VERSION 5.8 ;
BUSBITCHARS "[]" ;
DIVIDERCHAR "/" ;
UNITS
    DATABASE MICRONS 1000 ;
END UNITS

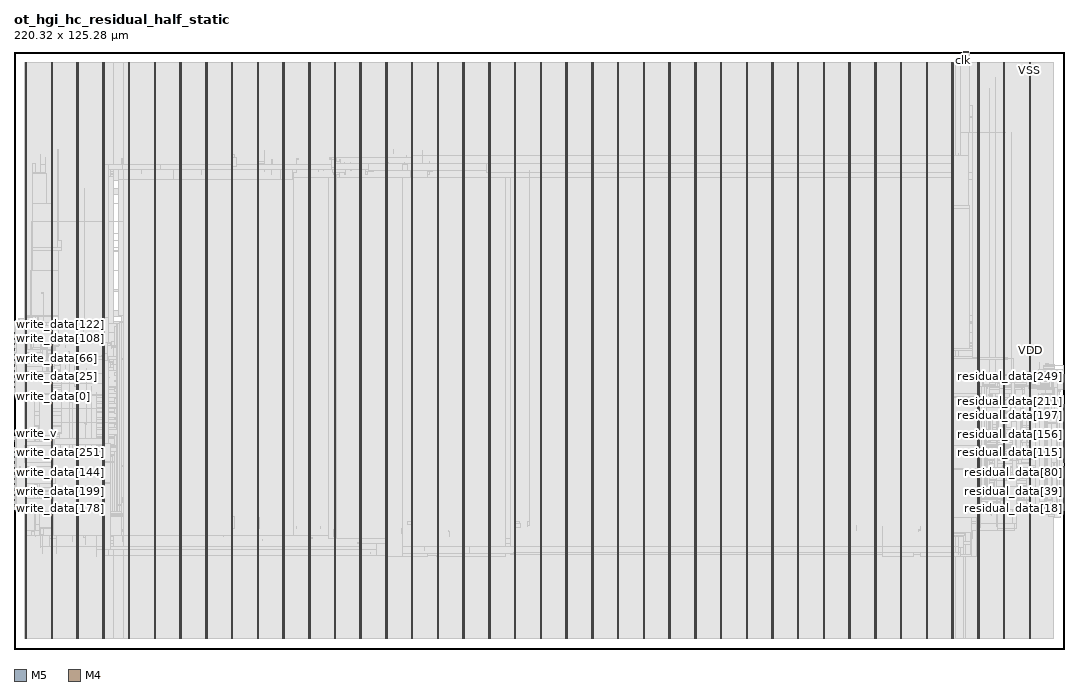
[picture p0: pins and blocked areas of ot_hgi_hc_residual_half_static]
MACRO ot_hgi_hc_residual_half_static
  FOREIGN ot_hgi_hc_residual_half_static 0 0 ;
  CLASS BLOCK ;
  SIZE 220.32 BY 125.28 ;
  PIN clk
    DIRECTION INPUT ;
    USE SIGNAL ;
    PORT
      LAYER M5 ;
        RECT  199.152 125.196 199.176 125.28 ;
    END
  END clk
  PIN fault
    DIRECTION OUTPUT ;
    USE SIGNAL ;
    PORT
      LAYER M4 ;
        RECT  220.236 29.136 220.32 29.16 ;
    END
  END fault
  PIN read_v
    DIRECTION INPUT ;
    USE SIGNAL ;
    PORT
      LAYER M5 ;
        RECT  199.248 125.196 199.272 125.28 ;
    END
  END read_v
  PIN read_valid
    DIRECTION OUTPUT ;
    USE SIGNAL ;
    PORT
      LAYER M4 ;
        RECT  220.236 29.232 220.32 29.256 ;
    END
  END read_valid
  PIN read_word[0]
    DIRECTION INPUT ;
    USE SIGNAL ;
    PORT
      LAYER M5 ;
        RECT  199.344 125.196 199.368 125.28 ;
    END
  END read_word[0]
  PIN read_word[1]
    DIRECTION INPUT ;
    USE SIGNAL ;
    PORT
      LAYER M5 ;
        RECT  199.44 125.196 199.464 125.28 ;
    END
  END read_word[1]
  PIN read_word[2]
    DIRECTION INPUT ;
    USE SIGNAL ;
    PORT
      LAYER M5 ;
        RECT  199.536 125.196 199.56 125.28 ;
    END
  END read_word[2]
  PIN read_word[3]
    DIRECTION INPUT ;
    USE SIGNAL ;
    PORT
      LAYER M5 ;
        RECT  199.632 125.196 199.656 125.28 ;
    END
  END read_word[3]
  PIN read_word[4]
    DIRECTION INPUT ;
    USE SIGNAL ;
    PORT
      LAYER M5 ;
        RECT  199.728 125.196 199.752 125.28 ;
    END
  END read_word[4]
  PIN read_word[5]
    DIRECTION INPUT ;
    USE SIGNAL ;
    PORT
      LAYER M5 ;
        RECT  199.824 125.196 199.848 125.28 ;
    END
  END read_word[5]
  PIN read_word[6]
    DIRECTION INPUT ;
    USE SIGNAL ;
    PORT
      LAYER M5 ;
        RECT  199.92 125.196 199.944 125.28 ;
    END
  END read_word[6]
  PIN read_word[7]
    DIRECTION INPUT ;
    USE SIGNAL ;
    PORT
      LAYER M5 ;
        RECT  200.016 125.196 200.04 125.28 ;
    END
  END read_word[7]
  PIN read_word[8]
    DIRECTION INPUT ;
    USE SIGNAL ;
    PORT
      LAYER M5 ;
        RECT  200.112 125.196 200.136 125.28 ;
    END
  END read_word[8]
  PIN read_word[9]
    DIRECTION INPUT ;
    USE SIGNAL ;
    PORT
      LAYER M5 ;
        RECT  200.208 125.196 200.232 125.28 ;
    END
  END read_word[9]
  PIN residual_data[0]
    DIRECTION OUTPUT ;
    USE SIGNAL ;
    PORT
      LAYER M4 ;
        RECT  220.236 29.328 220.32 29.352 ;
    END
  END residual_data[0]
  PIN residual_data[100]
    DIRECTION OUTPUT ;
    USE SIGNAL ;
    PORT
      LAYER M4 ;
        RECT  220.236 39.696 220.32 39.72 ;
    END
  END residual_data[100]
  PIN residual_data[101]
    DIRECTION OUTPUT ;
    USE SIGNAL ;
    PORT
      LAYER M4 ;
        RECT  220.236 39.792 220.32 39.816 ;
    END
  END residual_data[101]
  PIN residual_data[102]
    DIRECTION OUTPUT ;
    USE SIGNAL ;
    PORT
      LAYER M4 ;
        RECT  220.236 39.888 220.32 39.912 ;
    END
  END residual_data[102]
  PIN residual_data[103]
    DIRECTION OUTPUT ;
    USE SIGNAL ;
    PORT
      LAYER M4 ;
        RECT  220.236 39.984 220.32 40.008 ;
    END
  END residual_data[103]
  PIN residual_data[104]
    DIRECTION OUTPUT ;
    USE SIGNAL ;
    PORT
      LAYER M4 ;
        RECT  220.236 40.08 220.32 40.104 ;
    END
  END residual_data[104]
  PIN residual_data[105]
    DIRECTION OUTPUT ;
    USE SIGNAL ;
    PORT
      LAYER M4 ;
        RECT  220.236 40.176 220.32 40.2 ;
    END
  END residual_data[105]
  PIN residual_data[106]
    DIRECTION OUTPUT ;
    USE SIGNAL ;
    PORT
      LAYER M4 ;
        RECT  220.236 40.272 220.32 40.296 ;
    END
  END residual_data[106]
  PIN residual_data[107]
    DIRECTION OUTPUT ;
    USE SIGNAL ;
    PORT
      LAYER M4 ;
        RECT  220.236 40.368 220.32 40.392 ;
    END
  END residual_data[107]
  PIN residual_data[108]
    DIRECTION OUTPUT ;
    USE SIGNAL ;
    PORT
      LAYER M4 ;
        RECT  220.236 40.464 220.32 40.488 ;
    END
  END residual_data[108]
  PIN residual_data[109]
    DIRECTION OUTPUT ;
    USE SIGNAL ;
    PORT
      LAYER M4 ;
        RECT  220.236 40.56 220.32 40.584 ;
    END
  END residual_data[109]
  PIN residual_data[10]
    DIRECTION OUTPUT ;
    USE SIGNAL ;
    PORT
      LAYER M4 ;
        RECT  220.236 30.288 220.32 30.312 ;
    END
  END residual_data[10]
  PIN residual_data[110]
    DIRECTION OUTPUT ;
    USE SIGNAL ;
    PORT
      LAYER M4 ;
        RECT  220.236 40.656 220.32 40.68 ;
    END
  END residual_data[110]
  PIN residual_data[111]
    DIRECTION OUTPUT ;
    USE SIGNAL ;
    PORT
      LAYER M4 ;
        RECT  220.236 40.752 220.32 40.776 ;
    END
  END residual_data[111]
  PIN residual_data[112]
    DIRECTION OUTPUT ;
    USE SIGNAL ;
    PORT
      LAYER M4 ;
        RECT  220.236 40.848 220.32 40.872 ;
    END
  END residual_data[112]
  PIN residual_data[113]
    DIRECTION OUTPUT ;
    USE SIGNAL ;
    PORT
      LAYER M4 ;
        RECT  220.236 40.944 220.32 40.968 ;
    END
  END residual_data[113]
  PIN residual_data[114]
    DIRECTION OUTPUT ;
    USE SIGNAL ;
    PORT
      LAYER M4 ;
        RECT  220.236 41.04 220.32 41.064 ;
    END
  END residual_data[114]
  PIN residual_data[115]
    DIRECTION OUTPUT ;
    USE SIGNAL ;
    PORT
      LAYER M4 ;
        RECT  220.236 41.136 220.32 41.16 ;
    END
  END residual_data[115]
  PIN residual_data[116]
    DIRECTION OUTPUT ;
    USE SIGNAL ;
    PORT
      LAYER M4 ;
        RECT  220.236 41.232 220.32 41.256 ;
    END
  END residual_data[116]
  PIN residual_data[117]
    DIRECTION OUTPUT ;
    USE SIGNAL ;
    PORT
      LAYER M4 ;
        RECT  220.236 41.328 220.32 41.352 ;
    END
  END residual_data[117]
  PIN residual_data[118]
    DIRECTION OUTPUT ;
    USE SIGNAL ;
    PORT
      LAYER M4 ;
        RECT  220.236 41.424 220.32 41.448 ;
    END
  END residual_data[118]
  PIN residual_data[119]
    DIRECTION OUTPUT ;
    USE SIGNAL ;
    PORT
      LAYER M4 ;
        RECT  220.236 41.52 220.32 41.544 ;
    END
  END residual_data[119]
  PIN residual_data[11]
    DIRECTION OUTPUT ;
    USE SIGNAL ;
    PORT
      LAYER M4 ;
        RECT  220.236 30.384 220.32 30.408 ;
    END
  END residual_data[11]
  PIN residual_data[120]
    DIRECTION OUTPUT ;
    USE SIGNAL ;
    PORT
      LAYER M4 ;
        RECT  220.236 41.616 220.32 41.64 ;
    END
  END residual_data[120]
  PIN residual_data[121]
    DIRECTION OUTPUT ;
    USE SIGNAL ;
    PORT
      LAYER M4 ;
        RECT  220.236 41.712 220.32 41.736 ;
    END
  END residual_data[121]
  PIN residual_data[122]
    DIRECTION OUTPUT ;
    USE SIGNAL ;
    PORT
      LAYER M4 ;
        RECT  220.236 41.808 220.32 41.832 ;
    END
  END residual_data[122]
  PIN residual_data[123]
    DIRECTION OUTPUT ;
    USE SIGNAL ;
    PORT
      LAYER M4 ;
        RECT  220.236 41.904 220.32 41.928 ;
    END
  END residual_data[123]
  PIN residual_data[124]
    DIRECTION OUTPUT ;
    USE SIGNAL ;
    PORT
      LAYER M4 ;
        RECT  220.236 42 220.32 42.024 ;
    END
  END residual_data[124]
  PIN residual_data[125]
    DIRECTION OUTPUT ;
    USE SIGNAL ;
    PORT
      LAYER M4 ;
        RECT  220.236 42.096 220.32 42.12 ;
    END
  END residual_data[125]
  PIN residual_data[126]
    DIRECTION OUTPUT ;
    USE SIGNAL ;
    PORT
      LAYER M4 ;
        RECT  220.236 42.192 220.32 42.216 ;
    END
  END residual_data[126]
  PIN residual_data[127]
    DIRECTION OUTPUT ;
    USE SIGNAL ;
    PORT
      LAYER M4 ;
        RECT  220.236 42.288 220.32 42.312 ;
    END
  END residual_data[127]
  PIN residual_data[128]
    DIRECTION OUTPUT ;
    USE SIGNAL ;
    PORT
      LAYER M4 ;
        RECT  220.236 42.384 220.32 42.408 ;
    END
  END residual_data[128]
  PIN residual_data[129]
    DIRECTION OUTPUT ;
    USE SIGNAL ;
    PORT
      LAYER M4 ;
        RECT  220.236 42.48 220.32 42.504 ;
    END
  END residual_data[129]
  PIN residual_data[12]
    DIRECTION OUTPUT ;
    USE SIGNAL ;
    PORT
      LAYER M4 ;
        RECT  220.236 30.48 220.32 30.504 ;
    END
  END residual_data[12]
  PIN residual_data[130]
    DIRECTION OUTPUT ;
    USE SIGNAL ;
    PORT
      LAYER M4 ;
        RECT  220.236 42.576 220.32 42.6 ;
    END
  END residual_data[130]
  PIN residual_data[131]
    DIRECTION OUTPUT ;
    USE SIGNAL ;
    PORT
      LAYER M4 ;
        RECT  220.236 42.672 220.32 42.696 ;
    END
  END residual_data[131]
  PIN residual_data[132]
    DIRECTION OUTPUT ;
    USE SIGNAL ;
    PORT
      LAYER M4 ;
        RECT  220.236 42.768 220.32 42.792 ;
    END
  END residual_data[132]
  PIN residual_data[133]
    DIRECTION OUTPUT ;
    USE SIGNAL ;
    PORT
      LAYER M4 ;
        RECT  220.236 42.864 220.32 42.888 ;
    END
  END residual_data[133]
  PIN residual_data[134]
    DIRECTION OUTPUT ;
    USE SIGNAL ;
    PORT
      LAYER M4 ;
        RECT  220.236 42.96 220.32 42.984 ;
    END
  END residual_data[134]
  PIN residual_data[135]
    DIRECTION OUTPUT ;
    USE SIGNAL ;
    PORT
      LAYER M4 ;
        RECT  220.236 43.056 220.32 43.08 ;
    END
  END residual_data[135]
  PIN residual_data[136]
    DIRECTION OUTPUT ;
    USE SIGNAL ;
    PORT
      LAYER M4 ;
        RECT  220.236 43.152 220.32 43.176 ;
    END
  END residual_data[136]
  PIN residual_data[137]
    DIRECTION OUTPUT ;
    USE SIGNAL ;
    PORT
      LAYER M4 ;
        RECT  220.236 43.248 220.32 43.272 ;
    END
  END residual_data[137]
  PIN residual_data[138]
    DIRECTION OUTPUT ;
    USE SIGNAL ;
    PORT
      LAYER M4 ;
        RECT  220.236 43.344 220.32 43.368 ;
    END
  END residual_data[138]
  PIN residual_data[139]
    DIRECTION OUTPUT ;
    USE SIGNAL ;
    PORT
      LAYER M4 ;
        RECT  220.236 43.44 220.32 43.464 ;
    END
  END residual_data[139]
  PIN residual_data[13]
    DIRECTION OUTPUT ;
    USE SIGNAL ;
    PORT
      LAYER M4 ;
        RECT  220.236 30.576 220.32 30.6 ;
    END
  END residual_data[13]
  PIN residual_data[140]
    DIRECTION OUTPUT ;
    USE SIGNAL ;
    PORT
      LAYER M4 ;
        RECT  220.236 43.536 220.32 43.56 ;
    END
  END residual_data[140]
  PIN residual_data[141]
    DIRECTION OUTPUT ;
    USE SIGNAL ;
    PORT
      LAYER M4 ;
        RECT  220.236 43.632 220.32 43.656 ;
    END
  END residual_data[141]
  PIN residual_data[142]
    DIRECTION OUTPUT ;
    USE SIGNAL ;
    PORT
      LAYER M4 ;
        RECT  220.236 43.728 220.32 43.752 ;
    END
  END residual_data[142]
  PIN residual_data[143]
    DIRECTION OUTPUT ;
    USE SIGNAL ;
    PORT
      LAYER M4 ;
        RECT  220.236 43.824 220.32 43.848 ;
    END
  END residual_data[143]
  PIN residual_data[144]
    DIRECTION OUTPUT ;
    USE SIGNAL ;
    PORT
      LAYER M4 ;
        RECT  220.236 43.92 220.32 43.944 ;
    END
  END residual_data[144]
  PIN residual_data[145]
    DIRECTION OUTPUT ;
    USE SIGNAL ;
    PORT
      LAYER M4 ;
        RECT  220.236 44.016 220.32 44.04 ;
    END
  END residual_data[145]
  PIN residual_data[146]
    DIRECTION OUTPUT ;
    USE SIGNAL ;
    PORT
      LAYER M4 ;
        RECT  220.236 44.112 220.32 44.136 ;
    END
  END residual_data[146]
  PIN residual_data[147]
    DIRECTION OUTPUT ;
    USE SIGNAL ;
    PORT
      LAYER M4 ;
        RECT  220.236 44.208 220.32 44.232 ;
    END
  END residual_data[147]
  PIN residual_data[148]
    DIRECTION OUTPUT ;
    USE SIGNAL ;
    PORT
      LAYER M4 ;
        RECT  220.236 44.304 220.32 44.328 ;
    END
  END residual_data[148]
  PIN residual_data[149]
    DIRECTION OUTPUT ;
    USE SIGNAL ;
    PORT
      LAYER M4 ;
        RECT  220.236 44.4 220.32 44.424 ;
    END
  END residual_data[149]
  PIN residual_data[14]
    DIRECTION OUTPUT ;
    USE SIGNAL ;
    PORT
      LAYER M4 ;
        RECT  220.236 30.672 220.32 30.696 ;
    END
  END residual_data[14]
  PIN residual_data[150]
    DIRECTION OUTPUT ;
    USE SIGNAL ;
    PORT
      LAYER M4 ;
        RECT  220.236 44.496 220.32 44.52 ;
    END
  END residual_data[150]
  PIN residual_data[151]
    DIRECTION OUTPUT ;
    USE SIGNAL ;
    PORT
      LAYER M4 ;
        RECT  220.236 44.592 220.32 44.616 ;
    END
  END residual_data[151]
  PIN residual_data[152]
    DIRECTION OUTPUT ;
    USE SIGNAL ;
    PORT
      LAYER M4 ;
        RECT  220.236 44.688 220.32 44.712 ;
    END
  END residual_data[152]
  PIN residual_data[153]
    DIRECTION OUTPUT ;
    USE SIGNAL ;
    PORT
      LAYER M4 ;
        RECT  220.236 44.784 220.32 44.808 ;
    END
  END residual_data[153]
  PIN residual_data[154]
    DIRECTION OUTPUT ;
    USE SIGNAL ;
    PORT
      LAYER M4 ;
        RECT  220.236 44.88 220.32 44.904 ;
    END
  END residual_data[154]
  PIN residual_data[155]
    DIRECTION OUTPUT ;
    USE SIGNAL ;
    PORT
      LAYER M4 ;
        RECT  220.236 44.976 220.32 45 ;
    END
  END residual_data[155]
  PIN residual_data[156]
    DIRECTION OUTPUT ;
    USE SIGNAL ;
    PORT
      LAYER M4 ;
        RECT  220.236 45.072 220.32 45.096 ;
    END
  END residual_data[156]
  PIN residual_data[157]
    DIRECTION OUTPUT ;
    USE SIGNAL ;
    PORT
      LAYER M4 ;
        RECT  220.236 45.168 220.32 45.192 ;
    END
  END residual_data[157]
  PIN residual_data[158]
    DIRECTION OUTPUT ;
    USE SIGNAL ;
    PORT
      LAYER M4 ;
        RECT  220.236 45.264 220.32 45.288 ;
    END
  END residual_data[158]
  PIN residual_data[159]
    DIRECTION OUTPUT ;
    USE SIGNAL ;
    PORT
      LAYER M4 ;
        RECT  220.236 45.36 220.32 45.384 ;
    END
  END residual_data[159]
  PIN residual_data[15]
    DIRECTION OUTPUT ;
    USE SIGNAL ;
    PORT
      LAYER M4 ;
        RECT  220.236 30.768 220.32 30.792 ;
    END
  END residual_data[15]
  PIN residual_data[160]
    DIRECTION OUTPUT ;
    USE SIGNAL ;
    PORT
      LAYER M4 ;
        RECT  220.236 45.456 220.32 45.48 ;
    END
  END residual_data[160]
  PIN residual_data[161]
    DIRECTION OUTPUT ;
    USE SIGNAL ;
    PORT
      LAYER M4 ;
        RECT  220.236 45.552 220.32 45.576 ;
    END
  END residual_data[161]
  PIN residual_data[162]
    DIRECTION OUTPUT ;
    USE SIGNAL ;
    PORT
      LAYER M4 ;
        RECT  220.236 45.648 220.32 45.672 ;
    END
  END residual_data[162]
  PIN residual_data[163]
    DIRECTION OUTPUT ;
    USE SIGNAL ;
    PORT
      LAYER M4 ;
        RECT  220.236 45.744 220.32 45.768 ;
    END
  END residual_data[163]
  PIN residual_data[164]
    DIRECTION OUTPUT ;
    USE SIGNAL ;
    PORT
      LAYER M4 ;
        RECT  220.236 45.84 220.32 45.864 ;
    END
  END residual_data[164]
  PIN residual_data[165]
    DIRECTION OUTPUT ;
    USE SIGNAL ;
    PORT
      LAYER M4 ;
        RECT  220.236 45.936 220.32 45.96 ;
    END
  END residual_data[165]
  PIN residual_data[166]
    DIRECTION OUTPUT ;
    USE SIGNAL ;
    PORT
      LAYER M4 ;
        RECT  220.236 46.032 220.32 46.056 ;
    END
  END residual_data[166]
  PIN residual_data[167]
    DIRECTION OUTPUT ;
    USE SIGNAL ;
    PORT
      LAYER M4 ;
        RECT  220.236 46.128 220.32 46.152 ;
    END
  END residual_data[167]
  PIN residual_data[168]
    DIRECTION OUTPUT ;
    USE SIGNAL ;
    PORT
      LAYER M4 ;
        RECT  220.236 46.224 220.32 46.248 ;
    END
  END residual_data[168]
  PIN residual_data[169]
    DIRECTION OUTPUT ;
    USE SIGNAL ;
    PORT
      LAYER M4 ;
        RECT  220.236 46.32 220.32 46.344 ;
    END
  END residual_data[169]
  PIN residual_data[16]
    DIRECTION OUTPUT ;
    USE SIGNAL ;
    PORT
      LAYER M4 ;
        RECT  220.236 30.864 220.32 30.888 ;
    END
  END residual_data[16]
  PIN residual_data[170]
    DIRECTION OUTPUT ;
    USE SIGNAL ;
    PORT
      LAYER M4 ;
        RECT  220.236 46.416 220.32 46.44 ;
    END
  END residual_data[170]
  PIN residual_data[171]
    DIRECTION OUTPUT ;
    USE SIGNAL ;
    PORT
      LAYER M4 ;
        RECT  220.236 46.512 220.32 46.536 ;
    END
  END residual_data[171]
  PIN residual_data[172]
    DIRECTION OUTPUT ;
    USE SIGNAL ;
    PORT
      LAYER M4 ;
        RECT  220.236 46.608 220.32 46.632 ;
    END
  END residual_data[172]
  PIN residual_data[173]
    DIRECTION OUTPUT ;
    USE SIGNAL ;
    PORT
      LAYER M4 ;
        RECT  220.236 46.704 220.32 46.728 ;
    END
  END residual_data[173]
  PIN residual_data[174]
    DIRECTION OUTPUT ;
    USE SIGNAL ;
    PORT
      LAYER M4 ;
        RECT  220.236 46.8 220.32 46.824 ;
    END
  END residual_data[174]
  PIN residual_data[175]
    DIRECTION OUTPUT ;
    USE SIGNAL ;
    PORT
      LAYER M4 ;
        RECT  220.236 46.896 220.32 46.92 ;
    END
  END residual_data[175]
  PIN residual_data[176]
    DIRECTION OUTPUT ;
    USE SIGNAL ;
    PORT
      LAYER M4 ;
        RECT  220.236 46.992 220.32 47.016 ;
    END
  END residual_data[176]
  PIN residual_data[177]
    DIRECTION OUTPUT ;
    USE SIGNAL ;
    PORT
      LAYER M4 ;
        RECT  220.236 47.088 220.32 47.112 ;
    END
  END residual_data[177]
  PIN residual_data[178]
    DIRECTION OUTPUT ;
    USE SIGNAL ;
    PORT
      LAYER M4 ;
        RECT  220.236 47.184 220.32 47.208 ;
    END
  END residual_data[178]
  PIN residual_data[179]
    DIRECTION OUTPUT ;
    USE SIGNAL ;
    PORT
      LAYER M4 ;
        RECT  220.236 47.28 220.32 47.304 ;
    END
  END residual_data[179]
  PIN residual_data[17]
    DIRECTION OUTPUT ;
    USE SIGNAL ;
    PORT
      LAYER M4 ;
        RECT  220.236 30.96 220.32 30.984 ;
    END
  END residual_data[17]
  PIN residual_data[180]
    DIRECTION OUTPUT ;
    USE SIGNAL ;
    PORT
      LAYER M4 ;
        RECT  220.236 47.376 220.32 47.4 ;
    END
  END residual_data[180]
  PIN residual_data[181]
    DIRECTION OUTPUT ;
    USE SIGNAL ;
    PORT
      LAYER M4 ;
        RECT  220.236 47.472 220.32 47.496 ;
    END
  END residual_data[181]
  PIN residual_data[182]
    DIRECTION OUTPUT ;
    USE SIGNAL ;
    PORT
      LAYER M4 ;
        RECT  220.236 47.568 220.32 47.592 ;
    END
  END residual_data[182]
  PIN residual_data[183]
    DIRECTION OUTPUT ;
    USE SIGNAL ;
    PORT
      LAYER M4 ;
        RECT  220.236 47.664 220.32 47.688 ;
    END
  END residual_data[183]
  PIN residual_data[184]
    DIRECTION OUTPUT ;
    USE SIGNAL ;
    PORT
      LAYER M4 ;
        RECT  220.236 47.76 220.32 47.784 ;
    END
  END residual_data[184]
  PIN residual_data[185]
    DIRECTION OUTPUT ;
    USE SIGNAL ;
    PORT
      LAYER M4 ;
        RECT  220.236 47.856 220.32 47.88 ;
    END
  END residual_data[185]
  PIN residual_data[186]
    DIRECTION OUTPUT ;
    USE SIGNAL ;
    PORT
      LAYER M4 ;
        RECT  220.236 47.952 220.32 47.976 ;
    END
  END residual_data[186]
  PIN residual_data[187]
    DIRECTION OUTPUT ;
    USE SIGNAL ;
    PORT
      LAYER M4 ;
        RECT  220.236 48.048 220.32 48.072 ;
    END
  END residual_data[187]
  PIN residual_data[188]
    DIRECTION OUTPUT ;
    USE SIGNAL ;
    PORT
      LAYER M4 ;
        RECT  220.236 48.144 220.32 48.168 ;
    END
  END residual_data[188]
  PIN residual_data[189]
    DIRECTION OUTPUT ;
    USE SIGNAL ;
    PORT
      LAYER M4 ;
        RECT  220.236 48.24 220.32 48.264 ;
    END
  END residual_data[189]
  PIN residual_data[18]
    DIRECTION OUTPUT ;
    USE SIGNAL ;
    PORT
      LAYER M4 ;
        RECT  220.236 31.056 220.32 31.08 ;
    END
  END residual_data[18]
  PIN residual_data[190]
    DIRECTION OUTPUT ;
    USE SIGNAL ;
    PORT
      LAYER M4 ;
        RECT  220.236 48.336 220.32 48.36 ;
    END
  END residual_data[190]
  PIN residual_data[191]
    DIRECTION OUTPUT ;
    USE SIGNAL ;
    PORT
      LAYER M4 ;
        RECT  220.236 48.432 220.32 48.456 ;
    END
  END residual_data[191]
  PIN residual_data[192]
    DIRECTION OUTPUT ;
    USE SIGNAL ;
    PORT
      LAYER M4 ;
        RECT  220.236 48.528 220.32 48.552 ;
    END
  END residual_data[192]
  PIN residual_data[193]
    DIRECTION OUTPUT ;
    USE SIGNAL ;
    PORT
      LAYER M4 ;
        RECT  220.236 48.624 220.32 48.648 ;
    END
  END residual_data[193]
  PIN residual_data[194]
    DIRECTION OUTPUT ;
    USE SIGNAL ;
    PORT
      LAYER M4 ;
        RECT  220.236 48.72 220.32 48.744 ;
    END
  END residual_data[194]
  PIN residual_data[195]
    DIRECTION OUTPUT ;
    USE SIGNAL ;
    PORT
      LAYER M4 ;
        RECT  220.236 48.816 220.32 48.84 ;
    END
  END residual_data[195]
  PIN residual_data[196]
    DIRECTION OUTPUT ;
    USE SIGNAL ;
    PORT
      LAYER M4 ;
        RECT  220.236 48.912 220.32 48.936 ;
    END
  END residual_data[196]
  PIN residual_data[197]
    DIRECTION OUTPUT ;
    USE SIGNAL ;
    PORT
      LAYER M4 ;
        RECT  220.236 49.008 220.32 49.032 ;
    END
  END residual_data[197]
  PIN residual_data[198]
    DIRECTION OUTPUT ;
    USE SIGNAL ;
    PORT
      LAYER M4 ;
        RECT  220.236 49.104 220.32 49.128 ;
    END
  END residual_data[198]
  PIN residual_data[199]
    DIRECTION OUTPUT ;
    USE SIGNAL ;
    PORT
      LAYER M4 ;
        RECT  220.236 49.2 220.32 49.224 ;
    END
  END residual_data[199]
  PIN residual_data[19]
    DIRECTION OUTPUT ;
    USE SIGNAL ;
    PORT
      LAYER M4 ;
        RECT  220.236 31.152 220.32 31.176 ;
    END
  END residual_data[19]
  PIN residual_data[1]
    DIRECTION OUTPUT ;
    USE SIGNAL ;
    PORT
      LAYER M4 ;
        RECT  220.236 29.424 220.32 29.448 ;
    END
  END residual_data[1]
  PIN residual_data[200]
    DIRECTION OUTPUT ;
    USE SIGNAL ;
    PORT
      LAYER M4 ;
        RECT  220.236 49.296 220.32 49.32 ;
    END
  END residual_data[200]
  PIN residual_data[201]
    DIRECTION OUTPUT ;
    USE SIGNAL ;
    PORT
      LAYER M4 ;
        RECT  220.236 49.392 220.32 49.416 ;
    END
  END residual_data[201]
  PIN residual_data[202]
    DIRECTION OUTPUT ;
    USE SIGNAL ;
    PORT
      LAYER M4 ;
        RECT  220.236 49.488 220.32 49.512 ;
    END
  END residual_data[202]
  PIN residual_data[203]
    DIRECTION OUTPUT ;
    USE SIGNAL ;
    PORT
      LAYER M4 ;
        RECT  220.236 49.584 220.32 49.608 ;
    END
  END residual_data[203]
  PIN residual_data[204]
    DIRECTION OUTPUT ;
    USE SIGNAL ;
    PORT
      LAYER M4 ;
        RECT  220.236 49.68 220.32 49.704 ;
    END
  END residual_data[204]
  PIN residual_data[205]
    DIRECTION OUTPUT ;
    USE SIGNAL ;
    PORT
      LAYER M4 ;
        RECT  220.236 49.776 220.32 49.8 ;
    END
  END residual_data[205]
  PIN residual_data[206]
    DIRECTION OUTPUT ;
    USE SIGNAL ;
    PORT
      LAYER M4 ;
        RECT  220.236 49.872 220.32 49.896 ;
    END
  END residual_data[206]
  PIN residual_data[207]
    DIRECTION OUTPUT ;
    USE SIGNAL ;
    PORT
      LAYER M4 ;
        RECT  220.236 49.968 220.32 49.992 ;
    END
  END residual_data[207]
  PIN residual_data[208]
    DIRECTION OUTPUT ;
    USE SIGNAL ;
    PORT
      LAYER M4 ;
        RECT  220.236 50.064 220.32 50.088 ;
    END
  END residual_data[208]
  PIN residual_data[209]
    DIRECTION OUTPUT ;
    USE SIGNAL ;
    PORT
      LAYER M4 ;
        RECT  220.236 50.16 220.32 50.184 ;
    END
  END residual_data[209]
  PIN residual_data[20]
    DIRECTION OUTPUT ;
    USE SIGNAL ;
    PORT
      LAYER M4 ;
        RECT  220.236 31.248 220.32 31.272 ;
    END
  END residual_data[20]
  PIN residual_data[210]
    DIRECTION OUTPUT ;
    USE SIGNAL ;
    PORT
      LAYER M4 ;
        RECT  220.236 50.256 220.32 50.28 ;
    END
  END residual_data[210]
  PIN residual_data[211]
    DIRECTION OUTPUT ;
    USE SIGNAL ;
    PORT
      LAYER M4 ;
        RECT  220.236 50.352 220.32 50.376 ;
    END
  END residual_data[211]
  PIN residual_data[212]
    DIRECTION OUTPUT ;
    USE SIGNAL ;
    PORT
      LAYER M4 ;
        RECT  220.236 50.448 220.32 50.472 ;
    END
  END residual_data[212]
  PIN residual_data[213]
    DIRECTION OUTPUT ;
    USE SIGNAL ;
    PORT
      LAYER M4 ;
        RECT  220.236 50.544 220.32 50.568 ;
    END
  END residual_data[213]
  PIN residual_data[214]
    DIRECTION OUTPUT ;
    USE SIGNAL ;
    PORT
      LAYER M4 ;
        RECT  220.236 50.64 220.32 50.664 ;
    END
  END residual_data[214]
  PIN residual_data[215]
    DIRECTION OUTPUT ;
    USE SIGNAL ;
    PORT
      LAYER M4 ;
        RECT  220.236 50.736 220.32 50.76 ;
    END
  END residual_data[215]
  PIN residual_data[216]
    DIRECTION OUTPUT ;
    USE SIGNAL ;
    PORT
      LAYER M4 ;
        RECT  220.236 50.832 220.32 50.856 ;
    END
  END residual_data[216]
  PIN residual_data[217]
    DIRECTION OUTPUT ;
    USE SIGNAL ;
    PORT
      LAYER M4 ;
        RECT  220.236 50.928 220.32 50.952 ;
    END
  END residual_data[217]
  PIN residual_data[218]
    DIRECTION OUTPUT ;
    USE SIGNAL ;
    PORT
      LAYER M4 ;
        RECT  220.236 51.024 220.32 51.048 ;
    END
  END residual_data[218]
  PIN residual_data[219]
    DIRECTION OUTPUT ;
    USE SIGNAL ;
    PORT
      LAYER M4 ;
        RECT  220.236 51.12 220.32 51.144 ;
    END
  END residual_data[219]
  PIN residual_data[21]
    DIRECTION OUTPUT ;
    USE SIGNAL ;
    PORT
      LAYER M4 ;
        RECT  220.236 31.344 220.32 31.368 ;
    END
  END residual_data[21]
  PIN residual_data[220]
    DIRECTION OUTPUT ;
    USE SIGNAL ;
    PORT
      LAYER M4 ;
        RECT  220.236 51.216 220.32 51.24 ;
    END
  END residual_data[220]
  PIN residual_data[221]
    DIRECTION OUTPUT ;
    USE SIGNAL ;
    PORT
      LAYER M4 ;
        RECT  220.236 51.312 220.32 51.336 ;
    END
  END residual_data[221]
  PIN residual_data[222]
    DIRECTION OUTPUT ;
    USE SIGNAL ;
    PORT
      LAYER M4 ;
        RECT  220.236 54.48 220.32 54.504 ;
    END
  END residual_data[222]
  PIN residual_data[223]
    DIRECTION OUTPUT ;
    USE SIGNAL ;
    PORT
      LAYER M4 ;
        RECT  220.236 54.576 220.32 54.6 ;
    END
  END residual_data[223]
  PIN residual_data[224]
    DIRECTION OUTPUT ;
    USE SIGNAL ;
    PORT
      LAYER M4 ;
        RECT  220.236 54.672 220.32 54.696 ;
    END
  END residual_data[224]
  PIN residual_data[225]
    DIRECTION OUTPUT ;
    USE SIGNAL ;
    PORT
      LAYER M4 ;
        RECT  220.236 54.768 220.32 54.792 ;
    END
  END residual_data[225]
  PIN residual_data[226]
    DIRECTION OUTPUT ;
    USE SIGNAL ;
    PORT
      LAYER M4 ;
        RECT  220.236 54.864 220.32 54.888 ;
    END
  END residual_data[226]
  PIN residual_data[227]
    DIRECTION OUTPUT ;
    USE SIGNAL ;
    PORT
      LAYER M4 ;
        RECT  220.236 54.96 220.32 54.984 ;
    END
  END residual_data[227]
  PIN residual_data[228]
    DIRECTION OUTPUT ;
    USE SIGNAL ;
    PORT
      LAYER M4 ;
        RECT  220.236 55.056 220.32 55.08 ;
    END
  END residual_data[228]
  PIN residual_data[229]
    DIRECTION OUTPUT ;
    USE SIGNAL ;
    PORT
      LAYER M4 ;
        RECT  220.236 55.152 220.32 55.176 ;
    END
  END residual_data[229]
  PIN residual_data[22]
    DIRECTION OUTPUT ;
    USE SIGNAL ;
    PORT
      LAYER M4 ;
        RECT  220.236 31.44 220.32 31.464 ;
    END
  END residual_data[22]
  PIN residual_data[230]
    DIRECTION OUTPUT ;
    USE SIGNAL ;
    PORT
      LAYER M4 ;
        RECT  220.236 55.248 220.32 55.272 ;
    END
  END residual_data[230]
  PIN residual_data[231]
    DIRECTION OUTPUT ;
    USE SIGNAL ;
    PORT
      LAYER M4 ;
        RECT  220.236 55.344 220.32 55.368 ;
    END
  END residual_data[231]
  PIN residual_data[232]
    DIRECTION OUTPUT ;
    USE SIGNAL ;
    PORT
      LAYER M4 ;
        RECT  220.236 55.44 220.32 55.464 ;
    END
  END residual_data[232]
  PIN residual_data[233]
    DIRECTION OUTPUT ;
    USE SIGNAL ;
    PORT
      LAYER M4 ;
        RECT  220.236 55.536 220.32 55.56 ;
    END
  END residual_data[233]
  PIN residual_data[234]
    DIRECTION OUTPUT ;
    USE SIGNAL ;
    PORT
      LAYER M4 ;
        RECT  220.236 55.632 220.32 55.656 ;
    END
  END residual_data[234]
  PIN residual_data[235]
    DIRECTION OUTPUT ;
    USE SIGNAL ;
    PORT
      LAYER M4 ;
        RECT  220.236 55.728 220.32 55.752 ;
    END
  END residual_data[235]
  PIN residual_data[236]
    DIRECTION OUTPUT ;
    USE SIGNAL ;
    PORT
      LAYER M4 ;
        RECT  220.236 55.824 220.32 55.848 ;
    END
  END residual_data[236]
  PIN residual_data[237]
    DIRECTION OUTPUT ;
    USE SIGNAL ;
    PORT
      LAYER M4 ;
        RECT  220.236 55.92 220.32 55.944 ;
    END
  END residual_data[237]
  PIN residual_data[238]
    DIRECTION OUTPUT ;
    USE SIGNAL ;
    PORT
      LAYER M4 ;
        RECT  220.236 56.016 220.32 56.04 ;
    END
  END residual_data[238]
  PIN residual_data[239]
    DIRECTION OUTPUT ;
    USE SIGNAL ;
    PORT
      LAYER M4 ;
        RECT  220.236 56.112 220.32 56.136 ;
    END
  END residual_data[239]
  PIN residual_data[23]
    DIRECTION OUTPUT ;
    USE SIGNAL ;
    PORT
      LAYER M4 ;
        RECT  220.236 31.536 220.32 31.56 ;
    END
  END residual_data[23]
  PIN residual_data[240]
    DIRECTION OUTPUT ;
    USE SIGNAL ;
    PORT
      LAYER M4 ;
        RECT  220.236 56.208 220.32 56.232 ;
    END
  END residual_data[240]
  PIN residual_data[241]
    DIRECTION OUTPUT ;
    USE SIGNAL ;
    PORT
      LAYER M4 ;
        RECT  220.236 56.304 220.32 56.328 ;
    END
  END residual_data[241]
  PIN residual_data[242]
    DIRECTION OUTPUT ;
    USE SIGNAL ;
    PORT
      LAYER M4 ;
        RECT  220.236 56.4 220.32 56.424 ;
    END
  END residual_data[242]
  PIN residual_data[243]
    DIRECTION OUTPUT ;
    USE SIGNAL ;
    PORT
      LAYER M4 ;
        RECT  220.236 56.496 220.32 56.52 ;
    END
  END residual_data[243]
  PIN residual_data[244]
    DIRECTION OUTPUT ;
    USE SIGNAL ;
    PORT
      LAYER M4 ;
        RECT  220.236 56.592 220.32 56.616 ;
    END
  END residual_data[244]
  PIN residual_data[245]
    DIRECTION OUTPUT ;
    USE SIGNAL ;
    PORT
      LAYER M4 ;
        RECT  220.236 56.688 220.32 56.712 ;
    END
  END residual_data[245]
  PIN residual_data[246]
    DIRECTION OUTPUT ;
    USE SIGNAL ;
    PORT
      LAYER M4 ;
        RECT  220.236 56.784 220.32 56.808 ;
    END
  END residual_data[246]
  PIN residual_data[247]
    DIRECTION OUTPUT ;
    USE SIGNAL ;
    PORT
      LAYER M4 ;
        RECT  220.236 56.88 220.32 56.904 ;
    END
  END residual_data[247]
  PIN residual_data[248]
    DIRECTION OUTPUT ;
    USE SIGNAL ;
    PORT
      LAYER M4 ;
        RECT  220.236 56.976 220.32 57 ;
    END
  END residual_data[248]
  PIN residual_data[249]
    DIRECTION OUTPUT ;
    USE SIGNAL ;
    PORT
      LAYER M4 ;
        RECT  220.236 57.072 220.32 57.096 ;
    END
  END residual_data[249]
  PIN residual_data[24]
    DIRECTION OUTPUT ;
    USE SIGNAL ;
    PORT
      LAYER M4 ;
        RECT  220.236 31.632 220.32 31.656 ;
    END
  END residual_data[24]
  PIN residual_data[250]
    DIRECTION OUTPUT ;
    USE SIGNAL ;
    PORT
      LAYER M4 ;
        RECT  220.236 57.168 220.32 57.192 ;
    END
  END residual_data[250]
  PIN residual_data[251]
    DIRECTION OUTPUT ;
    USE SIGNAL ;
    PORT
      LAYER M4 ;
        RECT  220.236 57.264 220.32 57.288 ;
    END
  END residual_data[251]
  PIN residual_data[252]
    DIRECTION OUTPUT ;
    USE SIGNAL ;
    PORT
      LAYER M4 ;
        RECT  220.236 57.36 220.32 57.384 ;
    END
  END residual_data[252]
  PIN residual_data[253]
    DIRECTION OUTPUT ;
    USE SIGNAL ;
    PORT
      LAYER M4 ;
        RECT  220.236 57.456 220.32 57.48 ;
    END
  END residual_data[253]
  PIN residual_data[254]
    DIRECTION OUTPUT ;
    USE SIGNAL ;
    PORT
      LAYER M4 ;
        RECT  220.236 57.552 220.32 57.576 ;
    END
  END residual_data[254]
  PIN residual_data[255]
    DIRECTION OUTPUT ;
    USE SIGNAL ;
    PORT
      LAYER M4 ;
        RECT  220.236 57.648 220.32 57.672 ;
    END
  END residual_data[255]
  PIN residual_data[25]
    DIRECTION OUTPUT ;
    USE SIGNAL ;
    PORT
      LAYER M4 ;
        RECT  220.236 31.728 220.32 31.752 ;
    END
  END residual_data[25]
  PIN residual_data[26]
    DIRECTION OUTPUT ;
    USE SIGNAL ;
    PORT
      LAYER M4 ;
        RECT  220.236 31.824 220.32 31.848 ;
    END
  END residual_data[26]
  PIN residual_data[27]
    DIRECTION OUTPUT ;
    USE SIGNAL ;
    PORT
      LAYER M4 ;
        RECT  220.236 31.92 220.32 31.944 ;
    END
  END residual_data[27]
  PIN residual_data[28]
    DIRECTION OUTPUT ;
    USE SIGNAL ;
    PORT
      LAYER M4 ;
        RECT  220.236 32.016 220.32 32.04 ;
    END
  END residual_data[28]
  PIN residual_data[29]
    DIRECTION OUTPUT ;
    USE SIGNAL ;
    PORT
      LAYER M4 ;
        RECT  220.236 32.112 220.32 32.136 ;
    END
  END residual_data[29]
  PIN residual_data[2]
    DIRECTION OUTPUT ;
    USE SIGNAL ;
    PORT
      LAYER M4 ;
        RECT  220.236 29.52 220.32 29.544 ;
    END
  END residual_data[2]
  PIN residual_data[30]
    DIRECTION OUTPUT ;
    USE SIGNAL ;
    PORT
      LAYER M4 ;
        RECT  220.236 32.208 220.32 32.232 ;
    END
  END residual_data[30]
  PIN residual_data[31]
    DIRECTION OUTPUT ;
    USE SIGNAL ;
    PORT
      LAYER M4 ;
        RECT  220.236 32.304 220.32 32.328 ;
    END
  END residual_data[31]
  PIN residual_data[32]
    DIRECTION OUTPUT ;
    USE SIGNAL ;
    PORT
      LAYER M4 ;
        RECT  220.236 32.4 220.32 32.424 ;
    END
  END residual_data[32]
  PIN residual_data[33]
    DIRECTION OUTPUT ;
    USE SIGNAL ;
    PORT
      LAYER M4 ;
        RECT  220.236 32.496 220.32 32.52 ;
    END
  END residual_data[33]
  PIN residual_data[34]
    DIRECTION OUTPUT ;
    USE SIGNAL ;
    PORT
      LAYER M4 ;
        RECT  220.236 32.592 220.32 32.616 ;
    END
  END residual_data[34]
  PIN residual_data[35]
    DIRECTION OUTPUT ;
    USE SIGNAL ;
    PORT
      LAYER M4 ;
        RECT  220.236 32.688 220.32 32.712 ;
    END
  END residual_data[35]
  PIN residual_data[36]
    DIRECTION OUTPUT ;
    USE SIGNAL ;
    PORT
      LAYER M4 ;
        RECT  220.236 32.784 220.32 32.808 ;
    END
  END residual_data[36]
  PIN residual_data[37]
    DIRECTION OUTPUT ;
    USE SIGNAL ;
    PORT
      LAYER M4 ;
        RECT  220.236 32.88 220.32 32.904 ;
    END
  END residual_data[37]
  PIN residual_data[38]
    DIRECTION OUTPUT ;
    USE SIGNAL ;
    PORT
      LAYER M4 ;
        RECT  220.236 32.976 220.32 33 ;
    END
  END residual_data[38]
  PIN residual_data[39]
    DIRECTION OUTPUT ;
    USE SIGNAL ;
    PORT
      LAYER M4 ;
        RECT  220.236 33.072 220.32 33.096 ;
    END
  END residual_data[39]
  PIN residual_data[3]
    DIRECTION OUTPUT ;
    USE SIGNAL ;
    PORT
      LAYER M4 ;
        RECT  220.236 29.616 220.32 29.64 ;
    END
  END residual_data[3]
  PIN residual_data[40]
    DIRECTION OUTPUT ;
    USE SIGNAL ;
    PORT
      LAYER M4 ;
        RECT  220.236 33.168 220.32 33.192 ;
    END
  END residual_data[40]
  PIN residual_data[41]
    DIRECTION OUTPUT ;
    USE SIGNAL ;
    PORT
      LAYER M4 ;
        RECT  220.236 33.264 220.32 33.288 ;
    END
  END residual_data[41]
  PIN residual_data[42]
    DIRECTION OUTPUT ;
    USE SIGNAL ;
    PORT
      LAYER M4 ;
        RECT  220.236 33.36 220.32 33.384 ;
    END
  END residual_data[42]
  PIN residual_data[43]
    DIRECTION OUTPUT ;
    USE SIGNAL ;
    PORT
      LAYER M4 ;
        RECT  220.236 33.456 220.32 33.48 ;
    END
  END residual_data[43]
  PIN residual_data[44]
    DIRECTION OUTPUT ;
    USE SIGNAL ;
    PORT
      LAYER M4 ;
        RECT  220.236 33.552 220.32 33.576 ;
    END
  END residual_data[44]
  PIN residual_data[45]
    DIRECTION OUTPUT ;
    USE SIGNAL ;
    PORT
      LAYER M4 ;
        RECT  220.236 33.648 220.32 33.672 ;
    END
  END residual_data[45]
  PIN residual_data[46]
    DIRECTION OUTPUT ;
    USE SIGNAL ;
    PORT
      LAYER M4 ;
        RECT  220.236 33.744 220.32 33.768 ;
    END
  END residual_data[46]
  PIN residual_data[47]
    DIRECTION OUTPUT ;
    USE SIGNAL ;
    PORT
      LAYER M4 ;
        RECT  220.236 33.84 220.32 33.864 ;
    END
  END residual_data[47]
  PIN residual_data[48]
    DIRECTION OUTPUT ;
    USE SIGNAL ;
    PORT
      LAYER M4 ;
        RECT  220.236 33.936 220.32 33.96 ;
    END
  END residual_data[48]
  PIN residual_data[49]
    DIRECTION OUTPUT ;
    USE SIGNAL ;
    PORT
      LAYER M4 ;
        RECT  220.236 34.032 220.32 34.056 ;
    END
  END residual_data[49]
  PIN residual_data[4]
    DIRECTION OUTPUT ;
    USE SIGNAL ;
    PORT
      LAYER M4 ;
        RECT  220.236 29.712 220.32 29.736 ;
    END
  END residual_data[4]
  PIN residual_data[50]
    DIRECTION OUTPUT ;
    USE SIGNAL ;
    PORT
      LAYER M4 ;
        RECT  220.236 34.128 220.32 34.152 ;
    END
  END residual_data[50]
  PIN residual_data[51]
    DIRECTION OUTPUT ;
    USE SIGNAL ;
    PORT
      LAYER M4 ;
        RECT  220.236 34.224 220.32 34.248 ;
    END
  END residual_data[51]
  PIN residual_data[52]
    DIRECTION OUTPUT ;
    USE SIGNAL ;
    PORT
      LAYER M4 ;
        RECT  220.236 34.32 220.32 34.344 ;
    END
  END residual_data[52]
  PIN residual_data[53]
    DIRECTION OUTPUT ;
    USE SIGNAL ;
    PORT
      LAYER M4 ;
        RECT  220.236 34.416 220.32 34.44 ;
    END
  END residual_data[53]
  PIN residual_data[54]
    DIRECTION OUTPUT ;
    USE SIGNAL ;
    PORT
      LAYER M4 ;
        RECT  220.236 34.512 220.32 34.536 ;
    END
  END residual_data[54]
  PIN residual_data[55]
    DIRECTION OUTPUT ;
    USE SIGNAL ;
    PORT
      LAYER M4 ;
        RECT  220.236 34.608 220.32 34.632 ;
    END
  END residual_data[55]
  PIN residual_data[56]
    DIRECTION OUTPUT ;
    USE SIGNAL ;
    PORT
      LAYER M4 ;
        RECT  220.236 34.704 220.32 34.728 ;
    END
  END residual_data[56]
  PIN residual_data[57]
    DIRECTION OUTPUT ;
    USE SIGNAL ;
    PORT
      LAYER M4 ;
        RECT  220.236 34.8 220.32 34.824 ;
    END
  END residual_data[57]
  PIN residual_data[58]
    DIRECTION OUTPUT ;
    USE SIGNAL ;
    PORT
      LAYER M4 ;
        RECT  220.236 34.896 220.32 34.92 ;
    END
  END residual_data[58]
  PIN residual_data[59]
    DIRECTION OUTPUT ;
    USE SIGNAL ;
    PORT
      LAYER M4 ;
        RECT  220.236 34.992 220.32 35.016 ;
    END
  END residual_data[59]
  PIN residual_data[5]
    DIRECTION OUTPUT ;
    USE SIGNAL ;
    PORT
      LAYER M4 ;
        RECT  220.236 29.808 220.32 29.832 ;
    END
  END residual_data[5]
  PIN residual_data[60]
    DIRECTION OUTPUT ;
    USE SIGNAL ;
    PORT
      LAYER M4 ;
        RECT  220.236 35.088 220.32 35.112 ;
    END
  END residual_data[60]
  PIN residual_data[61]
    DIRECTION OUTPUT ;
    USE SIGNAL ;
    PORT
      LAYER M4 ;
        RECT  220.236 35.184 220.32 35.208 ;
    END
  END residual_data[61]
  PIN residual_data[62]
    DIRECTION OUTPUT ;
    USE SIGNAL ;
    PORT
      LAYER M4 ;
        RECT  220.236 35.28 220.32 35.304 ;
    END
  END residual_data[62]
  PIN residual_data[63]
    DIRECTION OUTPUT ;
    USE SIGNAL ;
    PORT
      LAYER M4 ;
        RECT  220.236 35.376 220.32 35.4 ;
    END
  END residual_data[63]
  PIN residual_data[64]
    DIRECTION OUTPUT ;
    USE SIGNAL ;
    PORT
      LAYER M4 ;
        RECT  220.236 35.472 220.32 35.496 ;
    END
  END residual_data[64]
  PIN residual_data[65]
    DIRECTION OUTPUT ;
    USE SIGNAL ;
    PORT
      LAYER M4 ;
        RECT  220.236 35.568 220.32 35.592 ;
    END
  END residual_data[65]
  PIN residual_data[66]
    DIRECTION OUTPUT ;
    USE SIGNAL ;
    PORT
      LAYER M4 ;
        RECT  220.236 35.664 220.32 35.688 ;
    END
  END residual_data[66]
  PIN residual_data[67]
    DIRECTION OUTPUT ;
    USE SIGNAL ;
    PORT
      LAYER M4 ;
        RECT  220.236 35.76 220.32 35.784 ;
    END
  END residual_data[67]
  PIN residual_data[68]
    DIRECTION OUTPUT ;
    USE SIGNAL ;
    PORT
      LAYER M4 ;
        RECT  220.236 35.856 220.32 35.88 ;
    END
  END residual_data[68]
  PIN residual_data[69]
    DIRECTION OUTPUT ;
    USE SIGNAL ;
    PORT
      LAYER M4 ;
        RECT  220.236 35.952 220.32 35.976 ;
    END
  END residual_data[69]
  PIN residual_data[6]
    DIRECTION OUTPUT ;
    USE SIGNAL ;
    PORT
      LAYER M4 ;
        RECT  220.236 29.904 220.32 29.928 ;
    END
  END residual_data[6]
  PIN residual_data[70]
    DIRECTION OUTPUT ;
    USE SIGNAL ;
    PORT
      LAYER M4 ;
        RECT  220.236 36.048 220.32 36.072 ;
    END
  END residual_data[70]
  PIN residual_data[71]
    DIRECTION OUTPUT ;
    USE SIGNAL ;
    PORT
      LAYER M4 ;
        RECT  220.236 36.144 220.32 36.168 ;
    END
  END residual_data[71]
  PIN residual_data[72]
    DIRECTION OUTPUT ;
    USE SIGNAL ;
    PORT
      LAYER M4 ;
        RECT  220.236 36.24 220.32 36.264 ;
    END
  END residual_data[72]
  PIN residual_data[73]
    DIRECTION OUTPUT ;
    USE SIGNAL ;
    PORT
      LAYER M4 ;
        RECT  220.236 36.336 220.32 36.36 ;
    END
  END residual_data[73]
  PIN residual_data[74]
    DIRECTION OUTPUT ;
    USE SIGNAL ;
    PORT
      LAYER M4 ;
        RECT  220.236 36.432 220.32 36.456 ;
    END
  END residual_data[74]
  PIN residual_data[75]
    DIRECTION OUTPUT ;
    USE SIGNAL ;
    PORT
      LAYER M4 ;
        RECT  220.236 36.528 220.32 36.552 ;
    END
  END residual_data[75]
  PIN residual_data[76]
    DIRECTION OUTPUT ;
    USE SIGNAL ;
    PORT
      LAYER M4 ;
        RECT  220.236 36.624 220.32 36.648 ;
    END
  END residual_data[76]
  PIN residual_data[77]
    DIRECTION OUTPUT ;
    USE SIGNAL ;
    PORT
      LAYER M4 ;
        RECT  220.236 36.72 220.32 36.744 ;
    END
  END residual_data[77]
  PIN residual_data[78]
    DIRECTION OUTPUT ;
    USE SIGNAL ;
    PORT
      LAYER M4 ;
        RECT  220.236 36.816 220.32 36.84 ;
    END
  END residual_data[78]
  PIN residual_data[79]
    DIRECTION OUTPUT ;
    USE SIGNAL ;
    PORT
      LAYER M4 ;
        RECT  220.236 36.912 220.32 36.936 ;
    END
  END residual_data[79]
  PIN residual_data[7]
    DIRECTION OUTPUT ;
    USE SIGNAL ;
    PORT
      LAYER M4 ;
        RECT  220.236 30 220.32 30.024 ;
    END
  END residual_data[7]
  PIN residual_data[80]
    DIRECTION OUTPUT ;
    USE SIGNAL ;
    PORT
      LAYER M4 ;
        RECT  220.236 37.008 220.32 37.032 ;
    END
  END residual_data[80]
  PIN residual_data[81]
    DIRECTION OUTPUT ;
    USE SIGNAL ;
    PORT
      LAYER M4 ;
        RECT  220.236 37.104 220.32 37.128 ;
    END
  END residual_data[81]
  PIN residual_data[82]
    DIRECTION OUTPUT ;
    USE SIGNAL ;
    PORT
      LAYER M4 ;
        RECT  220.236 37.2 220.32 37.224 ;
    END
  END residual_data[82]
  PIN residual_data[83]
    DIRECTION OUTPUT ;
    USE SIGNAL ;
    PORT
      LAYER M4 ;
        RECT  220.236 37.296 220.32 37.32 ;
    END
  END residual_data[83]
  PIN residual_data[84]
    DIRECTION OUTPUT ;
    USE SIGNAL ;
    PORT
      LAYER M4 ;
        RECT  220.236 37.392 220.32 37.416 ;
    END
  END residual_data[84]
  PIN residual_data[85]
    DIRECTION OUTPUT ;
    USE SIGNAL ;
    PORT
      LAYER M4 ;
        RECT  220.236 37.488 220.32 37.512 ;
    END
  END residual_data[85]
  PIN residual_data[86]
    DIRECTION OUTPUT ;
    USE SIGNAL ;
    PORT
      LAYER M4 ;
        RECT  220.236 37.584 220.32 37.608 ;
    END
  END residual_data[86]
  PIN residual_data[87]
    DIRECTION OUTPUT ;
    USE SIGNAL ;
    PORT
      LAYER M4 ;
        RECT  220.236 37.68 220.32 37.704 ;
    END
  END residual_data[87]
  PIN residual_data[88]
    DIRECTION OUTPUT ;
    USE SIGNAL ;
    PORT
      LAYER M4 ;
        RECT  220.236 37.776 220.32 37.8 ;
    END
  END residual_data[88]
  PIN residual_data[89]
    DIRECTION OUTPUT ;
    USE SIGNAL ;
    PORT
      LAYER M4 ;
        RECT  220.236 37.872 220.32 37.896 ;
    END
  END residual_data[89]
  PIN residual_data[8]
    DIRECTION OUTPUT ;
    USE SIGNAL ;
    PORT
      LAYER M4 ;
        RECT  220.236 30.096 220.32 30.12 ;
    END
  END residual_data[8]
  PIN residual_data[90]
    DIRECTION OUTPUT ;
    USE SIGNAL ;
    PORT
      LAYER M4 ;
        RECT  220.236 37.968 220.32 37.992 ;
    END
  END residual_data[90]
  PIN residual_data[91]
    DIRECTION OUTPUT ;
    USE SIGNAL ;
    PORT
      LAYER M4 ;
        RECT  220.236 38.064 220.32 38.088 ;
    END
  END residual_data[91]
  PIN residual_data[92]
    DIRECTION OUTPUT ;
    USE SIGNAL ;
    PORT
      LAYER M4 ;
        RECT  220.236 38.16 220.32 38.184 ;
    END
  END residual_data[92]
  PIN residual_data[93]
    DIRECTION OUTPUT ;
    USE SIGNAL ;
    PORT
      LAYER M4 ;
        RECT  220.236 38.256 220.32 38.28 ;
    END
  END residual_data[93]
  PIN residual_data[94]
    DIRECTION OUTPUT ;
    USE SIGNAL ;
    PORT
      LAYER M4 ;
        RECT  220.236 39.12 220.32 39.144 ;
    END
  END residual_data[94]
  PIN residual_data[95]
    DIRECTION OUTPUT ;
    USE SIGNAL ;
    PORT
      LAYER M4 ;
        RECT  220.236 39.216 220.32 39.24 ;
    END
  END residual_data[95]
  PIN residual_data[96]
    DIRECTION OUTPUT ;
    USE SIGNAL ;
    PORT
      LAYER M4 ;
        RECT  220.236 39.312 220.32 39.336 ;
    END
  END residual_data[96]
  PIN residual_data[97]
    DIRECTION OUTPUT ;
    USE SIGNAL ;
    PORT
      LAYER M4 ;
        RECT  220.236 39.408 220.32 39.432 ;
    END
  END residual_data[97]
  PIN residual_data[98]
    DIRECTION OUTPUT ;
    USE SIGNAL ;
    PORT
      LAYER M4 ;
        RECT  220.236 39.504 220.32 39.528 ;
    END
  END residual_data[98]
  PIN residual_data[99]
    DIRECTION OUTPUT ;
    USE SIGNAL ;
    PORT
      LAYER M4 ;
        RECT  220.236 39.6 220.32 39.624 ;
    END
  END residual_data[99]
  PIN residual_data[9]
    DIRECTION OUTPUT ;
    USE SIGNAL ;
    PORT
      LAYER M4 ;
        RECT  220.236 30.192 220.32 30.216 ;
    END
  END residual_data[9]
  PIN rst_n
    DIRECTION INPUT ;
    USE SIGNAL ;
    PORT
      LAYER M5 ;
        RECT  200.304 125.196 200.328 125.28 ;
    END
  END rst_n
  PIN write_data[0]
    DIRECTION INPUT ;
    USE SIGNAL ;
    PORT
      LAYER M4 ;
        RECT  0 54.672 0.084 54.696 ;
    END
  END write_data[0]
  PIN write_data[100]
    DIRECTION INPUT ;
    USE SIGNAL ;
    PORT
      LAYER M4 ;
        RECT  0 64.272 0.084 64.296 ;
    END
  END write_data[100]
  PIN write_data[101]
    DIRECTION INPUT ;
    USE SIGNAL ;
    PORT
      LAYER M4 ;
        RECT  0 64.368 0.084 64.392 ;
    END
  END write_data[101]
  PIN write_data[102]
    DIRECTION INPUT ;
    USE SIGNAL ;
    PORT
      LAYER M4 ;
        RECT  0 64.464 0.084 64.488 ;
    END
  END write_data[102]
  PIN write_data[103]
    DIRECTION INPUT ;
    USE SIGNAL ;
    PORT
      LAYER M4 ;
        RECT  0 64.56 0.084 64.584 ;
    END
  END write_data[103]
  PIN write_data[104]
    DIRECTION INPUT ;
    USE SIGNAL ;
    PORT
      LAYER M4 ;
        RECT  0 64.656 0.084 64.68 ;
    END
  END write_data[104]
  PIN write_data[105]
    DIRECTION INPUT ;
    USE SIGNAL ;
    PORT
      LAYER M4 ;
        RECT  0 64.752 0.084 64.776 ;
    END
  END write_data[105]
  PIN write_data[106]
    DIRECTION INPUT ;
    USE SIGNAL ;
    PORT
      LAYER M4 ;
        RECT  0 64.848 0.084 64.872 ;
    END
  END write_data[106]
  PIN write_data[107]
    DIRECTION INPUT ;
    USE SIGNAL ;
    PORT
      LAYER M4 ;
        RECT  0 64.944 0.084 64.968 ;
    END
  END write_data[107]
  PIN write_data[108]
    DIRECTION INPUT ;
    USE SIGNAL ;
    PORT
      LAYER M4 ;
        RECT  0 65.04 0.084 65.064 ;
    END
  END write_data[108]
  PIN write_data[109]
    DIRECTION INPUT ;
    USE SIGNAL ;
    PORT
      LAYER M4 ;
        RECT  0 65.136 0.084 65.16 ;
    END
  END write_data[109]
  PIN write_data[10]
    DIRECTION INPUT ;
    USE SIGNAL ;
    PORT
      LAYER M4 ;
        RECT  0 55.632 0.084 55.656 ;
    END
  END write_data[10]
  PIN write_data[110]
    DIRECTION INPUT ;
    USE SIGNAL ;
    PORT
      LAYER M4 ;
        RECT  0 65.232 0.084 65.256 ;
    END
  END write_data[110]
  PIN write_data[111]
    DIRECTION INPUT ;
    USE SIGNAL ;
    PORT
      LAYER M4 ;
        RECT  0 65.328 0.084 65.352 ;
    END
  END write_data[111]
  PIN write_data[112]
    DIRECTION INPUT ;
    USE SIGNAL ;
    PORT
      LAYER M4 ;
        RECT  0 65.424 0.084 65.448 ;
    END
  END write_data[112]
  PIN write_data[113]
    DIRECTION INPUT ;
    USE SIGNAL ;
    PORT
      LAYER M4 ;
        RECT  0 65.52 0.084 65.544 ;
    END
  END write_data[113]
  PIN write_data[114]
    DIRECTION INPUT ;
    USE SIGNAL ;
    PORT
      LAYER M4 ;
        RECT  0 65.616 0.084 65.64 ;
    END
  END write_data[114]
  PIN write_data[115]
    DIRECTION INPUT ;
    USE SIGNAL ;
    PORT
      LAYER M4 ;
        RECT  0 65.712 0.084 65.736 ;
    END
  END write_data[115]
  PIN write_data[116]
    DIRECTION INPUT ;
    USE SIGNAL ;
    PORT
      LAYER M4 ;
        RECT  0 65.808 0.084 65.832 ;
    END
  END write_data[116]
  PIN write_data[117]
    DIRECTION INPUT ;
    USE SIGNAL ;
    PORT
      LAYER M4 ;
        RECT  0 65.904 0.084 65.928 ;
    END
  END write_data[117]
  PIN write_data[118]
    DIRECTION INPUT ;
    USE SIGNAL ;
    PORT
      LAYER M4 ;
        RECT  0 66 0.084 66.024 ;
    END
  END write_data[118]
  PIN write_data[119]
    DIRECTION INPUT ;
    USE SIGNAL ;
    PORT
      LAYER M4 ;
        RECT  0 66.096 0.084 66.12 ;
    END
  END write_data[119]
  PIN write_data[11]
    DIRECTION INPUT ;
    USE SIGNAL ;
    PORT
      LAYER M4 ;
        RECT  0 55.728 0.084 55.752 ;
    END
  END write_data[11]
  PIN write_data[120]
    DIRECTION INPUT ;
    USE SIGNAL ;
    PORT
      LAYER M4 ;
        RECT  0 66.192 0.084 66.216 ;
    END
  END write_data[120]
  PIN write_data[121]
    DIRECTION INPUT ;
    USE SIGNAL ;
    PORT
      LAYER M4 ;
        RECT  0 66.288 0.084 66.312 ;
    END
  END write_data[121]
  PIN write_data[122]
    DIRECTION INPUT ;
    USE SIGNAL ;
    PORT
      LAYER M4 ;
        RECT  0 66.384 0.084 66.408 ;
    END
  END write_data[122]
  PIN write_data[123]
    DIRECTION INPUT ;
    USE SIGNAL ;
    PORT
      LAYER M4 ;
        RECT  0 66.48 0.084 66.504 ;
    END
  END write_data[123]
  PIN write_data[124]
    DIRECTION INPUT ;
    USE SIGNAL ;
    PORT
      LAYER M4 ;
        RECT  0 66.576 0.084 66.6 ;
    END
  END write_data[124]
  PIN write_data[125]
    DIRECTION INPUT ;
    USE SIGNAL ;
    PORT
      LAYER M4 ;
        RECT  0 66.672 0.084 66.696 ;
    END
  END write_data[125]
  PIN write_data[126]
    DIRECTION INPUT ;
    USE SIGNAL ;
    PORT
      LAYER M4 ;
        RECT  0 66.768 0.084 66.792 ;
    END
  END write_data[126]
  PIN write_data[127]
    DIRECTION INPUT ;
    USE SIGNAL ;
    PORT
      LAYER M4 ;
        RECT  0 66.864 0.084 66.888 ;
    END
  END write_data[127]
  PIN write_data[128]
    DIRECTION INPUT ;
    USE SIGNAL ;
    PORT
      LAYER M4 ;
        RECT  0 35.472 0.084 35.496 ;
    END
  END write_data[128]
  PIN write_data[129]
    DIRECTION INPUT ;
    USE SIGNAL ;
    PORT
      LAYER M4 ;
        RECT  0 35.568 0.084 35.592 ;
    END
  END write_data[129]
  PIN write_data[12]
    DIRECTION INPUT ;
    USE SIGNAL ;
    PORT
      LAYER M4 ;
        RECT  0 55.824 0.084 55.848 ;
    END
  END write_data[12]
  PIN write_data[130]
    DIRECTION INPUT ;
    USE SIGNAL ;
    PORT
      LAYER M4 ;
        RECT  0 35.664 0.084 35.688 ;
    END
  END write_data[130]
  PIN write_data[131]
    DIRECTION INPUT ;
    USE SIGNAL ;
    PORT
      LAYER M4 ;
        RECT  0 35.76 0.084 35.784 ;
    END
  END write_data[131]
  PIN write_data[132]
    DIRECTION INPUT ;
    USE SIGNAL ;
    PORT
      LAYER M4 ;
        RECT  0 35.856 0.084 35.88 ;
    END
  END write_data[132]
  PIN write_data[133]
    DIRECTION INPUT ;
    USE SIGNAL ;
    PORT
      LAYER M4 ;
        RECT  0 35.952 0.084 35.976 ;
    END
  END write_data[133]
  PIN write_data[134]
    DIRECTION INPUT ;
    USE SIGNAL ;
    PORT
      LAYER M4 ;
        RECT  0 36.048 0.084 36.072 ;
    END
  END write_data[134]
  PIN write_data[135]
    DIRECTION INPUT ;
    USE SIGNAL ;
    PORT
      LAYER M4 ;
        RECT  0 36.144 0.084 36.168 ;
    END
  END write_data[135]
  PIN write_data[136]
    DIRECTION INPUT ;
    USE SIGNAL ;
    PORT
      LAYER M4 ;
        RECT  0 36.24 0.084 36.264 ;
    END
  END write_data[136]
  PIN write_data[137]
    DIRECTION INPUT ;
    USE SIGNAL ;
    PORT
      LAYER M4 ;
        RECT  0 36.336 0.084 36.36 ;
    END
  END write_data[137]
  PIN write_data[138]
    DIRECTION INPUT ;
    USE SIGNAL ;
    PORT
      LAYER M4 ;
        RECT  0 36.432 0.084 36.456 ;
    END
  END write_data[138]
  PIN write_data[139]
    DIRECTION INPUT ;
    USE SIGNAL ;
    PORT
      LAYER M4 ;
        RECT  0 36.528 0.084 36.552 ;
    END
  END write_data[139]
  PIN write_data[13]
    DIRECTION INPUT ;
    USE SIGNAL ;
    PORT
      LAYER M4 ;
        RECT  0 55.92 0.084 55.944 ;
    END
  END write_data[13]
  PIN write_data[140]
    DIRECTION INPUT ;
    USE SIGNAL ;
    PORT
      LAYER M4 ;
        RECT  0 36.624 0.084 36.648 ;
    END
  END write_data[140]
  PIN write_data[141]
    DIRECTION INPUT ;
    USE SIGNAL ;
    PORT
      LAYER M4 ;
        RECT  0 36.72 0.084 36.744 ;
    END
  END write_data[141]
  PIN write_data[142]
    DIRECTION INPUT ;
    USE SIGNAL ;
    PORT
      LAYER M4 ;
        RECT  0 36.816 0.084 36.84 ;
    END
  END write_data[142]
  PIN write_data[143]
    DIRECTION INPUT ;
    USE SIGNAL ;
    PORT
      LAYER M4 ;
        RECT  0 36.912 0.084 36.936 ;
    END
  END write_data[143]
  PIN write_data[144]
    DIRECTION INPUT ;
    USE SIGNAL ;
    PORT
      LAYER M4 ;
        RECT  0 37.008 0.084 37.032 ;
    END
  END write_data[144]
  PIN write_data[145]
    DIRECTION INPUT ;
    USE SIGNAL ;
    PORT
      LAYER M4 ;
        RECT  0 37.104 0.084 37.128 ;
    END
  END write_data[145]
  PIN write_data[146]
    DIRECTION INPUT ;
    USE SIGNAL ;
    PORT
      LAYER M4 ;
        RECT  0 37.2 0.084 37.224 ;
    END
  END write_data[146]
  PIN write_data[147]
    DIRECTION INPUT ;
    USE SIGNAL ;
    PORT
      LAYER M4 ;
        RECT  0 37.296 0.084 37.32 ;
    END
  END write_data[147]
  PIN write_data[148]
    DIRECTION INPUT ;
    USE SIGNAL ;
    PORT
      LAYER M4 ;
        RECT  0 37.392 0.084 37.416 ;
    END
  END write_data[148]
  PIN write_data[149]
    DIRECTION INPUT ;
    USE SIGNAL ;
    PORT
      LAYER M4 ;
        RECT  0 37.488 0.084 37.512 ;
    END
  END write_data[149]
  PIN write_data[14]
    DIRECTION INPUT ;
    USE SIGNAL ;
    PORT
      LAYER M4 ;
        RECT  0 56.016 0.084 56.04 ;
    END
  END write_data[14]
  PIN write_data[150]
    DIRECTION INPUT ;
    USE SIGNAL ;
    PORT
      LAYER M4 ;
        RECT  0 37.584 0.084 37.608 ;
    END
  END write_data[150]
  PIN write_data[151]
    DIRECTION INPUT ;
    USE SIGNAL ;
    PORT
      LAYER M4 ;
        RECT  0 37.68 0.084 37.704 ;
    END
  END write_data[151]
  PIN write_data[152]
    DIRECTION INPUT ;
    USE SIGNAL ;
    PORT
      LAYER M4 ;
        RECT  0 37.776 0.084 37.8 ;
    END
  END write_data[152]
  PIN write_data[153]
    DIRECTION INPUT ;
    USE SIGNAL ;
    PORT
      LAYER M4 ;
        RECT  0 37.872 0.084 37.896 ;
    END
  END write_data[153]
  PIN write_data[154]
    DIRECTION INPUT ;
    USE SIGNAL ;
    PORT
      LAYER M4 ;
        RECT  0 37.968 0.084 37.992 ;
    END
  END write_data[154]
  PIN write_data[155]
    DIRECTION INPUT ;
    USE SIGNAL ;
    PORT
      LAYER M4 ;
        RECT  0 38.064 0.084 38.088 ;
    END
  END write_data[155]
  PIN write_data[156]
    DIRECTION INPUT ;
    USE SIGNAL ;
    PORT
      LAYER M4 ;
        RECT  0 38.16 0.084 38.184 ;
    END
  END write_data[156]
  PIN write_data[157]
    DIRECTION INPUT ;
    USE SIGNAL ;
    PORT
      LAYER M4 ;
        RECT  0 38.256 0.084 38.28 ;
    END
  END write_data[157]
  PIN write_data[158]
    DIRECTION INPUT ;
    USE SIGNAL ;
    PORT
      LAYER M4 ;
        RECT  0 38.352 0.084 38.376 ;
    END
  END write_data[158]
  PIN write_data[159]
    DIRECTION INPUT ;
    USE SIGNAL ;
    PORT
      LAYER M4 ;
        RECT  0 38.448 0.084 38.472 ;
    END
  END write_data[159]
  PIN write_data[15]
    DIRECTION INPUT ;
    USE SIGNAL ;
    PORT
      LAYER M4 ;
        RECT  0 56.112 0.084 56.136 ;
    END
  END write_data[15]
  PIN write_data[160]
    DIRECTION INPUT ;
    USE SIGNAL ;
    PORT
      LAYER M4 ;
        RECT  0 29.328 0.084 29.352 ;
    END
  END write_data[160]
  PIN write_data[161]
    DIRECTION INPUT ;
    USE SIGNAL ;
    PORT
      LAYER M4 ;
        RECT  0 29.424 0.084 29.448 ;
    END
  END write_data[161]
  PIN write_data[162]
    DIRECTION INPUT ;
    USE SIGNAL ;
    PORT
      LAYER M4 ;
        RECT  0 29.52 0.084 29.544 ;
    END
  END write_data[162]
  PIN write_data[163]
    DIRECTION INPUT ;
    USE SIGNAL ;
    PORT
      LAYER M4 ;
        RECT  0 29.616 0.084 29.64 ;
    END
  END write_data[163]
  PIN write_data[164]
    DIRECTION INPUT ;
    USE SIGNAL ;
    PORT
      LAYER M4 ;
        RECT  0 29.712 0.084 29.736 ;
    END
  END write_data[164]
  PIN write_data[165]
    DIRECTION INPUT ;
    USE SIGNAL ;
    PORT
      LAYER M4 ;
        RECT  0 29.808 0.084 29.832 ;
    END
  END write_data[165]
  PIN write_data[166]
    DIRECTION INPUT ;
    USE SIGNAL ;
    PORT
      LAYER M4 ;
        RECT  0 29.904 0.084 29.928 ;
    END
  END write_data[166]
  PIN write_data[167]
    DIRECTION INPUT ;
    USE SIGNAL ;
    PORT
      LAYER M4 ;
        RECT  0 30 0.084 30.024 ;
    END
  END write_data[167]
  PIN write_data[168]
    DIRECTION INPUT ;
    USE SIGNAL ;
    PORT
      LAYER M4 ;
        RECT  0 30.096 0.084 30.12 ;
    END
  END write_data[168]
  PIN write_data[169]
    DIRECTION INPUT ;
    USE SIGNAL ;
    PORT
      LAYER M4 ;
        RECT  0 30.192 0.084 30.216 ;
    END
  END write_data[169]
  PIN write_data[16]
    DIRECTION INPUT ;
    USE SIGNAL ;
    PORT
      LAYER M4 ;
        RECT  0 56.208 0.084 56.232 ;
    END
  END write_data[16]
  PIN write_data[170]
    DIRECTION INPUT ;
    USE SIGNAL ;
    PORT
      LAYER M4 ;
        RECT  0 30.288 0.084 30.312 ;
    END
  END write_data[170]
  PIN write_data[171]
    DIRECTION INPUT ;
    USE SIGNAL ;
    PORT
      LAYER M4 ;
        RECT  0 30.384 0.084 30.408 ;
    END
  END write_data[171]
  PIN write_data[172]
    DIRECTION INPUT ;
    USE SIGNAL ;
    PORT
      LAYER M4 ;
        RECT  0 30.48 0.084 30.504 ;
    END
  END write_data[172]
  PIN write_data[173]
    DIRECTION INPUT ;
    USE SIGNAL ;
    PORT
      LAYER M4 ;
        RECT  0 30.576 0.084 30.6 ;
    END
  END write_data[173]
  PIN write_data[174]
    DIRECTION INPUT ;
    USE SIGNAL ;
    PORT
      LAYER M4 ;
        RECT  0 30.672 0.084 30.696 ;
    END
  END write_data[174]
  PIN write_data[175]
    DIRECTION INPUT ;
    USE SIGNAL ;
    PORT
      LAYER M4 ;
        RECT  0 30.768 0.084 30.792 ;
    END
  END write_data[175]
  PIN write_data[176]
    DIRECTION INPUT ;
    USE SIGNAL ;
    PORT
      LAYER M4 ;
        RECT  0 30.864 0.084 30.888 ;
    END
  END write_data[176]
  PIN write_data[177]
    DIRECTION INPUT ;
    USE SIGNAL ;
    PORT
      LAYER M4 ;
        RECT  0 30.96 0.084 30.984 ;
    END
  END write_data[177]
  PIN write_data[178]
    DIRECTION INPUT ;
    USE SIGNAL ;
    PORT
      LAYER M4 ;
        RECT  0 31.056 0.084 31.08 ;
    END
  END write_data[178]
  PIN write_data[179]
    DIRECTION INPUT ;
    USE SIGNAL ;
    PORT
      LAYER M4 ;
        RECT  0 31.152 0.084 31.176 ;
    END
  END write_data[179]
  PIN write_data[17]
    DIRECTION INPUT ;
    USE SIGNAL ;
    PORT
      LAYER M4 ;
        RECT  0 56.304 0.084 56.328 ;
    END
  END write_data[17]
  PIN write_data[180]
    DIRECTION INPUT ;
    USE SIGNAL ;
    PORT
      LAYER M4 ;
        RECT  0 31.248 0.084 31.272 ;
    END
  END write_data[180]
  PIN write_data[181]
    DIRECTION INPUT ;
    USE SIGNAL ;
    PORT
      LAYER M4 ;
        RECT  0 31.344 0.084 31.368 ;
    END
  END write_data[181]
  PIN write_data[182]
    DIRECTION INPUT ;
    USE SIGNAL ;
    PORT
      LAYER M4 ;
        RECT  0 31.44 0.084 31.464 ;
    END
  END write_data[182]
  PIN write_data[183]
    DIRECTION INPUT ;
    USE SIGNAL ;
    PORT
      LAYER M4 ;
        RECT  0 31.536 0.084 31.56 ;
    END
  END write_data[183]
  PIN write_data[184]
    DIRECTION INPUT ;
    USE SIGNAL ;
    PORT
      LAYER M4 ;
        RECT  0 31.632 0.084 31.656 ;
    END
  END write_data[184]
  PIN write_data[185]
    DIRECTION INPUT ;
    USE SIGNAL ;
    PORT
      LAYER M4 ;
        RECT  0 31.728 0.084 31.752 ;
    END
  END write_data[185]
  PIN write_data[186]
    DIRECTION INPUT ;
    USE SIGNAL ;
    PORT
      LAYER M4 ;
        RECT  0 31.824 0.084 31.848 ;
    END
  END write_data[186]
  PIN write_data[187]
    DIRECTION INPUT ;
    USE SIGNAL ;
    PORT
      LAYER M4 ;
        RECT  0 31.92 0.084 31.944 ;
    END
  END write_data[187]
  PIN write_data[188]
    DIRECTION INPUT ;
    USE SIGNAL ;
    PORT
      LAYER M4 ;
        RECT  0 32.016 0.084 32.04 ;
    END
  END write_data[188]
  PIN write_data[189]
    DIRECTION INPUT ;
    USE SIGNAL ;
    PORT
      LAYER M4 ;
        RECT  0 32.112 0.084 32.136 ;
    END
  END write_data[189]
  PIN write_data[18]
    DIRECTION INPUT ;
    USE SIGNAL ;
    PORT
      LAYER M4 ;
        RECT  0 56.4 0.084 56.424 ;
    END
  END write_data[18]
  PIN write_data[190]
    DIRECTION INPUT ;
    USE SIGNAL ;
    PORT
      LAYER M4 ;
        RECT  0 32.208 0.084 32.232 ;
    END
  END write_data[190]
  PIN write_data[191]
    DIRECTION INPUT ;
    USE SIGNAL ;
    PORT
      LAYER M4 ;
        RECT  0 32.304 0.084 32.328 ;
    END
  END write_data[191]
  PIN write_data[192]
    DIRECTION INPUT ;
    USE SIGNAL ;
    PORT
      LAYER M4 ;
        RECT  0 32.4 0.084 32.424 ;
    END
  END write_data[192]
  PIN write_data[193]
    DIRECTION INPUT ;
    USE SIGNAL ;
    PORT
      LAYER M4 ;
        RECT  0 32.496 0.084 32.52 ;
    END
  END write_data[193]
  PIN write_data[194]
    DIRECTION INPUT ;
    USE SIGNAL ;
    PORT
      LAYER M4 ;
        RECT  0 32.592 0.084 32.616 ;
    END
  END write_data[194]
  PIN write_data[195]
    DIRECTION INPUT ;
    USE SIGNAL ;
    PORT
      LAYER M4 ;
        RECT  0 32.688 0.084 32.712 ;
    END
  END write_data[195]
  PIN write_data[196]
    DIRECTION INPUT ;
    USE SIGNAL ;
    PORT
      LAYER M4 ;
        RECT  0 32.784 0.084 32.808 ;
    END
  END write_data[196]
  PIN write_data[197]
    DIRECTION INPUT ;
    USE SIGNAL ;
    PORT
      LAYER M4 ;
        RECT  0 32.88 0.084 32.904 ;
    END
  END write_data[197]
  PIN write_data[198]
    DIRECTION INPUT ;
    USE SIGNAL ;
    PORT
      LAYER M4 ;
        RECT  0 32.976 0.084 33 ;
    END
  END write_data[198]
  PIN write_data[199]
    DIRECTION INPUT ;
    USE SIGNAL ;
    PORT
      LAYER M4 ;
        RECT  0 33.072 0.084 33.096 ;
    END
  END write_data[199]
  PIN write_data[19]
    DIRECTION INPUT ;
    USE SIGNAL ;
    PORT
      LAYER M4 ;
        RECT  0 56.496 0.084 56.52 ;
    END
  END write_data[19]
  PIN write_data[1]
    DIRECTION INPUT ;
    USE SIGNAL ;
    PORT
      LAYER M4 ;
        RECT  0 54.768 0.084 54.792 ;
    END
  END write_data[1]
  PIN write_data[200]
    DIRECTION INPUT ;
    USE SIGNAL ;
    PORT
      LAYER M4 ;
        RECT  0 33.168 0.084 33.192 ;
    END
  END write_data[200]
  PIN write_data[201]
    DIRECTION INPUT ;
    USE SIGNAL ;
    PORT
      LAYER M4 ;
        RECT  0 33.264 0.084 33.288 ;
    END
  END write_data[201]
  PIN write_data[202]
    DIRECTION INPUT ;
    USE SIGNAL ;
    PORT
      LAYER M4 ;
        RECT  0 33.36 0.084 33.384 ;
    END
  END write_data[202]
  PIN write_data[203]
    DIRECTION INPUT ;
    USE SIGNAL ;
    PORT
      LAYER M4 ;
        RECT  0 33.456 0.084 33.48 ;
    END
  END write_data[203]
  PIN write_data[204]
    DIRECTION INPUT ;
    USE SIGNAL ;
    PORT
      LAYER M4 ;
        RECT  0 33.552 0.084 33.576 ;
    END
  END write_data[204]
  PIN write_data[205]
    DIRECTION INPUT ;
    USE SIGNAL ;
    PORT
      LAYER M4 ;
        RECT  0 33.648 0.084 33.672 ;
    END
  END write_data[205]
  PIN write_data[206]
    DIRECTION INPUT ;
    USE SIGNAL ;
    PORT
      LAYER M4 ;
        RECT  0 33.744 0.084 33.768 ;
    END
  END write_data[206]
  PIN write_data[207]
    DIRECTION INPUT ;
    USE SIGNAL ;
    PORT
      LAYER M4 ;
        RECT  0 33.84 0.084 33.864 ;
    END
  END write_data[207]
  PIN write_data[208]
    DIRECTION INPUT ;
    USE SIGNAL ;
    PORT
      LAYER M4 ;
        RECT  0 33.936 0.084 33.96 ;
    END
  END write_data[208]
  PIN write_data[209]
    DIRECTION INPUT ;
    USE SIGNAL ;
    PORT
      LAYER M4 ;
        RECT  0 34.032 0.084 34.056 ;
    END
  END write_data[209]
  PIN write_data[20]
    DIRECTION INPUT ;
    USE SIGNAL ;
    PORT
      LAYER M4 ;
        RECT  0 56.592 0.084 56.616 ;
    END
  END write_data[20]
  PIN write_data[210]
    DIRECTION INPUT ;
    USE SIGNAL ;
    PORT
      LAYER M4 ;
        RECT  0 34.128 0.084 34.152 ;
    END
  END write_data[210]
  PIN write_data[211]
    DIRECTION INPUT ;
    USE SIGNAL ;
    PORT
      LAYER M4 ;
        RECT  0 34.224 0.084 34.248 ;
    END
  END write_data[211]
  PIN write_data[212]
    DIRECTION INPUT ;
    USE SIGNAL ;
    PORT
      LAYER M4 ;
        RECT  0 34.32 0.084 34.344 ;
    END
  END write_data[212]
  PIN write_data[213]
    DIRECTION INPUT ;
    USE SIGNAL ;
    PORT
      LAYER M4 ;
        RECT  0 34.416 0.084 34.44 ;
    END
  END write_data[213]
  PIN write_data[214]
    DIRECTION INPUT ;
    USE SIGNAL ;
    PORT
      LAYER M4 ;
        RECT  0 34.512 0.084 34.536 ;
    END
  END write_data[214]
  PIN write_data[215]
    DIRECTION INPUT ;
    USE SIGNAL ;
    PORT
      LAYER M4 ;
        RECT  0 34.608 0.084 34.632 ;
    END
  END write_data[215]
  PIN write_data[216]
    DIRECTION INPUT ;
    USE SIGNAL ;
    PORT
      LAYER M4 ;
        RECT  0 34.704 0.084 34.728 ;
    END
  END write_data[216]
  PIN write_data[217]
    DIRECTION INPUT ;
    USE SIGNAL ;
    PORT
      LAYER M4 ;
        RECT  0 34.8 0.084 34.824 ;
    END
  END write_data[217]
  PIN write_data[218]
    DIRECTION INPUT ;
    USE SIGNAL ;
    PORT
      LAYER M4 ;
        RECT  0 34.896 0.084 34.92 ;
    END
  END write_data[218]
  PIN write_data[219]
    DIRECTION INPUT ;
    USE SIGNAL ;
    PORT
      LAYER M4 ;
        RECT  0 34.992 0.084 35.016 ;
    END
  END write_data[219]
  PIN write_data[21]
    DIRECTION INPUT ;
    USE SIGNAL ;
    PORT
      LAYER M4 ;
        RECT  0 56.688 0.084 56.712 ;
    END
  END write_data[21]
  PIN write_data[220]
    DIRECTION INPUT ;
    USE SIGNAL ;
    PORT
      LAYER M4 ;
        RECT  0 35.088 0.084 35.112 ;
    END
  END write_data[220]
  PIN write_data[221]
    DIRECTION INPUT ;
    USE SIGNAL ;
    PORT
      LAYER M4 ;
        RECT  0 35.184 0.084 35.208 ;
    END
  END write_data[221]
  PIN write_data[222]
    DIRECTION INPUT ;
    USE SIGNAL ;
    PORT
      LAYER M4 ;
        RECT  0 35.28 0.084 35.304 ;
    END
  END write_data[222]
  PIN write_data[223]
    DIRECTION INPUT ;
    USE SIGNAL ;
    PORT
      LAYER M4 ;
        RECT  0 35.376 0.084 35.4 ;
    END
  END write_data[223]
  PIN write_data[224]
    DIRECTION INPUT ;
    USE SIGNAL ;
    PORT
      LAYER M4 ;
        RECT  0 38.544 0.084 38.568 ;
    END
  END write_data[224]
  PIN write_data[225]
    DIRECTION INPUT ;
    USE SIGNAL ;
    PORT
      LAYER M4 ;
        RECT  0 38.64 0.084 38.664 ;
    END
  END write_data[225]
  PIN write_data[226]
    DIRECTION INPUT ;
    USE SIGNAL ;
    PORT
      LAYER M4 ;
        RECT  0 38.736 0.084 38.76 ;
    END
  END write_data[226]
  PIN write_data[227]
    DIRECTION INPUT ;
    USE SIGNAL ;
    PORT
      LAYER M4 ;
        RECT  0 38.832 0.084 38.856 ;
    END
  END write_data[227]
  PIN write_data[228]
    DIRECTION INPUT ;
    USE SIGNAL ;
    PORT
      LAYER M4 ;
        RECT  0 38.928 0.084 38.952 ;
    END
  END write_data[228]
  PIN write_data[229]
    DIRECTION INPUT ;
    USE SIGNAL ;
    PORT
      LAYER M4 ;
        RECT  0 39.024 0.084 39.048 ;
    END
  END write_data[229]
  PIN write_data[22]
    DIRECTION INPUT ;
    USE SIGNAL ;
    PORT
      LAYER M4 ;
        RECT  0 56.784 0.084 56.808 ;
    END
  END write_data[22]
  PIN write_data[230]
    DIRECTION INPUT ;
    USE SIGNAL ;
    PORT
      LAYER M4 ;
        RECT  0 39.12 0.084 39.144 ;
    END
  END write_data[230]
  PIN write_data[231]
    DIRECTION INPUT ;
    USE SIGNAL ;
    PORT
      LAYER M4 ;
        RECT  0 39.216 0.084 39.24 ;
    END
  END write_data[231]
  PIN write_data[232]
    DIRECTION INPUT ;
    USE SIGNAL ;
    PORT
      LAYER M4 ;
        RECT  0 39.312 0.084 39.336 ;
    END
  END write_data[232]
  PIN write_data[233]
    DIRECTION INPUT ;
    USE SIGNAL ;
    PORT
      LAYER M4 ;
        RECT  0 39.408 0.084 39.432 ;
    END
  END write_data[233]
  PIN write_data[234]
    DIRECTION INPUT ;
    USE SIGNAL ;
    PORT
      LAYER M4 ;
        RECT  0 39.504 0.084 39.528 ;
    END
  END write_data[234]
  PIN write_data[235]
    DIRECTION INPUT ;
    USE SIGNAL ;
    PORT
      LAYER M4 ;
        RECT  0 39.6 0.084 39.624 ;
    END
  END write_data[235]
  PIN write_data[236]
    DIRECTION INPUT ;
    USE SIGNAL ;
    PORT
      LAYER M4 ;
        RECT  0 39.696 0.084 39.72 ;
    END
  END write_data[236]
  PIN write_data[237]
    DIRECTION INPUT ;
    USE SIGNAL ;
    PORT
      LAYER M4 ;
        RECT  0 39.792 0.084 39.816 ;
    END
  END write_data[237]
  PIN write_data[238]
    DIRECTION INPUT ;
    USE SIGNAL ;
    PORT
      LAYER M4 ;
        RECT  0 39.888 0.084 39.912 ;
    END
  END write_data[238]
  PIN write_data[239]
    DIRECTION INPUT ;
    USE SIGNAL ;
    PORT
      LAYER M4 ;
        RECT  0 39.984 0.084 40.008 ;
    END
  END write_data[239]
  PIN write_data[23]
    DIRECTION INPUT ;
    USE SIGNAL ;
    PORT
      LAYER M4 ;
        RECT  0 56.88 0.084 56.904 ;
    END
  END write_data[23]
  PIN write_data[240]
    DIRECTION INPUT ;
    USE SIGNAL ;
    PORT
      LAYER M4 ;
        RECT  0 40.08 0.084 40.104 ;
    END
  END write_data[240]
  PIN write_data[241]
    DIRECTION INPUT ;
    USE SIGNAL ;
    PORT
      LAYER M4 ;
        RECT  0 40.176 0.084 40.2 ;
    END
  END write_data[241]
  PIN write_data[242]
    DIRECTION INPUT ;
    USE SIGNAL ;
    PORT
      LAYER M4 ;
        RECT  0 40.272 0.084 40.296 ;
    END
  END write_data[242]
  PIN write_data[243]
    DIRECTION INPUT ;
    USE SIGNAL ;
    PORT
      LAYER M4 ;
        RECT  0 40.368 0.084 40.392 ;
    END
  END write_data[243]
  PIN write_data[244]
    DIRECTION INPUT ;
    USE SIGNAL ;
    PORT
      LAYER M4 ;
        RECT  0 40.464 0.084 40.488 ;
    END
  END write_data[244]
  PIN write_data[245]
    DIRECTION INPUT ;
    USE SIGNAL ;
    PORT
      LAYER M4 ;
        RECT  0 40.56 0.084 40.584 ;
    END
  END write_data[245]
  PIN write_data[246]
    DIRECTION INPUT ;
    USE SIGNAL ;
    PORT
      LAYER M4 ;
        RECT  0 40.656 0.084 40.68 ;
    END
  END write_data[246]
  PIN write_data[247]
    DIRECTION INPUT ;
    USE SIGNAL ;
    PORT
      LAYER M4 ;
        RECT  0 40.752 0.084 40.776 ;
    END
  END write_data[247]
  PIN write_data[248]
    DIRECTION INPUT ;
    USE SIGNAL ;
    PORT
      LAYER M4 ;
        RECT  0 40.848 0.084 40.872 ;
    END
  END write_data[248]
  PIN write_data[249]
    DIRECTION INPUT ;
    USE SIGNAL ;
    PORT
      LAYER M4 ;
        RECT  0 40.944 0.084 40.968 ;
    END
  END write_data[249]
  PIN write_data[24]
    DIRECTION INPUT ;
    USE SIGNAL ;
    PORT
      LAYER M4 ;
        RECT  0 56.976 0.084 57 ;
    END
  END write_data[24]
  PIN write_data[250]
    DIRECTION INPUT ;
    USE SIGNAL ;
    PORT
      LAYER M4 ;
        RECT  0 41.04 0.084 41.064 ;
    END
  END write_data[250]
  PIN write_data[251]
    DIRECTION INPUT ;
    USE SIGNAL ;
    PORT
      LAYER M4 ;
        RECT  0 41.136 0.084 41.16 ;
    END
  END write_data[251]
  PIN write_data[252]
    DIRECTION INPUT ;
    USE SIGNAL ;
    PORT
      LAYER M4 ;
        RECT  0 41.232 0.084 41.256 ;
    END
  END write_data[252]
  PIN write_data[253]
    DIRECTION INPUT ;
    USE SIGNAL ;
    PORT
      LAYER M4 ;
        RECT  0 41.328 0.084 41.352 ;
    END
  END write_data[253]
  PIN write_data[254]
    DIRECTION INPUT ;
    USE SIGNAL ;
    PORT
      LAYER M4 ;
        RECT  0 41.424 0.084 41.448 ;
    END
  END write_data[254]
  PIN write_data[255]
    DIRECTION INPUT ;
    USE SIGNAL ;
    PORT
      LAYER M4 ;
        RECT  0 41.52 0.084 41.544 ;
    END
  END write_data[255]
  PIN write_data[25]
    DIRECTION INPUT ;
    USE SIGNAL ;
    PORT
      LAYER M4 ;
        RECT  0 57.072 0.084 57.096 ;
    END
  END write_data[25]
  PIN write_data[26]
    DIRECTION INPUT ;
    USE SIGNAL ;
    PORT
      LAYER M4 ;
        RECT  0 57.168 0.084 57.192 ;
    END
  END write_data[26]
  PIN write_data[27]
    DIRECTION INPUT ;
    USE SIGNAL ;
    PORT
      LAYER M4 ;
        RECT  0 57.264 0.084 57.288 ;
    END
  END write_data[27]
  PIN write_data[28]
    DIRECTION INPUT ;
    USE SIGNAL ;
    PORT
      LAYER M4 ;
        RECT  0 57.36 0.084 57.384 ;
    END
  END write_data[28]
  PIN write_data[29]
    DIRECTION INPUT ;
    USE SIGNAL ;
    PORT
      LAYER M4 ;
        RECT  0 57.456 0.084 57.48 ;
    END
  END write_data[29]
  PIN write_data[2]
    DIRECTION INPUT ;
    USE SIGNAL ;
    PORT
      LAYER M4 ;
        RECT  0 54.864 0.084 54.888 ;
    END
  END write_data[2]
  PIN write_data[30]
    DIRECTION INPUT ;
    USE SIGNAL ;
    PORT
      LAYER M4 ;
        RECT  0 57.552 0.084 57.576 ;
    END
  END write_data[30]
  PIN write_data[31]
    DIRECTION INPUT ;
    USE SIGNAL ;
    PORT
      LAYER M4 ;
        RECT  0 57.648 0.084 57.672 ;
    END
  END write_data[31]
  PIN write_data[32]
    DIRECTION INPUT ;
    USE SIGNAL ;
    PORT
      LAYER M4 ;
        RECT  0 57.744 0.084 57.768 ;
    END
  END write_data[32]
  PIN write_data[33]
    DIRECTION INPUT ;
    USE SIGNAL ;
    PORT
      LAYER M4 ;
        RECT  0 57.84 0.084 57.864 ;
    END
  END write_data[33]
  PIN write_data[34]
    DIRECTION INPUT ;
    USE SIGNAL ;
    PORT
      LAYER M4 ;
        RECT  0 57.936 0.084 57.96 ;
    END
  END write_data[34]
  PIN write_data[35]
    DIRECTION INPUT ;
    USE SIGNAL ;
    PORT
      LAYER M4 ;
        RECT  0 58.032 0.084 58.056 ;
    END
  END write_data[35]
  PIN write_data[36]
    DIRECTION INPUT ;
    USE SIGNAL ;
    PORT
      LAYER M4 ;
        RECT  0 58.128 0.084 58.152 ;
    END
  END write_data[36]
  PIN write_data[37]
    DIRECTION INPUT ;
    USE SIGNAL ;
    PORT
      LAYER M4 ;
        RECT  0 58.224 0.084 58.248 ;
    END
  END write_data[37]
  PIN write_data[38]
    DIRECTION INPUT ;
    USE SIGNAL ;
    PORT
      LAYER M4 ;
        RECT  0 58.32 0.084 58.344 ;
    END
  END write_data[38]
  PIN write_data[39]
    DIRECTION INPUT ;
    USE SIGNAL ;
    PORT
      LAYER M4 ;
        RECT  0 58.416 0.084 58.44 ;
    END
  END write_data[39]
  PIN write_data[3]
    DIRECTION INPUT ;
    USE SIGNAL ;
    PORT
      LAYER M4 ;
        RECT  0 54.96 0.084 54.984 ;
    END
  END write_data[3]
  PIN write_data[40]
    DIRECTION INPUT ;
    USE SIGNAL ;
    PORT
      LAYER M4 ;
        RECT  0 58.512 0.084 58.536 ;
    END
  END write_data[40]
  PIN write_data[41]
    DIRECTION INPUT ;
    USE SIGNAL ;
    PORT
      LAYER M4 ;
        RECT  0 58.608 0.084 58.632 ;
    END
  END write_data[41]
  PIN write_data[42]
    DIRECTION INPUT ;
    USE SIGNAL ;
    PORT
      LAYER M4 ;
        RECT  0 58.704 0.084 58.728 ;
    END
  END write_data[42]
  PIN write_data[43]
    DIRECTION INPUT ;
    USE SIGNAL ;
    PORT
      LAYER M4 ;
        RECT  0 58.8 0.084 58.824 ;
    END
  END write_data[43]
  PIN write_data[44]
    DIRECTION INPUT ;
    USE SIGNAL ;
    PORT
      LAYER M4 ;
        RECT  0 58.896 0.084 58.92 ;
    END
  END write_data[44]
  PIN write_data[45]
    DIRECTION INPUT ;
    USE SIGNAL ;
    PORT
      LAYER M4 ;
        RECT  0 58.992 0.084 59.016 ;
    END
  END write_data[45]
  PIN write_data[46]
    DIRECTION INPUT ;
    USE SIGNAL ;
    PORT
      LAYER M4 ;
        RECT  0 59.088 0.084 59.112 ;
    END
  END write_data[46]
  PIN write_data[47]
    DIRECTION INPUT ;
    USE SIGNAL ;
    PORT
      LAYER M4 ;
        RECT  0 59.184 0.084 59.208 ;
    END
  END write_data[47]
  PIN write_data[48]
    DIRECTION INPUT ;
    USE SIGNAL ;
    PORT
      LAYER M4 ;
        RECT  0 59.28 0.084 59.304 ;
    END
  END write_data[48]
  PIN write_data[49]
    DIRECTION INPUT ;
    USE SIGNAL ;
    PORT
      LAYER M4 ;
        RECT  0 59.376 0.084 59.4 ;
    END
  END write_data[49]
  PIN write_data[4]
    DIRECTION INPUT ;
    USE SIGNAL ;
    PORT
      LAYER M4 ;
        RECT  0 55.056 0.084 55.08 ;
    END
  END write_data[4]
  PIN write_data[50]
    DIRECTION INPUT ;
    USE SIGNAL ;
    PORT
      LAYER M4 ;
        RECT  0 59.472 0.084 59.496 ;
    END
  END write_data[50]
  PIN write_data[51]
    DIRECTION INPUT ;
    USE SIGNAL ;
    PORT
      LAYER M4 ;
        RECT  0 59.568 0.084 59.592 ;
    END
  END write_data[51]
  PIN write_data[52]
    DIRECTION INPUT ;
    USE SIGNAL ;
    PORT
      LAYER M4 ;
        RECT  0 59.664 0.084 59.688 ;
    END
  END write_data[52]
  PIN write_data[53]
    DIRECTION INPUT ;
    USE SIGNAL ;
    PORT
      LAYER M4 ;
        RECT  0 59.76 0.084 59.784 ;
    END
  END write_data[53]
  PIN write_data[54]
    DIRECTION INPUT ;
    USE SIGNAL ;
    PORT
      LAYER M4 ;
        RECT  0 59.856 0.084 59.88 ;
    END
  END write_data[54]
  PIN write_data[55]
    DIRECTION INPUT ;
    USE SIGNAL ;
    PORT
      LAYER M4 ;
        RECT  0 59.952 0.084 59.976 ;
    END
  END write_data[55]
  PIN write_data[56]
    DIRECTION INPUT ;
    USE SIGNAL ;
    PORT
      LAYER M4 ;
        RECT  0 60.048 0.084 60.072 ;
    END
  END write_data[56]
  PIN write_data[57]
    DIRECTION INPUT ;
    USE SIGNAL ;
    PORT
      LAYER M4 ;
        RECT  0 60.144 0.084 60.168 ;
    END
  END write_data[57]
  PIN write_data[58]
    DIRECTION INPUT ;
    USE SIGNAL ;
    PORT
      LAYER M4 ;
        RECT  0 60.24 0.084 60.264 ;
    END
  END write_data[58]
  PIN write_data[59]
    DIRECTION INPUT ;
    USE SIGNAL ;
    PORT
      LAYER M4 ;
        RECT  0 60.336 0.084 60.36 ;
    END
  END write_data[59]
  PIN write_data[5]
    DIRECTION INPUT ;
    USE SIGNAL ;
    PORT
      LAYER M4 ;
        RECT  0 55.152 0.084 55.176 ;
    END
  END write_data[5]
  PIN write_data[60]
    DIRECTION INPUT ;
    USE SIGNAL ;
    PORT
      LAYER M4 ;
        RECT  0 60.432 0.084 60.456 ;
    END
  END write_data[60]
  PIN write_data[61]
    DIRECTION INPUT ;
    USE SIGNAL ;
    PORT
      LAYER M4 ;
        RECT  0 60.528 0.084 60.552 ;
    END
  END write_data[61]
  PIN write_data[62]
    DIRECTION INPUT ;
    USE SIGNAL ;
    PORT
      LAYER M4 ;
        RECT  0 60.624 0.084 60.648 ;
    END
  END write_data[62]
  PIN write_data[63]
    DIRECTION INPUT ;
    USE SIGNAL ;
    PORT
      LAYER M4 ;
        RECT  0 60.72 0.084 60.744 ;
    END
  END write_data[63]
  PIN write_data[64]
    DIRECTION INPUT ;
    USE SIGNAL ;
    PORT
      LAYER M4 ;
        RECT  0 60.816 0.084 60.84 ;
    END
  END write_data[64]
  PIN write_data[65]
    DIRECTION INPUT ;
    USE SIGNAL ;
    PORT
      LAYER M4 ;
        RECT  0 60.912 0.084 60.936 ;
    END
  END write_data[65]
  PIN write_data[66]
    DIRECTION INPUT ;
    USE SIGNAL ;
    PORT
      LAYER M4 ;
        RECT  0 61.008 0.084 61.032 ;
    END
  END write_data[66]
  PIN write_data[67]
    DIRECTION INPUT ;
    USE SIGNAL ;
    PORT
      LAYER M4 ;
        RECT  0 61.104 0.084 61.128 ;
    END
  END write_data[67]
  PIN write_data[68]
    DIRECTION INPUT ;
    USE SIGNAL ;
    PORT
      LAYER M4 ;
        RECT  0 61.2 0.084 61.224 ;
    END
  END write_data[68]
  PIN write_data[69]
    DIRECTION INPUT ;
    USE SIGNAL ;
    PORT
      LAYER M4 ;
        RECT  0 61.296 0.084 61.32 ;
    END
  END write_data[69]
  PIN write_data[6]
    DIRECTION INPUT ;
    USE SIGNAL ;
    PORT
      LAYER M4 ;
        RECT  0 55.248 0.084 55.272 ;
    END
  END write_data[6]
  PIN write_data[70]
    DIRECTION INPUT ;
    USE SIGNAL ;
    PORT
      LAYER M4 ;
        RECT  0 61.392 0.084 61.416 ;
    END
  END write_data[70]
  PIN write_data[71]
    DIRECTION INPUT ;
    USE SIGNAL ;
    PORT
      LAYER M4 ;
        RECT  0 61.488 0.084 61.512 ;
    END
  END write_data[71]
  PIN write_data[72]
    DIRECTION INPUT ;
    USE SIGNAL ;
    PORT
      LAYER M4 ;
        RECT  0 61.584 0.084 61.608 ;
    END
  END write_data[72]
  PIN write_data[73]
    DIRECTION INPUT ;
    USE SIGNAL ;
    PORT
      LAYER M4 ;
        RECT  0 61.68 0.084 61.704 ;
    END
  END write_data[73]
  PIN write_data[74]
    DIRECTION INPUT ;
    USE SIGNAL ;
    PORT
      LAYER M4 ;
        RECT  0 61.776 0.084 61.8 ;
    END
  END write_data[74]
  PIN write_data[75]
    DIRECTION INPUT ;
    USE SIGNAL ;
    PORT
      LAYER M4 ;
        RECT  0 61.872 0.084 61.896 ;
    END
  END write_data[75]
  PIN write_data[76]
    DIRECTION INPUT ;
    USE SIGNAL ;
    PORT
      LAYER M4 ;
        RECT  0 61.968 0.084 61.992 ;
    END
  END write_data[76]
  PIN write_data[77]
    DIRECTION INPUT ;
    USE SIGNAL ;
    PORT
      LAYER M4 ;
        RECT  0 62.064 0.084 62.088 ;
    END
  END write_data[77]
  PIN write_data[78]
    DIRECTION INPUT ;
    USE SIGNAL ;
    PORT
      LAYER M4 ;
        RECT  0 62.16 0.084 62.184 ;
    END
  END write_data[78]
  PIN write_data[79]
    DIRECTION INPUT ;
    USE SIGNAL ;
    PORT
      LAYER M4 ;
        RECT  0 62.256 0.084 62.28 ;
    END
  END write_data[79]
  PIN write_data[7]
    DIRECTION INPUT ;
    USE SIGNAL ;
    PORT
      LAYER M4 ;
        RECT  0 55.344 0.084 55.368 ;
    END
  END write_data[7]
  PIN write_data[80]
    DIRECTION INPUT ;
    USE SIGNAL ;
    PORT
      LAYER M4 ;
        RECT  0 62.352 0.084 62.376 ;
    END
  END write_data[80]
  PIN write_data[81]
    DIRECTION INPUT ;
    USE SIGNAL ;
    PORT
      LAYER M4 ;
        RECT  0 62.448 0.084 62.472 ;
    END
  END write_data[81]
  PIN write_data[82]
    DIRECTION INPUT ;
    USE SIGNAL ;
    PORT
      LAYER M4 ;
        RECT  0 62.544 0.084 62.568 ;
    END
  END write_data[82]
  PIN write_data[83]
    DIRECTION INPUT ;
    USE SIGNAL ;
    PORT
      LAYER M4 ;
        RECT  0 62.64 0.084 62.664 ;
    END
  END write_data[83]
  PIN write_data[84]
    DIRECTION INPUT ;
    USE SIGNAL ;
    PORT
      LAYER M4 ;
        RECT  0 62.736 0.084 62.76 ;
    END
  END write_data[84]
  PIN write_data[85]
    DIRECTION INPUT ;
    USE SIGNAL ;
    PORT
      LAYER M4 ;
        RECT  0 62.832 0.084 62.856 ;
    END
  END write_data[85]
  PIN write_data[86]
    DIRECTION INPUT ;
    USE SIGNAL ;
    PORT
      LAYER M4 ;
        RECT  0 62.928 0.084 62.952 ;
    END
  END write_data[86]
  PIN write_data[87]
    DIRECTION INPUT ;
    USE SIGNAL ;
    PORT
      LAYER M4 ;
        RECT  0 63.024 0.084 63.048 ;
    END
  END write_data[87]
  PIN write_data[88]
    DIRECTION INPUT ;
    USE SIGNAL ;
    PORT
      LAYER M4 ;
        RECT  0 63.12 0.084 63.144 ;
    END
  END write_data[88]
  PIN write_data[89]
    DIRECTION INPUT ;
    USE SIGNAL ;
    PORT
      LAYER M4 ;
        RECT  0 63.216 0.084 63.24 ;
    END
  END write_data[89]
  PIN write_data[8]
    DIRECTION INPUT ;
    USE SIGNAL ;
    PORT
      LAYER M4 ;
        RECT  0 55.44 0.084 55.464 ;
    END
  END write_data[8]
  PIN write_data[90]
    DIRECTION INPUT ;
    USE SIGNAL ;
    PORT
      LAYER M4 ;
        RECT  0 63.312 0.084 63.336 ;
    END
  END write_data[90]
  PIN write_data[91]
    DIRECTION INPUT ;
    USE SIGNAL ;
    PORT
      LAYER M4 ;
        RECT  0 63.408 0.084 63.432 ;
    END
  END write_data[91]
  PIN write_data[92]
    DIRECTION INPUT ;
    USE SIGNAL ;
    PORT
      LAYER M4 ;
        RECT  0 63.504 0.084 63.528 ;
    END
  END write_data[92]
  PIN write_data[93]
    DIRECTION INPUT ;
    USE SIGNAL ;
    PORT
      LAYER M4 ;
        RECT  0 63.6 0.084 63.624 ;
    END
  END write_data[93]
  PIN write_data[94]
    DIRECTION INPUT ;
    USE SIGNAL ;
    PORT
      LAYER M4 ;
        RECT  0 63.696 0.084 63.72 ;
    END
  END write_data[94]
  PIN write_data[95]
    DIRECTION INPUT ;
    USE SIGNAL ;
    PORT
      LAYER M4 ;
        RECT  0 63.792 0.084 63.816 ;
    END
  END write_data[95]
  PIN write_data[96]
    DIRECTION INPUT ;
    USE SIGNAL ;
    PORT
      LAYER M4 ;
        RECT  0 63.888 0.084 63.912 ;
    END
  END write_data[96]
  PIN write_data[97]
    DIRECTION INPUT ;
    USE SIGNAL ;
    PORT
      LAYER M4 ;
        RECT  0 63.984 0.084 64.008 ;
    END
  END write_data[97]
  PIN write_data[98]
    DIRECTION INPUT ;
    USE SIGNAL ;
    PORT
      LAYER M4 ;
        RECT  0 64.08 0.084 64.104 ;
    END
  END write_data[98]
  PIN write_data[99]
    DIRECTION INPUT ;
    USE SIGNAL ;
    PORT
      LAYER M4 ;
        RECT  0 64.176 0.084 64.2 ;
    END
  END write_data[99]
  PIN write_data[9]
    DIRECTION INPUT ;
    USE SIGNAL ;
    PORT
      LAYER M4 ;
        RECT  0 55.536 0.084 55.56 ;
    END
  END write_data[9]
  PIN write_v
    DIRECTION INPUT ;
    USE SIGNAL ;
    PORT
      LAYER M4 ;
        RECT  0 43.632 0.084 43.656 ;
    END
  END write_v
  PIN write_word[0]
    DIRECTION INPUT ;
    USE SIGNAL ;
    PORT
      LAYER M4 ;
        RECT  0 43.728 0.084 43.752 ;
    END
  END write_word[0]
  PIN write_word[1]
    DIRECTION INPUT ;
    USE SIGNAL ;
    PORT
      LAYER M4 ;
        RECT  0 43.824 0.084 43.848 ;
    END
  END write_word[1]
  PIN write_word[2]
    DIRECTION INPUT ;
    USE SIGNAL ;
    PORT
      LAYER M4 ;
        RECT  0 43.92 0.084 43.944 ;
    END
  END write_word[2]
  PIN write_word[3]
    DIRECTION INPUT ;
    USE SIGNAL ;
    PORT
      LAYER M4 ;
        RECT  0 44.016 0.084 44.04 ;
    END
  END write_word[3]
  PIN write_word[4]
    DIRECTION INPUT ;
    USE SIGNAL ;
    PORT
      LAYER M4 ;
        RECT  0 44.112 0.084 44.136 ;
    END
  END write_word[4]
  PIN write_word[5]
    DIRECTION INPUT ;
    USE SIGNAL ;
    PORT
      LAYER M4 ;
        RECT  0 44.208 0.084 44.232 ;
    END
  END write_word[5]
  PIN write_word[6]
    DIRECTION INPUT ;
    USE SIGNAL ;
    PORT
      LAYER M4 ;
        RECT  0 44.304 0.084 44.328 ;
    END
  END write_word[6]
  PIN write_word[7]
    DIRECTION INPUT ;
    USE SIGNAL ;
    PORT
      LAYER M4 ;
        RECT  0 44.4 0.084 44.424 ;
    END
  END write_word[7]
  PIN write_word[8]
    DIRECTION INPUT ;
    USE SIGNAL ;
    PORT
      LAYER M4 ;
        RECT  0 44.496 0.084 44.52 ;
    END
  END write_word[8]
  PIN write_word[9]
    DIRECTION INPUT ;
    USE SIGNAL ;
    PORT
      LAYER M4 ;
        RECT  0 44.592 0.084 44.616 ;
    END
  END write_word[9]
  PIN VDD
    DIRECTION INOUT ;
    USE POWER ;
    PORT
      LAYER M5 ;
        RECT  213.192 2.151 213.312 123.129 ;
        RECT  207.792 2.151 207.912 123.129 ;
        RECT  202.392 2.151 202.512 123.129 ;
        RECT  196.992 2.151 197.112 123.129 ;
        RECT  191.592 2.151 191.712 123.129 ;
        RECT  186.192 2.151 186.312 123.129 ;
        RECT  180.792 2.151 180.912 123.129 ;
        RECT  175.392 2.151 175.512 123.129 ;
        RECT  169.992 2.151 170.112 123.129 ;
        RECT  164.592 2.151 164.712 123.129 ;
        RECT  159.192 2.151 159.312 123.129 ;
        RECT  153.792 2.151 153.912 123.129 ;
        RECT  148.392 2.151 148.512 123.129 ;
        RECT  142.992 2.151 143.112 123.129 ;
        RECT  137.592 2.151 137.712 123.129 ;
        RECT  132.192 2.151 132.312 123.129 ;
        RECT  126.792 2.151 126.912 123.129 ;
        RECT  121.392 2.151 121.512 123.129 ;
        RECT  115.992 2.151 116.112 123.129 ;
        RECT  110.592 2.151 110.712 123.129 ;
        RECT  105.192 2.151 105.312 123.129 ;
        RECT  99.792 2.151 99.912 123.129 ;
        RECT  94.392 2.151 94.512 123.129 ;
        RECT  88.992 2.151 89.112 123.129 ;
        RECT  83.592 2.151 83.712 123.129 ;
        RECT  78.192 2.151 78.312 123.129 ;
        RECT  72.792 2.151 72.912 123.129 ;
        RECT  67.392 2.151 67.512 123.129 ;
        RECT  61.992 2.151 62.112 123.129 ;
        RECT  56.592 2.151 56.712 123.129 ;
        RECT  51.192 2.151 51.312 123.129 ;
        RECT  45.792 2.151 45.912 123.129 ;
        RECT  40.392 2.151 40.512 123.129 ;
        RECT  34.992 2.151 35.112 123.129 ;
        RECT  29.592 2.151 29.712 123.129 ;
        RECT  24.192 2.151 24.312 123.129 ;
        RECT  18.792 2.151 18.912 123.129 ;
        RECT  13.392 2.151 13.512 123.129 ;
        RECT  7.992 2.151 8.112 123.129 ;
        RECT  2.592 2.151 2.712 123.129 ;
    END
  END VDD
  PIN VSS
    DIRECTION INOUT ;
    USE GROUND ;
    PORT
      LAYER M5 ;
        RECT  213 2.137 213.12 123.143 ;
        RECT  207.6 2.137 207.72 123.143 ;
        RECT  202.2 2.137 202.32 123.143 ;
        RECT  196.8 2.137 196.92 123.143 ;
        RECT  191.4 2.137 191.52 123.143 ;
        RECT  186 2.137 186.12 123.143 ;
        RECT  180.6 2.137 180.72 123.143 ;
        RECT  175.2 2.137 175.32 123.143 ;
        RECT  169.8 2.137 169.92 123.143 ;
        RECT  164.4 2.137 164.52 123.143 ;
        RECT  159 2.137 159.12 123.143 ;
        RECT  153.6 2.137 153.72 123.143 ;
        RECT  148.2 2.137 148.32 123.143 ;
        RECT  142.8 2.137 142.92 123.143 ;
        RECT  137.4 2.137 137.52 123.143 ;
        RECT  132 2.137 132.12 123.143 ;
        RECT  126.6 2.137 126.72 123.143 ;
        RECT  121.2 2.137 121.32 123.143 ;
        RECT  115.8 2.137 115.92 123.143 ;
        RECT  110.4 2.137 110.52 123.143 ;
        RECT  105 2.137 105.12 123.143 ;
        RECT  99.6 2.137 99.72 123.143 ;
        RECT  94.2 2.137 94.32 123.143 ;
        RECT  88.8 2.137 88.92 123.143 ;
        RECT  83.4 2.137 83.52 123.143 ;
        RECT  78 2.137 78.12 123.143 ;
        RECT  72.6 2.137 72.72 123.143 ;
        RECT  67.2 2.137 67.32 123.143 ;
        RECT  61.8 2.137 61.92 123.143 ;
        RECT  56.4 2.137 56.52 123.143 ;
        RECT  51 2.137 51.12 123.143 ;
        RECT  45.6 2.137 45.72 123.143 ;
        RECT  40.2 2.137 40.32 123.143 ;
        RECT  34.8 2.137 34.92 123.143 ;
        RECT  29.4 2.137 29.52 123.143 ;
        RECT  24 2.137 24.12 123.143 ;
        RECT  18.6 2.137 18.72 123.143 ;
        RECT  13.2 2.137 13.32 123.143 ;
        RECT  7.8 2.137 7.92 123.143 ;
        RECT  2.4 2.137 2.52 123.143 ;
    END
  END VSS
  OBS
    LAYER RVTN ;
     RECT  2.16 2.16 218.16 2.295 ;
     RECT  2.16 2.565 218.16 2.835 ;
     RECT  2.16 3.105 218.16 3.375 ;
     RECT  2.16 3.645 218.16 3.915 ;
     RECT  2.16 4.185 218.16 4.455 ;
     RECT  2.16 4.725 218.16 4.995 ;
     RECT  2.16 5.265 218.16 5.535 ;
     RECT  2.16 5.805 218.16 6.075 ;
     RECT  2.16 6.345 218.16 6.615 ;
     RECT  2.16 6.885 218.16 7.155 ;
     RECT  2.16 7.425 218.16 7.695 ;
     RECT  2.16 7.965 218.16 8.235 ;
     RECT  2.16 8.505 218.16 8.775 ;
     RECT  2.16 9.045 218.16 9.315 ;
     RECT  2.16 9.585 218.16 9.855 ;
     RECT  2.16 10.125 218.16 10.395 ;
     RECT  2.16 10.665 218.16 10.935 ;
     RECT  2.16 11.205 218.16 11.475 ;
     RECT  2.16 11.745 218.16 12.015 ;
     RECT  2.16 12.285 218.16 12.555 ;
     RECT  2.16 12.825 218.16 13.095 ;
     RECT  2.16 13.365 218.16 13.635 ;
     RECT  2.16 13.905 218.16 14.175 ;
     RECT  2.16 14.445 218.16 14.715 ;
     RECT  2.16 14.985 218.16 15.255 ;
     RECT  2.16 15.525 218.16 15.795 ;
     RECT  2.16 16.065 218.16 16.335 ;
     RECT  2.16 16.605 218.16 16.875 ;
     RECT  2.16 17.145 218.16 17.415 ;
     RECT  2.16 17.685 218.16 17.955 ;
     RECT  2.16 18.225 218.16 18.495 ;
     RECT  2.16 18.765 218.16 19.035 ;
     RECT  2.16 19.305 218.16 19.575 ;
     RECT  2.16 19.845 218.16 20.115 ;
     RECT  2.16 20.385 218.16 20.655 ;
     RECT  2.16 20.925 218.16 21.195 ;
     RECT  2.16 21.465 218.16 21.735 ;
     RECT  2.16 22.005 218.16 22.275 ;
     RECT  2.16 22.545 218.16 22.815 ;
     RECT  2.16 23.085 218.16 23.355 ;
     RECT  2.16 23.625 218.16 23.895 ;
     RECT  2.16 24.165 218.16 24.435 ;
     RECT  2.16 24.705 218.16 24.975 ;
     RECT  2.16 25.245 218.16 25.515 ;
     RECT  2.16 25.785 218.16 25.92 ;
     RECT  2.16 25.92 20.844 26.055 ;
     RECT  199.692 25.92 218.16 26.055 ;
     RECT  2.16 26.325 20.844 26.595 ;
     RECT  199.692 26.325 218.16 26.595 ;
     RECT  2.16 26.865 20.844 27.135 ;
     RECT  199.692 26.865 218.16 27.135 ;
     RECT  2.16 27.405 20.844 27.675 ;
     RECT  199.692 27.405 218.16 27.675 ;
     RECT  2.16 27.945 20.844 28.215 ;
     RECT  199.692 27.945 218.16 28.215 ;
     RECT  2.16 28.485 20.844 28.755 ;
     RECT  199.692 28.485 218.16 28.755 ;
     RECT  2.16 29.025 20.844 29.295 ;
     RECT  199.692 29.025 218.16 29.295 ;
     RECT  2.16 29.565 20.844 29.835 ;
     RECT  199.692 29.565 218.16 29.835 ;
     RECT  2.16 30.105 20.844 30.375 ;
     RECT  199.692 30.105 218.16 30.375 ;
     RECT  2.16 30.645 20.844 30.915 ;
     RECT  199.692 30.645 218.16 30.915 ;
     RECT  2.16 31.185 20.844 31.455 ;
     RECT  199.692 31.185 218.16 31.455 ;
     RECT  2.16 31.725 20.844 31.995 ;
     RECT  199.692 31.725 218.16 31.995 ;
     RECT  2.16 32.265 20.844 32.535 ;
     RECT  199.692 32.265 218.16 32.535 ;
     RECT  2.16 32.805 20.844 33.075 ;
     RECT  199.692 32.805 218.16 33.075 ;
     RECT  2.16 33.345 20.844 33.615 ;
     RECT  199.692 33.345 218.16 33.615 ;
     RECT  2.16 33.885 20.844 34.155 ;
     RECT  199.692 33.885 218.16 34.155 ;
     RECT  2.16 34.425 20.844 34.695 ;
     RECT  199.692 34.425 218.16 34.695 ;
     RECT  2.16 34.965 20.844 35.235 ;
     RECT  199.692 34.965 218.16 35.235 ;
     RECT  2.16 35.505 20.844 35.775 ;
     RECT  199.692 35.505 218.16 35.775 ;
     RECT  2.16 36.045 20.844 36.315 ;
     RECT  199.692 36.045 218.16 36.315 ;
     RECT  2.16 36.585 20.844 36.855 ;
     RECT  199.692 36.585 218.16 36.855 ;
     RECT  2.16 37.125 20.844 37.395 ;
     RECT  199.692 37.125 218.16 37.395 ;
     RECT  2.16 37.665 20.844 37.935 ;
     RECT  199.692 37.665 218.16 37.935 ;
     RECT  2.16 38.205 20.844 38.475 ;
     RECT  199.692 38.205 218.16 38.475 ;
     RECT  2.16 38.745 20.844 39.015 ;
     RECT  199.692 38.745 218.16 39.015 ;
     RECT  2.16 39.285 20.844 39.555 ;
     RECT  199.692 39.285 218.16 39.555 ;
     RECT  2.16 39.825 20.844 40.095 ;
     RECT  199.692 39.825 218.16 40.095 ;
     RECT  2.16 40.365 20.844 40.635 ;
     RECT  199.692 40.365 218.16 40.635 ;
     RECT  2.16 40.905 20.844 41.175 ;
     RECT  199.692 40.905 218.16 41.175 ;
     RECT  2.16 41.445 20.844 41.715 ;
     RECT  199.692 41.445 218.16 41.715 ;
     RECT  2.16 41.985 20.844 42.255 ;
     RECT  199.692 41.985 218.16 42.255 ;
     RECT  2.16 42.525 20.844 42.795 ;
     RECT  199.692 42.525 218.16 42.795 ;
     RECT  2.16 43.065 20.844 43.335 ;
     RECT  199.692 43.065 218.16 43.335 ;
     RECT  2.16 43.605 20.844 43.875 ;
     RECT  199.692 43.605 218.16 43.875 ;
     RECT  2.16 44.145 20.844 44.415 ;
     RECT  199.692 44.145 218.16 44.415 ;
     RECT  2.16 44.685 20.844 44.955 ;
     RECT  199.692 44.685 218.16 44.955 ;
     RECT  2.16 45.225 20.844 45.495 ;
     RECT  199.692 45.225 218.16 45.495 ;
     RECT  2.16 45.765 20.844 46.035 ;
     RECT  199.692 45.765 218.16 46.035 ;
     RECT  2.16 46.305 20.844 46.575 ;
     RECT  199.692 46.305 218.16 46.575 ;
     RECT  2.16 46.845 20.844 47.115 ;
     RECT  199.692 46.845 218.16 47.115 ;
     RECT  2.16 47.385 20.844 47.655 ;
     RECT  199.692 47.385 218.16 47.655 ;
     RECT  2.16 47.925 20.844 48.195 ;
     RECT  199.692 47.925 218.16 48.195 ;
     RECT  2.16 48.465 20.844 48.735 ;
     RECT  199.692 48.465 218.16 48.735 ;
     RECT  2.16 49.005 20.844 49.275 ;
     RECT  199.692 49.005 218.16 49.275 ;
     RECT  2.16 49.545 20.844 49.815 ;
     RECT  199.692 49.545 218.16 49.815 ;
     RECT  2.16 50.085 20.844 50.355 ;
     RECT  199.692 50.085 218.16 50.355 ;
     RECT  2.16 50.625 20.844 50.895 ;
     RECT  199.692 50.625 218.16 50.895 ;
     RECT  2.16 51.165 20.844 51.435 ;
     RECT  199.692 51.165 218.16 51.435 ;
     RECT  2.16 51.705 20.844 51.975 ;
     RECT  199.692 51.705 218.16 51.975 ;
     RECT  2.16 52.245 20.844 52.515 ;
     RECT  199.692 52.245 218.16 52.515 ;
     RECT  2.16 52.785 20.844 53.055 ;
     RECT  199.692 52.785 218.16 53.055 ;
     RECT  2.16 53.325 20.844 53.595 ;
     RECT  199.692 53.325 218.16 53.595 ;
     RECT  2.16 53.865 20.844 54.135 ;
     RECT  199.692 53.865 218.16 54.135 ;
     RECT  2.16 54.405 20.844 54.675 ;
     RECT  199.692 54.405 218.16 54.675 ;
     RECT  2.16 54.945 20.844 55.215 ;
     RECT  199.692 54.945 218.16 55.215 ;
     RECT  2.16 55.485 20.844 55.755 ;
     RECT  199.692 55.485 218.16 55.755 ;
     RECT  2.16 56.025 20.844 56.295 ;
     RECT  199.692 56.025 218.16 56.295 ;
     RECT  2.16 56.565 20.844 56.835 ;
     RECT  199.692 56.565 218.16 56.835 ;
     RECT  2.16 57.105 20.844 57.375 ;
     RECT  199.692 57.105 218.16 57.375 ;
     RECT  2.16 57.645 20.844 57.915 ;
     RECT  199.692 57.645 218.16 57.915 ;
     RECT  2.16 58.185 20.844 58.455 ;
     RECT  199.692 58.185 218.16 58.455 ;
     RECT  2.16 58.725 20.844 58.995 ;
     RECT  199.692 58.725 218.16 58.995 ;
     RECT  2.16 59.265 20.844 59.535 ;
     RECT  199.692 59.265 218.16 59.535 ;
     RECT  2.16 59.805 20.844 60.075 ;
     RECT  199.692 59.805 218.16 60.075 ;
     RECT  2.16 60.345 20.844 60.615 ;
     RECT  199.692 60.345 218.16 60.615 ;
     RECT  2.16 60.885 20.844 61.155 ;
     RECT  199.692 60.885 218.16 61.155 ;
     RECT  2.16 61.425 20.844 61.695 ;
     RECT  199.692 61.425 218.16 61.695 ;
     RECT  2.16 61.965 20.844 62.235 ;
     RECT  199.692 61.965 218.16 62.235 ;
     RECT  2.16 62.505 20.844 62.775 ;
     RECT  199.692 62.505 218.16 62.775 ;
     RECT  2.16 63.045 20.844 63.315 ;
     RECT  199.692 63.045 218.16 63.315 ;
     RECT  2.16 63.585 20.844 63.855 ;
     RECT  199.692 63.585 218.16 63.855 ;
     RECT  2.16 64.125 20.844 64.395 ;
     RECT  199.692 64.125 218.16 64.395 ;
     RECT  2.16 64.665 20.844 64.935 ;
     RECT  199.692 64.665 218.16 64.935 ;
     RECT  2.16 65.205 20.844 65.475 ;
     RECT  199.692 65.205 218.16 65.475 ;
     RECT  2.16 65.745 20.844 66.015 ;
     RECT  199.692 65.745 218.16 66.015 ;
     RECT  2.16 66.285 20.844 66.555 ;
     RECT  199.692 66.285 218.16 66.555 ;
     RECT  2.16 66.825 20.844 67.095 ;
     RECT  199.692 66.825 218.16 67.095 ;
     RECT  2.16 67.365 20.844 67.635 ;
     RECT  199.692 67.365 218.16 67.635 ;
     RECT  2.16 67.905 20.844 68.175 ;
     RECT  199.692 67.905 218.16 68.175 ;
     RECT  2.16 68.445 20.844 68.715 ;
     RECT  199.692 68.445 218.16 68.715 ;
     RECT  2.16 68.985 20.844 69.255 ;
     RECT  199.692 68.985 218.16 69.255 ;
     RECT  2.16 69.525 20.844 69.795 ;
     RECT  199.692 69.525 218.16 69.795 ;
     RECT  2.16 70.065 20.844 70.335 ;
     RECT  199.692 70.065 218.16 70.335 ;
     RECT  2.16 70.605 20.844 70.875 ;
     RECT  199.692 70.605 218.16 70.875 ;
     RECT  2.16 71.145 20.844 71.415 ;
     RECT  199.692 71.145 218.16 71.415 ;
     RECT  2.16 71.685 20.844 71.955 ;
     RECT  199.692 71.685 218.16 71.955 ;
     RECT  2.16 72.225 20.844 72.495 ;
     RECT  199.692 72.225 218.16 72.495 ;
     RECT  2.16 72.765 20.844 73.035 ;
     RECT  199.692 72.765 218.16 73.035 ;
     RECT  2.16 73.305 20.844 73.575 ;
     RECT  199.692 73.305 218.16 73.575 ;
     RECT  2.16 73.845 20.844 74.115 ;
     RECT  199.692 73.845 218.16 74.115 ;
     RECT  2.16 74.385 20.844 74.655 ;
     RECT  199.692 74.385 218.16 74.655 ;
     RECT  2.16 74.925 20.844 75.195 ;
     RECT  199.692 74.925 218.16 75.195 ;
     RECT  2.16 75.465 20.844 75.735 ;
     RECT  199.692 75.465 218.16 75.735 ;
     RECT  2.16 76.005 20.844 76.275 ;
     RECT  199.692 76.005 218.16 76.275 ;
     RECT  2.16 76.545 20.844 76.815 ;
     RECT  199.692 76.545 218.16 76.815 ;
     RECT  2.16 77.085 20.844 77.355 ;
     RECT  199.692 77.085 218.16 77.355 ;
     RECT  2.16 77.625 20.844 77.895 ;
     RECT  199.692 77.625 218.16 77.895 ;
     RECT  2.16 78.165 20.844 78.435 ;
     RECT  199.692 78.165 218.16 78.435 ;
     RECT  2.16 78.705 20.844 78.975 ;
     RECT  199.692 78.705 218.16 78.975 ;
     RECT  2.16 79.245 20.844 79.515 ;
     RECT  199.692 79.245 218.16 79.515 ;
     RECT  2.16 79.785 20.844 80.055 ;
     RECT  199.692 79.785 218.16 80.055 ;
     RECT  2.16 80.325 20.844 80.595 ;
     RECT  199.692 80.325 218.16 80.595 ;
     RECT  2.16 80.865 20.844 81.135 ;
     RECT  199.692 80.865 218.16 81.135 ;
     RECT  2.16 81.405 20.844 81.675 ;
     RECT  199.692 81.405 218.16 81.675 ;
     RECT  2.16 81.945 20.844 82.215 ;
     RECT  199.692 81.945 218.16 82.215 ;
     RECT  2.16 82.485 20.844 82.755 ;
     RECT  199.692 82.485 218.16 82.755 ;
     RECT  2.16 83.025 20.844 83.295 ;
     RECT  199.692 83.025 218.16 83.295 ;
     RECT  2.16 83.565 20.844 83.835 ;
     RECT  199.692 83.565 218.16 83.835 ;
     RECT  2.16 84.105 20.844 84.375 ;
     RECT  199.692 84.105 218.16 84.375 ;
     RECT  2.16 84.645 20.844 84.915 ;
     RECT  199.692 84.645 218.16 84.915 ;
     RECT  2.16 85.185 20.844 85.455 ;
     RECT  199.692 85.185 218.16 85.455 ;
     RECT  2.16 85.725 20.844 85.995 ;
     RECT  199.692 85.725 218.16 85.995 ;
     RECT  2.16 86.265 20.844 86.535 ;
     RECT  199.692 86.265 218.16 86.535 ;
     RECT  2.16 86.805 20.844 87.075 ;
     RECT  199.692 86.805 218.16 87.075 ;
     RECT  2.16 87.345 20.844 87.615 ;
     RECT  199.692 87.345 218.16 87.615 ;
     RECT  2.16 87.885 20.844 88.155 ;
     RECT  199.692 87.885 218.16 88.155 ;
     RECT  2.16 88.425 20.844 88.695 ;
     RECT  199.692 88.425 218.16 88.695 ;
     RECT  2.16 88.965 20.844 89.235 ;
     RECT  199.692 88.965 218.16 89.235 ;
     RECT  2.16 89.505 20.844 89.775 ;
     RECT  199.692 89.505 218.16 89.775 ;
     RECT  2.16 90.045 20.844 90.315 ;
     RECT  199.692 90.045 218.16 90.315 ;
     RECT  2.16 90.585 20.844 90.855 ;
     RECT  199.692 90.585 218.16 90.855 ;
     RECT  2.16 91.125 20.844 91.395 ;
     RECT  199.692 91.125 218.16 91.395 ;
     RECT  2.16 91.665 20.844 91.935 ;
     RECT  199.692 91.665 218.16 91.935 ;
     RECT  2.16 92.205 20.844 92.475 ;
     RECT  199.692 92.205 218.16 92.475 ;
     RECT  2.16 92.745 20.844 93.015 ;
     RECT  199.692 92.745 218.16 93.015 ;
     RECT  2.16 93.285 20.844 93.555 ;
     RECT  199.692 93.285 218.16 93.555 ;
     RECT  2.16 93.825 20.844 94.095 ;
     RECT  199.692 93.825 218.16 94.095 ;
     RECT  2.16 94.365 20.844 94.635 ;
     RECT  199.692 94.365 218.16 94.635 ;
     RECT  2.16 94.905 20.844 95.175 ;
     RECT  199.692 94.905 218.16 95.175 ;
     RECT  2.16 95.445 20.844 95.715 ;
     RECT  199.692 95.445 218.16 95.715 ;
     RECT  2.16 95.985 20.844 96.255 ;
     RECT  199.692 95.985 218.16 96.255 ;
     RECT  2.16 96.525 20.844 96.795 ;
     RECT  199.692 96.525 218.16 96.795 ;
     RECT  2.16 97.065 20.844 97.335 ;
     RECT  199.692 97.065 218.16 97.335 ;
     RECT  2.16 97.605 20.844 97.875 ;
     RECT  199.692 97.605 218.16 97.875 ;
     RECT  2.16 98.145 20.844 98.415 ;
     RECT  199.692 98.145 218.16 98.415 ;
     RECT  2.16 98.685 20.844 98.955 ;
     RECT  199.692 98.685 218.16 98.955 ;
     RECT  2.16 99.225 20.844 99.495 ;
     RECT  199.692 99.225 218.16 99.495 ;
     RECT  2.16 99.765 20.844 100.035 ;
     RECT  199.692 99.765 218.16 100.035 ;
     RECT  2.16 100.305 20.844 100.575 ;
     RECT  199.692 100.305 218.16 100.575 ;
     RECT  2.16 100.845 218.16 101.115 ;
     RECT  2.16 101.385 218.16 101.655 ;
     RECT  2.16 101.925 218.16 102.195 ;
     RECT  2.16 102.465 218.16 102.735 ;
     RECT  2.16 103.005 218.16 103.275 ;
     RECT  2.16 103.545 218.16 103.815 ;
     RECT  2.16 104.085 218.16 104.355 ;
     RECT  2.16 104.625 218.16 104.895 ;
     RECT  2.16 105.165 218.16 105.435 ;
     RECT  2.16 105.705 218.16 105.975 ;
     RECT  2.16 106.245 218.16 106.515 ;
     RECT  2.16 106.785 218.16 107.055 ;
     RECT  2.16 107.325 218.16 107.595 ;
     RECT  2.16 107.865 218.16 108.135 ;
     RECT  2.16 108.405 218.16 108.675 ;
     RECT  2.16 108.945 218.16 109.215 ;
     RECT  2.16 109.485 218.16 109.755 ;
     RECT  2.16 110.025 218.16 110.295 ;
     RECT  2.16 110.565 218.16 110.835 ;
     RECT  2.16 111.105 218.16 111.375 ;
     RECT  2.16 111.645 218.16 111.915 ;
     RECT  2.16 112.185 218.16 112.455 ;
     RECT  2.16 112.725 218.16 112.995 ;
     RECT  2.16 113.265 218.16 113.535 ;
     RECT  2.16 113.805 218.16 114.075 ;
     RECT  2.16 114.345 218.16 114.615 ;
     RECT  2.16 114.885 218.16 115.155 ;
     RECT  2.16 115.425 218.16 115.695 ;
     RECT  2.16 115.965 218.16 116.235 ;
     RECT  2.16 116.505 218.16 116.775 ;
     RECT  2.16 117.045 218.16 117.315 ;
     RECT  2.16 117.585 218.16 117.855 ;
     RECT  2.16 118.125 218.16 118.395 ;
     RECT  2.16 118.665 218.16 118.935 ;
     RECT  2.16 119.205 218.16 119.475 ;
     RECT  2.16 119.745 218.16 120.015 ;
     RECT  2.16 120.285 218.16 120.555 ;
     RECT  2.16 120.825 218.16 121.095 ;
     RECT  2.16 121.365 218.16 121.635 ;
     RECT  2.16 121.905 218.16 122.175 ;
     RECT  2.16 122.445 218.16 122.715 ;
     RECT  2.16 122.985 218.16 123.12 ;
    LAYER RVTP ;
     RECT  2.16 2.295 218.16 2.565 ;
     RECT  2.16 2.835 218.16 3.105 ;
     RECT  2.16 3.375 218.16 3.645 ;
     RECT  2.16 3.915 218.16 4.185 ;
     RECT  2.16 4.455 218.16 4.725 ;
     RECT  2.16 4.995 218.16 5.265 ;
     RECT  2.16 5.535 218.16 5.805 ;
     RECT  2.16 6.075 218.16 6.345 ;
     RECT  2.16 6.615 218.16 6.885 ;
     RECT  2.16 7.155 218.16 7.425 ;
     RECT  2.16 7.695 218.16 7.965 ;
     RECT  2.16 8.235 218.16 8.505 ;
     RECT  2.16 8.775 218.16 9.045 ;
     RECT  2.16 9.315 218.16 9.585 ;
     RECT  2.16 9.855 218.16 10.125 ;
     RECT  2.16 10.395 218.16 10.665 ;
     RECT  2.16 10.935 218.16 11.205 ;
     RECT  2.16 11.475 218.16 11.745 ;
     RECT  2.16 12.015 218.16 12.285 ;
     RECT  2.16 12.555 218.16 12.825 ;
     RECT  2.16 13.095 218.16 13.365 ;
     RECT  2.16 13.635 218.16 13.905 ;
     RECT  2.16 14.175 218.16 14.445 ;
     RECT  2.16 14.715 218.16 14.985 ;
     RECT  2.16 15.255 218.16 15.525 ;
     RECT  2.16 15.795 218.16 16.065 ;
     RECT  2.16 16.335 218.16 16.605 ;
     RECT  2.16 16.875 218.16 17.145 ;
     RECT  2.16 17.415 218.16 17.685 ;
     RECT  2.16 17.955 218.16 18.225 ;
     RECT  2.16 18.495 218.16 18.765 ;
     RECT  2.16 19.035 218.16 19.305 ;
     RECT  2.16 19.575 218.16 19.845 ;
     RECT  2.16 20.115 218.16 20.385 ;
     RECT  2.16 20.655 218.16 20.925 ;
     RECT  2.16 21.195 218.16 21.465 ;
     RECT  2.16 21.735 218.16 22.005 ;
     RECT  2.16 22.275 218.16 22.545 ;
     RECT  2.16 22.815 218.16 23.085 ;
     RECT  2.16 23.355 218.16 23.625 ;
     RECT  2.16 23.895 218.16 24.165 ;
     RECT  2.16 24.435 218.16 24.705 ;
     RECT  2.16 24.975 218.16 25.245 ;
     RECT  2.16 25.515 218.16 25.785 ;
     RECT  2.16 26.055 20.844 26.325 ;
     RECT  199.692 26.055 218.16 26.325 ;
     RECT  2.16 26.595 20.844 26.865 ;
     RECT  199.692 26.595 218.16 26.865 ;
     RECT  2.16 27.135 20.844 27.405 ;
     RECT  199.692 27.135 218.16 27.405 ;
     RECT  2.16 27.675 20.844 27.945 ;
     RECT  199.692 27.675 218.16 27.945 ;
     RECT  2.16 28.215 20.844 28.485 ;
     RECT  199.692 28.215 218.16 28.485 ;
     RECT  2.16 28.755 20.844 29.025 ;
     RECT  199.692 28.755 218.16 29.025 ;
     RECT  2.16 29.295 20.844 29.565 ;
     RECT  199.692 29.295 218.16 29.565 ;
     RECT  2.16 29.835 20.844 30.105 ;
     RECT  199.692 29.835 218.16 30.105 ;
     RECT  2.16 30.375 20.844 30.645 ;
     RECT  199.692 30.375 218.16 30.645 ;
     RECT  2.16 30.915 20.844 31.185 ;
     RECT  199.692 30.915 218.16 31.185 ;
     RECT  2.16 31.455 20.844 31.725 ;
     RECT  199.692 31.455 218.16 31.725 ;
     RECT  2.16 31.995 20.844 32.265 ;
     RECT  199.692 31.995 218.16 32.265 ;
     RECT  2.16 32.535 20.844 32.805 ;
     RECT  199.692 32.535 218.16 32.805 ;
     RECT  2.16 33.075 20.844 33.345 ;
     RECT  199.692 33.075 218.16 33.345 ;
     RECT  2.16 33.615 20.844 33.885 ;
     RECT  199.692 33.615 218.16 33.885 ;
     RECT  2.16 34.155 20.844 34.425 ;
     RECT  199.692 34.155 218.16 34.425 ;
     RECT  2.16 34.695 20.844 34.965 ;
     RECT  199.692 34.695 218.16 34.965 ;
     RECT  2.16 35.235 20.844 35.505 ;
     RECT  199.692 35.235 218.16 35.505 ;
     RECT  2.16 35.775 20.844 36.045 ;
     RECT  199.692 35.775 218.16 36.045 ;
     RECT  2.16 36.315 20.844 36.585 ;
     RECT  199.692 36.315 218.16 36.585 ;
     RECT  2.16 36.855 20.844 37.125 ;
     RECT  199.692 36.855 218.16 37.125 ;
     RECT  2.16 37.395 20.844 37.665 ;
     RECT  199.692 37.395 218.16 37.665 ;
     RECT  2.16 37.935 20.844 38.205 ;
     RECT  199.692 37.935 218.16 38.205 ;
     RECT  2.16 38.475 20.844 38.745 ;
     RECT  199.692 38.475 218.16 38.745 ;
     RECT  2.16 39.015 20.844 39.285 ;
     RECT  199.692 39.015 218.16 39.285 ;
     RECT  2.16 39.555 20.844 39.825 ;
     RECT  199.692 39.555 218.16 39.825 ;
     RECT  2.16 40.095 20.844 40.365 ;
     RECT  199.692 40.095 218.16 40.365 ;
     RECT  2.16 40.635 20.844 40.905 ;
     RECT  199.692 40.635 218.16 40.905 ;
     RECT  2.16 41.175 20.844 41.445 ;
     RECT  199.692 41.175 218.16 41.445 ;
     RECT  2.16 41.715 20.844 41.985 ;
     RECT  199.692 41.715 218.16 41.985 ;
     RECT  2.16 42.255 20.844 42.525 ;
     RECT  199.692 42.255 218.16 42.525 ;
     RECT  2.16 42.795 20.844 43.065 ;
     RECT  199.692 42.795 218.16 43.065 ;
     RECT  2.16 43.335 20.844 43.605 ;
     RECT  199.692 43.335 218.16 43.605 ;
     RECT  2.16 43.875 20.844 44.145 ;
     RECT  199.692 43.875 218.16 44.145 ;
     RECT  2.16 44.415 20.844 44.685 ;
     RECT  199.692 44.415 218.16 44.685 ;
     RECT  2.16 44.955 20.844 45.225 ;
     RECT  199.692 44.955 218.16 45.225 ;
     RECT  2.16 45.495 20.844 45.765 ;
     RECT  199.692 45.495 218.16 45.765 ;
     RECT  2.16 46.035 20.844 46.305 ;
     RECT  199.692 46.035 218.16 46.305 ;
     RECT  2.16 46.575 20.844 46.845 ;
     RECT  199.692 46.575 218.16 46.845 ;
     RECT  2.16 47.115 20.844 47.385 ;
     RECT  199.692 47.115 218.16 47.385 ;
     RECT  2.16 47.655 20.844 47.925 ;
     RECT  199.692 47.655 218.16 47.925 ;
     RECT  2.16 48.195 20.844 48.465 ;
     RECT  199.692 48.195 218.16 48.465 ;
     RECT  2.16 48.735 20.844 49.005 ;
     RECT  199.692 48.735 218.16 49.005 ;
     RECT  2.16 49.275 20.844 49.545 ;
     RECT  199.692 49.275 218.16 49.545 ;
     RECT  2.16 49.815 20.844 50.085 ;
     RECT  199.692 49.815 218.16 50.085 ;
     RECT  2.16 50.355 20.844 50.625 ;
     RECT  199.692 50.355 218.16 50.625 ;
     RECT  2.16 50.895 20.844 51.165 ;
     RECT  199.692 50.895 218.16 51.165 ;
     RECT  2.16 51.435 20.844 51.705 ;
     RECT  199.692 51.435 218.16 51.705 ;
     RECT  2.16 51.975 20.844 52.245 ;
     RECT  199.692 51.975 218.16 52.245 ;
     RECT  2.16 52.515 20.844 52.785 ;
     RECT  199.692 52.515 218.16 52.785 ;
     RECT  2.16 53.055 20.844 53.325 ;
     RECT  199.692 53.055 218.16 53.325 ;
     RECT  2.16 53.595 20.844 53.865 ;
     RECT  199.692 53.595 218.16 53.865 ;
     RECT  2.16 54.135 20.844 54.405 ;
     RECT  199.692 54.135 218.16 54.405 ;
     RECT  2.16 54.675 20.844 54.945 ;
     RECT  199.692 54.675 218.16 54.945 ;
     RECT  2.16 55.215 20.844 55.485 ;
     RECT  199.692 55.215 218.16 55.485 ;
     RECT  2.16 55.755 20.844 56.025 ;
     RECT  199.692 55.755 218.16 56.025 ;
     RECT  2.16 56.295 20.844 56.565 ;
     RECT  199.692 56.295 218.16 56.565 ;
     RECT  2.16 56.835 20.844 57.105 ;
     RECT  199.692 56.835 218.16 57.105 ;
     RECT  2.16 57.375 20.844 57.645 ;
     RECT  199.692 57.375 218.16 57.645 ;
     RECT  2.16 57.915 20.844 58.185 ;
     RECT  199.692 57.915 218.16 58.185 ;
     RECT  2.16 58.455 20.844 58.725 ;
     RECT  199.692 58.455 218.16 58.725 ;
     RECT  2.16 58.995 20.844 59.265 ;
     RECT  199.692 58.995 218.16 59.265 ;
     RECT  2.16 59.535 20.844 59.805 ;
     RECT  199.692 59.535 218.16 59.805 ;
     RECT  2.16 60.075 20.844 60.345 ;
     RECT  199.692 60.075 218.16 60.345 ;
     RECT  2.16 60.615 20.844 60.885 ;
     RECT  199.692 60.615 218.16 60.885 ;
     RECT  2.16 61.155 20.844 61.425 ;
     RECT  199.692 61.155 218.16 61.425 ;
     RECT  2.16 61.695 20.844 61.965 ;
     RECT  199.692 61.695 218.16 61.965 ;
     RECT  2.16 62.235 20.844 62.505 ;
     RECT  199.692 62.235 218.16 62.505 ;
     RECT  2.16 62.775 20.844 63.045 ;
     RECT  199.692 62.775 218.16 63.045 ;
     RECT  2.16 63.315 20.844 63.585 ;
     RECT  199.692 63.315 218.16 63.585 ;
     RECT  2.16 63.855 20.844 64.125 ;
     RECT  199.692 63.855 218.16 64.125 ;
     RECT  2.16 64.395 20.844 64.665 ;
     RECT  199.692 64.395 218.16 64.665 ;
     RECT  2.16 64.935 20.844 65.205 ;
     RECT  199.692 64.935 218.16 65.205 ;
     RECT  2.16 65.475 20.844 65.745 ;
     RECT  199.692 65.475 218.16 65.745 ;
     RECT  2.16 66.015 20.844 66.285 ;
     RECT  199.692 66.015 218.16 66.285 ;
     RECT  2.16 66.555 20.844 66.825 ;
     RECT  199.692 66.555 218.16 66.825 ;
     RECT  2.16 67.095 20.844 67.365 ;
     RECT  199.692 67.095 218.16 67.365 ;
     RECT  2.16 67.635 20.844 67.905 ;
     RECT  199.692 67.635 218.16 67.905 ;
     RECT  2.16 68.175 20.844 68.445 ;
     RECT  199.692 68.175 218.16 68.445 ;
     RECT  2.16 68.715 20.844 68.985 ;
     RECT  199.692 68.715 218.16 68.985 ;
     RECT  2.16 69.255 20.844 69.525 ;
     RECT  199.692 69.255 218.16 69.525 ;
     RECT  2.16 69.795 20.844 70.065 ;
     RECT  199.692 69.795 218.16 70.065 ;
     RECT  2.16 70.335 20.844 70.605 ;
     RECT  199.692 70.335 218.16 70.605 ;
     RECT  2.16 70.875 20.844 71.145 ;
     RECT  199.692 70.875 218.16 71.145 ;
     RECT  2.16 71.415 20.844 71.685 ;
     RECT  199.692 71.415 218.16 71.685 ;
     RECT  2.16 71.955 20.844 72.225 ;
     RECT  199.692 71.955 218.16 72.225 ;
     RECT  2.16 72.495 20.844 72.765 ;
     RECT  199.692 72.495 218.16 72.765 ;
     RECT  2.16 73.035 20.844 73.305 ;
     RECT  199.692 73.035 218.16 73.305 ;
     RECT  2.16 73.575 20.844 73.845 ;
     RECT  199.692 73.575 218.16 73.845 ;
     RECT  2.16 74.115 20.844 74.385 ;
     RECT  199.692 74.115 218.16 74.385 ;
     RECT  2.16 74.655 20.844 74.925 ;
     RECT  199.692 74.655 218.16 74.925 ;
     RECT  2.16 75.195 20.844 75.465 ;
     RECT  199.692 75.195 218.16 75.465 ;
     RECT  2.16 75.735 20.844 76.005 ;
     RECT  199.692 75.735 218.16 76.005 ;
     RECT  2.16 76.275 20.844 76.545 ;
     RECT  199.692 76.275 218.16 76.545 ;
     RECT  2.16 76.815 20.844 77.085 ;
     RECT  199.692 76.815 218.16 77.085 ;
     RECT  2.16 77.355 20.844 77.625 ;
     RECT  199.692 77.355 218.16 77.625 ;
     RECT  2.16 77.895 20.844 78.165 ;
     RECT  199.692 77.895 218.16 78.165 ;
     RECT  2.16 78.435 20.844 78.705 ;
     RECT  199.692 78.435 218.16 78.705 ;
     RECT  2.16 78.975 20.844 79.245 ;
     RECT  199.692 78.975 218.16 79.245 ;
     RECT  2.16 79.515 20.844 79.785 ;
     RECT  199.692 79.515 218.16 79.785 ;
     RECT  2.16 80.055 20.844 80.325 ;
     RECT  199.692 80.055 218.16 80.325 ;
     RECT  2.16 80.595 20.844 80.865 ;
     RECT  199.692 80.595 218.16 80.865 ;
     RECT  2.16 81.135 20.844 81.405 ;
     RECT  199.692 81.135 218.16 81.405 ;
     RECT  2.16 81.675 20.844 81.945 ;
     RECT  199.692 81.675 218.16 81.945 ;
     RECT  2.16 82.215 20.844 82.485 ;
     RECT  199.692 82.215 218.16 82.485 ;
     RECT  2.16 82.755 20.844 83.025 ;
     RECT  199.692 82.755 218.16 83.025 ;
     RECT  2.16 83.295 20.844 83.565 ;
     RECT  199.692 83.295 218.16 83.565 ;
     RECT  2.16 83.835 20.844 84.105 ;
     RECT  199.692 83.835 218.16 84.105 ;
     RECT  2.16 84.375 20.844 84.645 ;
     RECT  199.692 84.375 218.16 84.645 ;
     RECT  2.16 84.915 20.844 85.185 ;
     RECT  199.692 84.915 218.16 85.185 ;
     RECT  2.16 85.455 20.844 85.725 ;
     RECT  199.692 85.455 218.16 85.725 ;
     RECT  2.16 85.995 20.844 86.265 ;
     RECT  199.692 85.995 218.16 86.265 ;
     RECT  2.16 86.535 20.844 86.805 ;
     RECT  199.692 86.535 218.16 86.805 ;
     RECT  2.16 87.075 20.844 87.345 ;
     RECT  199.692 87.075 218.16 87.345 ;
     RECT  2.16 87.615 20.844 87.885 ;
     RECT  199.692 87.615 218.16 87.885 ;
     RECT  2.16 88.155 20.844 88.425 ;
     RECT  199.692 88.155 218.16 88.425 ;
     RECT  2.16 88.695 20.844 88.965 ;
     RECT  199.692 88.695 218.16 88.965 ;
     RECT  2.16 89.235 20.844 89.505 ;
     RECT  199.692 89.235 218.16 89.505 ;
     RECT  2.16 89.775 20.844 90.045 ;
     RECT  199.692 89.775 218.16 90.045 ;
     RECT  2.16 90.315 20.844 90.585 ;
     RECT  199.692 90.315 218.16 90.585 ;
     RECT  2.16 90.855 20.844 91.125 ;
     RECT  199.692 90.855 218.16 91.125 ;
     RECT  2.16 91.395 20.844 91.665 ;
     RECT  199.692 91.395 218.16 91.665 ;
     RECT  2.16 91.935 20.844 92.205 ;
     RECT  199.692 91.935 218.16 92.205 ;
     RECT  2.16 92.475 20.844 92.745 ;
     RECT  199.692 92.475 218.16 92.745 ;
     RECT  2.16 93.015 20.844 93.285 ;
     RECT  199.692 93.015 218.16 93.285 ;
     RECT  2.16 93.555 20.844 93.825 ;
     RECT  199.692 93.555 218.16 93.825 ;
     RECT  2.16 94.095 20.844 94.365 ;
     RECT  199.692 94.095 218.16 94.365 ;
     RECT  2.16 94.635 20.844 94.905 ;
     RECT  199.692 94.635 218.16 94.905 ;
     RECT  2.16 95.175 20.844 95.445 ;
     RECT  199.692 95.175 218.16 95.445 ;
     RECT  2.16 95.715 20.844 95.985 ;
     RECT  199.692 95.715 218.16 95.985 ;
     RECT  2.16 96.255 20.844 96.525 ;
     RECT  199.692 96.255 218.16 96.525 ;
     RECT  2.16 96.795 20.844 97.065 ;
     RECT  199.692 96.795 218.16 97.065 ;
     RECT  2.16 97.335 20.844 97.605 ;
     RECT  199.692 97.335 218.16 97.605 ;
     RECT  2.16 97.875 20.844 98.145 ;
     RECT  199.692 97.875 218.16 98.145 ;
     RECT  2.16 98.415 20.844 98.685 ;
     RECT  199.692 98.415 218.16 98.685 ;
     RECT  2.16 98.955 20.844 99.225 ;
     RECT  199.692 98.955 218.16 99.225 ;
     RECT  2.16 99.495 20.844 99.765 ;
     RECT  199.692 99.495 218.16 99.765 ;
     RECT  2.16 100.035 20.844 100.305 ;
     RECT  199.692 100.035 218.16 100.305 ;
     RECT  2.16 100.575 20.844 100.71 ;
     RECT  199.692 100.575 218.16 100.71 ;
     RECT  2.16 100.71 218.16 100.845 ;
     RECT  2.16 101.115 218.16 101.385 ;
     RECT  2.16 101.655 218.16 101.925 ;
     RECT  2.16 102.195 218.16 102.465 ;
     RECT  2.16 102.735 218.16 103.005 ;
     RECT  2.16 103.275 218.16 103.545 ;
     RECT  2.16 103.815 218.16 104.085 ;
     RECT  2.16 104.355 218.16 104.625 ;
     RECT  2.16 104.895 218.16 105.165 ;
     RECT  2.16 105.435 218.16 105.705 ;
     RECT  2.16 105.975 218.16 106.245 ;
     RECT  2.16 106.515 218.16 106.785 ;
     RECT  2.16 107.055 218.16 107.325 ;
     RECT  2.16 107.595 218.16 107.865 ;
     RECT  2.16 108.135 218.16 108.405 ;
     RECT  2.16 108.675 218.16 108.945 ;
     RECT  2.16 109.215 218.16 109.485 ;
     RECT  2.16 109.755 218.16 110.025 ;
     RECT  2.16 110.295 218.16 110.565 ;
     RECT  2.16 110.835 218.16 111.105 ;
     RECT  2.16 111.375 218.16 111.645 ;
     RECT  2.16 111.915 218.16 112.185 ;
     RECT  2.16 112.455 218.16 112.725 ;
     RECT  2.16 112.995 218.16 113.265 ;
     RECT  2.16 113.535 218.16 113.805 ;
     RECT  2.16 114.075 218.16 114.345 ;
     RECT  2.16 114.615 218.16 114.885 ;
     RECT  2.16 115.155 218.16 115.425 ;
     RECT  2.16 115.695 218.16 115.965 ;
     RECT  2.16 116.235 218.16 116.505 ;
     RECT  2.16 116.775 218.16 117.045 ;
     RECT  2.16 117.315 218.16 117.585 ;
     RECT  2.16 117.855 218.16 118.125 ;
     RECT  2.16 118.395 218.16 118.665 ;
     RECT  2.16 118.935 218.16 119.205 ;
     RECT  2.16 119.475 218.16 119.745 ;
     RECT  2.16 120.015 218.16 120.285 ;
     RECT  2.16 120.555 218.16 120.825 ;
     RECT  2.16 121.095 218.16 121.365 ;
     RECT  2.16 121.635 218.16 121.905 ;
     RECT  2.16 122.175 218.16 122.445 ;
     RECT  2.16 122.715 218.16 122.985 ;
    LAYER M1 ;
     RECT  2.16 2.151 218.16 25.929 ;
     RECT  22.896 28.08 197.64 98.55 ;
     RECT  2.16 25.929 20.844 100.701 ;
     RECT  199.692 25.929 218.16 100.701 ;
     RECT  2.16 100.701 218.16 123.129 ;
    LAYER M2 ;
     RECT  0.103 29.34 0.139 33.948 ;
     RECT  0.103 34.704 0.139 37.422 ;
     RECT  0.103 38.178 0.139 39.114 ;
     RECT  0.103 55.422 0.139 55.44 ;
     RECT  0.103 59.076 0.139 59.634 ;
     RECT  0.103 63.828 0.139 64.62 ;
     RECT  0.103 65.412 0.139 65.43 ;
     RECT  0.103 68.382 0.139 68.4 ;
     RECT  0.139 29.268 0.175 33.948 ;
     RECT  0.139 34.704 0.175 39.114 ;
     RECT  0.103 54.612 0.175 54.63 ;
     RECT  0.139 55.422 0.175 55.476 ;
     RECT  0.103 60.93 0.175 62.19 ;
     RECT  0.139 68.382 0.175 68.814 ;
     RECT  0.175 54.072 0.211 55.71 ;
     RECT  0.103 56.844 0.211 56.862 ;
     RECT  0.139 63.828 0.211 65.43 ;
     RECT  0.175 29.268 0.535 39.114 ;
     RECT  0.103 43.65 0.535 44.1 ;
     RECT  0.175 60.786 0.535 62.19 ;
     RECT  0.211 63.828 0.535 65.466 ;
     RECT  0.175 67.914 0.571 68.814 ;
     RECT  0.571 67.572 0.859 68.814 ;
     RECT  0.103 40.842 1.147 41.4 ;
     RECT  0.139 42.192 1.147 42.21 ;
     RECT  0.535 60.786 1.147 65.466 ;
     RECT  1.147 40.842 1.183 42.21 ;
     RECT  1.147 60.426 1.183 65.466 ;
     RECT  1.147 66.222 1.183 66.24 ;
     RECT  1.183 40.842 1.219 42.282 ;
     RECT  0.859 67.572 1.255 69.318 ;
     RECT  1.219 40.842 1.291 42.318 ;
     RECT  0.103 57.852 1.327 57.87 ;
     RECT  0.139 58.932 1.327 59.634 ;
     RECT  1.291 40.842 1.723 42.588 ;
     RECT  0.535 43.65 1.723 44.208 ;
     RECT  0.211 54.072 1.723 56.862 ;
     RECT  1.327 57.852 1.723 59.634 ;
     RECT  1.183 60.426 1.723 66.24 ;
     RECT  1.723 54.072 1.759 56.934 ;
     RECT  1.723 57.69 1.759 66.24 ;
     RECT  0.535 29.268 2.16 39.582 ;
     RECT  1.723 40.842 2.16 44.208 ;
     RECT  1.147 45.162 2.16 45.18 ;
     RECT  1.759 54.072 2.16 66.24 ;
     RECT  1.255 67.302 2.16 69.318 ;
     RECT  2.16 2.151 20.844 123.129 ;
     RECT  20.844 31.428 21.551 35.874 ;
     RECT  20.844 38.106 21.659 39.204 ;
     RECT  20.844 30.078 21.667 30.204 ;
     RECT  21.551 31.428 21.695 34.182 ;
     RECT  21.551 34.938 21.695 35.874 ;
     RECT  21.695 32.274 21.731 34.182 ;
     RECT  21.695 34.938 21.767 35.604 ;
     RECT  20.844 75.096 21.983 75.528 ;
     RECT  20.844 69.804 22.019 70.974 ;
     RECT  21.983 75.51 22.055 75.528 ;
     RECT  20.844 95.454 22.091 96.624 ;
     RECT  22.091 96.606 22.127 96.624 ;
     RECT  21.667 30.078 22.423 30.249 ;
     RECT  21.695 31.428 22.423 31.446 ;
     RECT  21.659 38.106 22.459 38.7 ;
     RECT  20.844 40.176 22.603 68.634 ;
     RECT  20.844 2.151 22.896 29.052 ;
     RECT  22.423 30.078 22.896 31.446 ;
     RECT  21.731 32.976 22.896 34.182 ;
     RECT  21.767 34.938 22.896 35.298 ;
     RECT  22.459 38.106 22.896 38.772 ;
     RECT  22.603 40.104 22.896 68.634 ;
     RECT  22.019 69.804 22.896 70.398 ;
     RECT  20.844 79.416 22.896 79.434 ;
     RECT  20.844 83.502 22.896 83.52 ;
     RECT  20.844 84.276 22.896 84.294 ;
     RECT  20.844 85.626 22.896 85.644 ;
     RECT  20.844 87.246 22.896 87.264 ;
     RECT  20.844 93.456 22.896 93.474 ;
     RECT  22.091 95.454 22.896 95.508 ;
     RECT  20.844 98.316 22.896 123.129 ;
     RECT  22.896 2.151 197.64 123.129 ;
     RECT  197.64 40.878 197.879 42.084 ;
     RECT  197.64 71.316 198.383 71.514 ;
     RECT  197.64 59.472 198.391 59.49 ;
     RECT  197.64 67.716 198.391 67.734 ;
     RECT  198.391 59.472 198.463 59.634 ;
     RECT  197.64 55.026 198.499 58.014 ;
     RECT  198.463 59.004 198.499 59.634 ;
     RECT  197.64 37.566 198.571 38.124 ;
     RECT  197.64 39.294 198.571 39.312 ;
     RECT  197.64 50.292 198.571 51.084 ;
     RECT  198.499 83.646 198.571 83.664 ;
     RECT  197.64 62.046 198.607 66.51 ;
     RECT  198.499 55.026 198.679 59.634 ;
     RECT  197.64 72.396 198.679 76.23 ;
     RECT  198.679 72.396 198.715 76.644 ;
     RECT  198.715 72.396 198.787 77.544 ;
     RECT  198.427 80.496 198.823 80.514 ;
     RECT  198.607 61.866 198.859 66.51 ;
     RECT  198.391 67.446 198.859 67.734 ;
     RECT  198.787 72.396 198.859 78.12 ;
     RECT  197.64 52.056 198.895 53.964 ;
     RECT  198.679 55.026 198.895 60.066 ;
     RECT  198.391 61.011 198.895 61.029 ;
     RECT  198.823 79.758 198.895 80.514 ;
     RECT  197.879 41.796 198.931 42.084 ;
     RECT  197.64 42.966 198.931 45.414 ;
     RECT  198.571 50.13 198.931 51.084 ;
     RECT  198.895 52.056 199.147 61.029 ;
     RECT  198.859 61.866 199.147 67.734 ;
     RECT  198.383 71.496 199.255 71.514 ;
     RECT  198.859 72.396 199.255 78.804 ;
     RECT  197.64 2.151 199.327 29.394 ;
     RECT  198.463 30.231 199.327 30.249 ;
     RECT  197.64 48.366 199.327 49.374 ;
     RECT  198.931 50.13 199.327 51.264 ;
     RECT  197.64 70.506 199.327 70.524 ;
     RECT  199.255 71.496 199.327 78.804 ;
     RECT  198.895 79.758 199.399 80.928 ;
     RECT  199.327 48.366 199.435 51.264 ;
     RECT  199.147 52.056 199.435 67.734 ;
     RECT  197.64 35.856 199.471 36.504 ;
     RECT  198.571 37.566 199.471 39.312 ;
     RECT  197.64 68.688 199.579 69.444 ;
     RECT  198.931 41.796 199.615 45.414 ;
     RECT  197.64 46.314 199.615 47.214 ;
     RECT  199.399 79.596 199.651 80.928 ;
     RECT  199.615 41.796 199.687 47.214 ;
     RECT  199.435 48.366 199.687 67.734 ;
     RECT  199.327 2.151 199.692 30.249 ;
     RECT  197.64 31.086 199.692 31.914 ;
     RECT  197.64 32.814 199.692 34.074 ;
     RECT  199.471 35.856 199.692 39.312 ;
     RECT  197.879 40.986 199.692 41.004 ;
     RECT  199.687 41.796 199.692 67.734 ;
     RECT  199.579 68.688 199.692 69.48 ;
     RECT  199.327 70.506 199.692 78.804 ;
     RECT  199.651 79.596 199.692 81.504 ;
     RECT  198.571 82.656 199.692 83.664 ;
     RECT  197.64 98.316 199.692 123.129 ;
     RECT  199.692 2.151 218.16 123.129 ;
     RECT  218.16 30.618 218.219 57.474 ;
     RECT  218.16 58.356 218.219 59.724 ;
     RECT  218.219 58.356 218.255 59.634 ;
     RECT  218.219 30.618 218.291 57.402 ;
     RECT  218.255 58.356 218.291 59.562 ;
     RECT  218.16 27.648 218.327 29.556 ;
     RECT  218.291 30.924 218.903 57.402 ;
     RECT  218.903 30.924 219.299 38.934 ;
     RECT  219.299 30.924 219.407 38.736 ;
     RECT  219.407 30.924 219.443 36.684 ;
     RECT  219.407 37.566 219.443 38.736 ;
     RECT  218.903 39.726 219.443 40.824 ;
     RECT  218.903 44.316 219.443 54.36 ;
     RECT  218.903 55.458 219.443 57.402 ;
     RECT  219.443 31.896 219.479 36.684 ;
     RECT  219.443 39.726 219.479 40.158 ;
     RECT  219.443 52.326 219.479 54.36 ;
     RECT  219.443 55.458 219.479 57.096 ;
     RECT  218.327 27.648 219.515 28.98 ;
     RECT  219.443 30.924 219.515 30.942 ;
     RECT  219.479 54.108 219.515 54.36 ;
     RECT  219.515 28.962 219.551 28.98 ;
     RECT  219.515 54.342 219.551 54.36 ;
     RECT  219.515 27.648 219.587 27.936 ;
     RECT  219.587 27.918 219.623 27.936 ;
     RECT  218.291 58.356 220.091 58.644 ;
     RECT  219.479 32.31 220.127 36.684 ;
     RECT  219.443 44.316 220.127 48.924 ;
     RECT  220.091 58.356 220.127 58.518 ;
     RECT  220.127 32.31 220.163 35.46 ;
     RECT  218.903 41.616 220.163 43.524 ;
     RECT  220.127 44.316 220.163 47.718 ;
     RECT  220.127 48.51 220.163 48.924 ;
     RECT  219.443 49.716 220.163 50.994 ;
     RECT  219.479 52.326 220.163 53.118 ;
     RECT  219.479 55.926 220.163 57.096 ;
     RECT  220.163 32.31 220.199 34.146 ;
     RECT  220.163 35.136 220.199 35.46 ;
     RECT  220.127 36.63 220.199 36.684 ;
     RECT  219.443 38.286 220.199 38.736 ;
     RECT  220.163 41.616 220.199 42.012 ;
     RECT  220.163 42.966 220.199 43.524 ;
     RECT  220.163 44.316 220.199 45.954 ;
     RECT  220.163 47.016 220.199 47.718 ;
     RECT  220.163 48.546 220.199 48.924 ;
     RECT  220.163 52.83 220.199 53.118 ;
     RECT  220.163 55.926 220.199 57.024 ;
     RECT  218.291 59.544 220.199 59.562 ;
     RECT  220.199 32.31 220.235 32.328 ;
     RECT  220.199 33.696 220.235 34.146 ;
     RECT  220.199 35.442 220.235 35.46 ;
     RECT  220.199 36.666 220.235 36.684 ;
     RECT  220.199 38.718 220.235 38.736 ;
     RECT  220.199 41.958 220.235 41.976 ;
     RECT  220.199 42.966 220.235 42.984 ;
     RECT  220.199 44.316 220.235 44.784 ;
     RECT  220.199 45.936 220.235 45.954 ;
     RECT  220.199 47.286 220.235 47.304 ;
     RECT  220.199 48.906 220.235 48.924 ;
     RECT  220.163 50.526 220.235 50.994 ;
     RECT  220.199 55.926 220.235 56.664 ;
     RECT  220.127 58.356 220.235 58.374 ;
     RECT  220.163 49.716 220.307 49.734 ;
     RECT  220.199 53.1 220.307 53.118 ;
    LAYER M3 ;
     RECT  2.415 2.143 2.505 2.413 ;
     RECT  7.815 2.143 7.905 2.413 ;
     RECT  13.215 2.143 13.305 2.413 ;
     RECT  18.615 2.143 18.705 2.413 ;
     RECT  24.015 2.143 24.105 2.413 ;
     RECT  29.415 2.143 29.505 2.413 ;
     RECT  34.815 2.143 34.905 2.413 ;
     RECT  40.215 2.143 40.305 2.413 ;
     RECT  45.615 2.143 45.705 2.413 ;
     RECT  51.015 2.143 51.105 2.413 ;
     RECT  56.415 2.143 56.505 2.413 ;
     RECT  61.815 2.143 61.905 2.413 ;
     RECT  67.215 2.143 67.305 2.413 ;
     RECT  72.615 2.143 72.705 2.413 ;
     RECT  78.015 2.143 78.105 2.413 ;
     RECT  83.415 2.143 83.505 2.413 ;
     RECT  88.815 2.143 88.905 2.413 ;
     RECT  94.215 2.143 94.305 2.413 ;
     RECT  99.615 2.143 99.705 2.413 ;
     RECT  105.015 2.143 105.105 2.413 ;
     RECT  110.415 2.143 110.505 2.413 ;
     RECT  115.815 2.143 115.905 2.413 ;
     RECT  121.215 2.143 121.305 2.413 ;
     RECT  126.615 2.143 126.705 2.413 ;
     RECT  132.015 2.143 132.105 2.413 ;
     RECT  137.415 2.143 137.505 2.413 ;
     RECT  142.815 2.143 142.905 2.413 ;
     RECT  148.215 2.143 148.305 2.413 ;
     RECT  153.615 2.143 153.705 2.413 ;
     RECT  159.015 2.143 159.105 2.413 ;
     RECT  164.415 2.143 164.505 2.413 ;
     RECT  169.815 2.143 169.905 2.413 ;
     RECT  175.215 2.143 175.305 2.413 ;
     RECT  180.615 2.143 180.705 2.413 ;
     RECT  186.015 2.143 186.105 2.413 ;
     RECT  191.415 2.143 191.505 2.413 ;
     RECT  196.815 2.143 196.905 2.413 ;
     RECT  202.215 2.143 202.305 2.413 ;
     RECT  207.615 2.143 207.705 2.413 ;
     RECT  213.015 2.143 213.105 2.413 ;
     RECT  99.615 2.413 99.897 19.471 ;
     RECT  186.015 2.413 186.297 19.471 ;
     RECT  196.815 2.413 197.097 19.471 ;
     RECT  78.015 2.413 78.297 19.483 ;
     RECT  88.815 2.413 89.097 19.507 ;
     RECT  185.904 19.471 186.297 19.517 ;
     RECT  190.26 19.471 190.278 19.517 ;
     RECT  196.704 19.471 197.097 19.517 ;
     RECT  88.596 19.507 89.097 19.565 ;
     RECT  86.652 19.483 86.67 19.613 ;
     RECT  74.844 19.579 74.862 19.679 ;
     RECT  103.104 19.483 103.122 19.769 ;
     RECT  188.712 19.471 188.73 19.769 ;
     RECT  190.476 19.768 190.494 19.805 ;
     RECT  104.22 19.741 104.238 19.853 ;
     RECT  78.015 19.483 78.642 20.011 ;
     RECT  105.015 2.413 105.297 20.011 ;
     RECT  88.704 19.565 89.097 20.048 ;
     RECT  99.504 19.471 99.897 20.048 ;
     RECT  76.068 20.047 76.086 20.083 ;
     RECT  75.996 20.083 76.086 20.141 ;
     RECT  78.015 20.011 78.678 20.141 ;
     RECT  74.736 20.047 74.754 20.147 ;
     RECT  76.068 20.141 76.086 20.147 ;
     RECT  104.796 20.011 105.297 20.299 ;
     RECT  104.796 20.299 105.93 20.309 ;
     RECT  105.015 20.309 105.93 20.345 ;
     RECT  72.615 2.413 72.897 20.587 ;
     RECT  17.352 19.507 17.37 20.857 ;
     RECT  18.615 2.413 18.897 20.857 ;
     RECT  81.504 20.875 81.522 20.921 ;
     RECT  78.015 20.141 78.297 21.001 ;
     RECT  77.724 21.001 78.297 21.101 ;
     RECT  56.415 2.413 56.697 21.397 ;
     RECT  7.815 2.413 8.097 21.433 ;
     RECT  199.188 19.543 199.206 21.433 ;
     RECT  55.548 21.397 56.697 21.437 ;
     RECT  94.215 2.413 94.497 21.451 ;
     RECT  95.472 20.191 95.49 21.451 ;
     RECT  72.615 20.587 72.99 21.461 ;
     RECT  86.184 20.731 86.202 21.461 ;
     RECT  94.215 21.451 95.49 21.631 ;
     RECT  106.56 21.928 106.578 21.965 ;
     RECT  88.815 20.048 89.097 22.072 ;
     RECT  99.615 20.048 99.897 22.072 ;
     RECT  105.015 20.345 105.297 22.072 ;
     RECT  72.615 21.461 72.954 22.081 ;
     RECT  104.904 22.072 105.297 22.109 ;
     RECT  110.415 2.413 110.697 22.165 ;
     RECT  72.504 22.081 72.954 22.171 ;
     RECT  78.015 21.101 78.297 22.171 ;
     RECT  121.215 2.413 121.497 22.171 ;
     RECT  132.015 2.413 132.297 22.171 ;
     RECT  142.815 2.413 143.097 22.171 ;
     RECT  153.615 2.413 153.897 22.171 ;
     RECT  164.415 2.413 164.697 22.171 ;
     RECT  175.215 2.413 175.497 22.171 ;
     RECT  186.015 19.517 186.297 22.171 ;
     RECT  79.92 21.979 79.938 22.199 ;
     RECT  110.304 22.165 110.697 22.205 ;
     RECT  194.364 22.027 194.382 22.205 ;
     RECT  20.304 22.171 20.322 22.207 ;
     RECT  72.18 22.171 72.954 22.208 ;
     RECT  77.904 22.171 78.297 22.208 ;
     RECT  88.704 22.072 89.097 22.208 ;
     RECT  99.504 22.072 99.897 22.208 ;
     RECT  121.104 22.171 121.497 22.208 ;
     RECT  131.904 22.171 132.297 22.208 ;
     RECT  142.704 22.171 143.097 22.208 ;
     RECT  153.504 22.171 153.897 22.208 ;
     RECT  164.304 22.171 164.697 22.208 ;
     RECT  175.104 22.171 175.497 22.208 ;
     RECT  185.904 22.171 186.297 22.208 ;
     RECT  70.74 22.081 70.758 22.235 ;
     RECT  72.18 22.208 72.897 22.343 ;
     RECT  94.215 21.631 95.634 22.441 ;
     RECT  61.815 2.413 62.097 22.477 ;
     RECT  104.22 22.441 104.238 22.493 ;
     RECT  103.104 22.459 103.122 22.505 ;
     RECT  199.188 21.433 199.242 22.513 ;
     RECT  198.108 20.821 198.126 22.549 ;
     RECT  199.188 22.513 199.278 22.549 ;
     RECT  58.788 22.477 58.806 22.577 ;
     RECT  22.896 22.477 22.914 22.621 ;
     RECT  22.824 22.621 22.914 22.649 ;
     RECT  8.82 20.083 8.838 22.711 ;
     RECT  20.304 22.207 20.862 22.783 ;
     RECT  52.092 22.711 52.11 22.883 ;
     RECT  61.815 22.477 62.19 23.161 ;
     RECT  7.452 21.433 8.097 23.251 ;
     RECT  8.82 22.711 8.874 23.251 ;
     RECT  99.615 22.208 99.897 23.251 ;
     RECT  98.208 23.161 98.226 23.287 ;
     RECT  200.7 23.251 200.718 23.287 ;
     RECT  66.096 23.251 66.114 23.309 ;
     RECT  15.084 21.937 15.102 23.323 ;
     RECT  61.815 23.161 62.73 23.351 ;
     RECT  69.336 23.251 69.354 23.357 ;
     RECT  67.215 2.413 67.497 23.521 ;
     RECT  93.708 22.441 95.634 23.521 ;
     RECT  66.168 23.521 68.058 23.597 ;
     RECT  92.988 23.521 95.634 23.597 ;
     RECT  19.764 22.783 20.862 23.629 ;
     RECT  70.668 23.563 70.686 23.629 ;
     RECT  78.015 22.208 78.297 23.701 ;
     RECT  91.44 23.701 91.458 23.741 ;
     RECT  196.815 19.517 197.097 23.755 ;
     RECT  70.416 23.629 70.686 23.791 ;
     RECT  78.015 23.701 78.678 23.791 ;
     RECT  88.815 22.208 89.097 23.791 ;
     RECT  110.415 22.205 110.697 23.791 ;
     RECT  121.215 22.208 121.497 23.791 ;
     RECT  132.015 22.208 132.297 23.791 ;
     RECT  142.815 22.208 143.097 23.791 ;
     RECT  153.615 22.208 153.897 23.791 ;
     RECT  164.415 22.208 164.697 23.791 ;
     RECT  175.215 22.208 175.497 23.791 ;
     RECT  186.015 22.208 186.297 23.791 ;
     RECT  194.364 23.755 194.382 23.803 ;
     RECT  196.704 23.755 197.097 23.819 ;
     RECT  77.904 23.791 78.678 23.837 ;
     RECT  88.704 23.791 89.097 23.837 ;
     RECT  110.304 23.791 110.697 23.837 ;
     RECT  121.104 23.791 121.497 23.837 ;
     RECT  131.904 23.791 132.297 23.837 ;
     RECT  142.704 23.791 143.097 23.837 ;
     RECT  153.504 23.791 153.897 23.837 ;
     RECT  164.304 23.791 164.697 23.837 ;
     RECT  175.104 23.791 175.497 23.837 ;
     RECT  185.904 23.791 186.297 23.837 ;
     RECT  43.956 23.701 43.974 23.863 ;
     RECT  78.015 23.837 78.678 23.863 ;
     RECT  69.084 23.851 69.102 23.891 ;
     RECT  22.824 22.649 22.842 23.899 ;
     RECT  65.124 23.791 65.142 23.927 ;
     RECT  43.704 23.863 43.974 23.933 ;
     RECT  82.476 23.863 82.494 23.933 ;
     RECT  194.364 23.803 194.49 23.933 ;
     RECT  80.604 22.747 80.622 23.935 ;
     RECT  81.36 23.791 81.378 23.935 ;
     RECT  66.168 23.597 67.914 23.936 ;
     RECT  43.956 23.933 43.974 23.999 ;
     RECT  19.656 23.629 20.862 24.097 ;
     RECT  70.2 23.791 70.686 24.097 ;
     RECT  66.708 23.936 67.914 24.125 ;
     RECT  83.415 2.413 83.697 24.133 ;
     RECT  78.015 23.863 79.254 24.161 ;
     RECT  80.604 23.935 81.378 24.187 ;
     RECT  70.2 24.097 70.722 24.197 ;
     RECT  7.452 23.251 8.874 24.205 ;
     RECT  99.324 23.251 99.897 24.205 ;
     RECT  64.728 23.935 64.746 24.233 ;
     RECT  80.604 24.187 81.738 24.233 ;
     RECT  82.836 24.133 83.697 24.269 ;
     RECT  21.96 24.133 21.978 24.331 ;
     RECT  22.824 23.899 22.986 24.331 ;
     RECT  105.015 22.109 105.297 24.427 ;
     RECT  5.94 20.047 5.958 24.439 ;
     RECT  6.696 23.791 6.714 24.439 ;
     RECT  19.656 24.097 20.934 24.475 ;
     RECT  21.96 24.331 22.986 24.475 ;
     RECT  70.2 24.197 70.686 24.475 ;
     RECT  72.615 22.343 72.897 24.475 ;
     RECT  69.84 24.475 70.686 24.601 ;
     RECT  93.708 23.597 95.634 24.601 ;
     RECT  98.028 23.287 98.226 24.601 ;
     RECT  175.215 23.837 175.497 24.601 ;
     RECT  2.415 2.413 2.697 24.619 ;
     RECT  99.324 24.205 100.062 24.619 ;
     RECT  34.815 2.413 35.097 24.637 ;
     RECT  87.012 21.901 87.03 24.637 ;
     RECT  88.815 23.837 89.097 24.637 ;
     RECT  174.492 24.601 175.497 24.637 ;
     RECT  178.776 24.601 178.794 24.637 ;
     RECT  97.56 24.601 98.226 24.653 ;
     RECT  104.328 24.427 105.297 24.701 ;
     RECT  177.228 24.637 177.246 24.709 ;
     RECT  198.108 22.549 199.278 24.709 ;
     RECT  24.015 2.413 24.297 24.715 ;
     RECT  29.415 2.413 29.697 24.715 ;
     RECT  40.215 2.413 40.497 24.715 ;
     RECT  45.615 2.413 45.897 24.715 ;
     RECT  51.015 2.413 51.297 24.715 ;
     RECT  56.415 21.437 56.697 24.715 ;
     RECT  66.708 24.125 67.497 24.715 ;
     RECT  78.015 24.161 78.75 24.737 ;
     RECT  88.815 24.637 89.154 24.737 ;
     RECT  178.704 24.637 178.794 24.737 ;
     RECT  65.016 24.667 65.034 24.745 ;
     RECT  196.815 23.819 197.097 24.745 ;
     RECT  198.108 24.709 199.35 24.745 ;
     RECT  78.015 24.737 78.714 24.763 ;
     RECT  88.815 24.737 89.097 24.763 ;
     RECT  110.415 23.837 110.697 24.763 ;
     RECT  121.215 23.837 121.497 24.763 ;
     RECT  132.015 23.837 132.297 24.763 ;
     RECT  142.815 23.837 143.097 24.763 ;
     RECT  153.615 23.837 153.897 24.763 ;
     RECT  164.415 23.837 164.697 24.763 ;
     RECT  186.015 23.837 186.297 24.763 ;
     RECT  98.028 24.653 98.226 24.781 ;
     RECT  99.108 24.619 100.062 24.781 ;
     RECT  88.704 24.763 89.097 24.809 ;
     RECT  110.304 24.763 110.697 24.809 ;
     RECT  121.104 24.763 121.497 24.809 ;
     RECT  131.904 24.763 132.297 24.809 ;
     RECT  142.704 24.763 143.097 24.809 ;
     RECT  153.504 24.763 153.897 24.809 ;
     RECT  164.304 24.763 164.697 24.809 ;
     RECT  185.904 24.763 186.297 24.809 ;
     RECT  177.048 24.709 177.246 24.811 ;
     RECT  40.215 24.715 40.698 24.871 ;
     RECT  68.22 24.619 68.238 24.871 ;
     RECT  63.9 24.859 63.918 24.899 ;
     RECT  65.016 24.745 65.106 24.899 ;
     RECT  80.604 24.233 81.45 24.899 ;
     RECT  93.6 24.601 95.634 24.899 ;
     RECT  68.22 24.871 68.598 24.907 ;
     RECT  69.336 24.601 70.686 24.907 ;
     RECT  194.364 24.763 194.382 24.907 ;
     RECT  68.22 24.907 70.686 24.935 ;
     RECT  177.048 24.811 177.39 24.935 ;
     RECT  178.704 24.737 178.722 24.941 ;
     RECT  19.656 24.475 22.986 24.943 ;
     RECT  61.815 23.351 62.097 24.943 ;
     RECT  62.892 24.907 63.018 24.943 ;
     RECT  66.204 24.715 67.497 24.943 ;
     RECT  68.22 24.935 69.21 24.943 ;
     RECT  186.015 24.809 186.297 24.943 ;
     RECT  80.208 24.907 80.226 24.944 ;
     RECT  26.784 24.715 26.802 24.955 ;
     RECT  30.78 24.715 30.798 24.955 ;
     RECT  38.772 24.715 38.79 24.955 ;
     RECT  42.768 24.715 42.786 24.955 ;
     RECT  45.615 24.715 46.782 24.955 ;
     RECT  54.72 24.715 54.738 24.955 ;
     RECT  58.716 24.715 58.734 24.955 ;
     RECT  72.36 24.475 72.897 24.955 ;
     RECT  24.015 24.715 24.498 24.989 ;
     RECT  26.784 24.955 26.91 24.989 ;
     RECT  29.415 24.715 29.898 24.989 ;
     RECT  30.78 24.955 30.906 24.989 ;
     RECT  38.772 24.955 38.898 24.989 ;
     RECT  42.768 24.955 42.894 24.989 ;
     RECT  45.615 24.955 46.89 24.989 ;
     RECT  54.72 24.955 54.846 24.989 ;
     RECT  56.415 24.715 56.898 24.989 ;
     RECT  58.716 24.955 58.842 24.989 ;
     RECT  192.492 24.871 192.51 24.989 ;
     RECT  177.048 24.935 177.318 25.003 ;
     RECT  40.215 24.871 40.842 25.007 ;
     RECT  54.828 24.989 54.846 25.015 ;
     RECT  69.948 24.935 70.686 25.015 ;
     RECT  174.42 24.637 175.497 25.015 ;
     RECT  176.688 25.003 177.318 25.015 ;
     RECT  174.42 25.015 177.318 25.037 ;
     RECT  174.528 25.037 177.318 25.043 ;
     RECT  66.204 24.943 69.21 25.079 ;
     RECT  174.528 25.043 176.166 25.079 ;
     RECT  177.3 25.043 177.318 25.079 ;
     RECT  24.015 24.989 24.39 25.085 ;
     RECT  26.892 24.989 26.91 25.085 ;
     RECT  29.415 24.989 29.79 25.085 ;
     RECT  30.888 24.989 30.906 25.085 ;
     RECT  38.88 24.989 38.898 25.085 ;
     RECT  40.215 25.007 40.59 25.085 ;
     RECT  42.876 24.989 42.894 25.085 ;
     RECT  45.615 24.989 45.99 25.085 ;
     RECT  46.8 24.989 46.89 25.085 ;
     RECT  56.415 24.989 56.79 25.085 ;
     RECT  193.716 24.907 194.382 25.099 ;
     RECT  74.664 24.709 74.682 25.141 ;
     RECT  82.98 24.269 83.697 25.141 ;
     RECT  102.132 24.439 102.15 25.141 ;
     RECT  72.36 24.955 73.314 25.147 ;
     RECT  193.176 25.099 194.382 25.147 ;
     RECT  100.8 22.477 100.818 25.169 ;
     RECT  193.176 25.147 194.49 25.169 ;
     RECT  51.015 24.715 51.498 25.177 ;
     RECT  72.108 25.147 73.314 25.177 ;
     RECT  74.664 25.141 74.754 25.177 ;
     RECT  102.132 25.141 102.366 25.177 ;
     RECT  103.14 25.003 103.158 25.177 ;
     RECT  191.415 2.413 191.697 25.177 ;
     RECT  59.652 25.177 59.994 25.195 ;
     RECT  102.132 25.177 103.158 25.213 ;
     RECT  106.452 25.177 106.47 25.213 ;
     RECT  200.7 23.287 201.222 25.213 ;
     RECT  50.472 25.177 51.498 25.229 ;
     RECT  59.652 25.195 60.066 25.229 ;
     RECT  81.36 24.899 81.45 25.229 ;
     RECT  193.248 25.169 194.49 25.229 ;
     RECT  106.452 25.213 106.686 25.24 ;
     RECT  54.828 25.015 55.566 25.243 ;
     RECT  56.415 25.085 56.697 25.243 ;
     RECT  85.284 25.141 85.302 25.249 ;
     RECT  200.124 25.213 201.222 25.249 ;
     RECT  202.215 2.413 202.497 25.249 ;
     RECT  106.02 25.24 106.686 25.285 ;
     RECT  190.404 24.907 190.422 25.285 ;
     RECT  82.62 25.141 83.697 25.291 ;
     RECT  101.988 25.213 103.266 25.291 ;
     RECT  46.8 25.085 46.818 25.313 ;
     RECT  50.796 25.229 51.498 25.313 ;
     RECT  59.976 25.229 60.066 25.313 ;
     RECT  93.6 24.899 94.986 25.313 ;
     RECT  32.4 24.403 32.418 25.321 ;
     RECT  77.904 24.763 78.714 25.321 ;
     RECT  85.068 25.249 85.302 25.321 ;
     RECT  32.4 25.321 32.706 25.411 ;
     RECT  51.015 25.313 51.498 25.411 ;
     RECT  86.652 24.637 87.03 25.411 ;
     RECT  108.324 24.379 108.342 25.411 ;
     RECT  190.404 25.285 190.494 25.411 ;
     RECT  75.924 25.321 76.626 25.435 ;
     RECT  105.015 24.701 105.297 25.435 ;
     RECT  106.02 25.285 107.226 25.435 ;
     RECT  110.376 24.809 110.697 25.439 ;
     RECT  32.4 25.411 32.778 25.447 ;
     RECT  191.415 25.177 191.862 25.469 ;
     RECT  195.264 25.411 195.354 25.469 ;
     RECT  101.844 25.291 103.266 25.475 ;
     RECT  101.844 25.475 102.366 25.511 ;
     RECT  108.324 25.411 108.882 25.511 ;
     RECT  190.404 25.411 190.566 25.511 ;
     RECT  195.336 25.469 195.354 25.511 ;
     RECT  32.148 25.447 32.778 25.517 ;
     RECT  51.015 25.411 51.678 25.517 ;
     RECT  193.716 25.229 194.49 25.517 ;
     RECT  28.296 25.411 28.314 25.531 ;
     RECT  103.14 25.475 103.266 25.547 ;
     RECT  108.324 25.511 108.702 25.547 ;
     RECT  101.844 25.511 101.934 25.555 ;
     RECT  28.044 25.531 28.314 25.583 ;
     RECT  69.948 25.015 70.938 25.583 ;
     RECT  32.688 25.517 32.778 25.591 ;
     RECT  61.815 24.943 63.018 25.591 ;
     RECT  72.108 25.177 73.746 25.591 ;
     RECT  75.6 25.435 76.626 25.591 ;
     RECT  93.6 25.313 94.77 25.591 ;
     RECT  196.815 24.745 199.35 25.591 ;
     RECT  200.124 25.249 202.497 25.591 ;
     RECT  186.015 24.943 186.462 25.613 ;
     RECT  32.688 25.591 33.138 25.619 ;
     RECT  54.828 25.243 56.697 25.619 ;
     RECT  66.672 25.079 69.21 25.619 ;
     RECT  98.028 24.781 100.062 25.661 ;
     RECT  105.015 25.435 107.226 25.661 ;
     RECT  24.015 25.085 24.297 25.667 ;
     RECT  29.415 25.085 29.697 25.667 ;
     RECT  40.215 25.085 40.497 25.667 ;
     RECT  45.615 25.085 45.897 25.667 ;
     RECT  66.672 25.619 67.497 25.667 ;
     RECT  88.815 24.809 89.097 25.667 ;
     RECT  105.015 25.661 106.614 25.667 ;
     RECT  110.415 25.439 110.697 25.667 ;
     RECT  115.815 2.413 116.097 25.667 ;
     RECT  121.215 24.809 121.497 25.667 ;
     RECT  126.615 2.413 126.897 25.667 ;
     RECT  132.015 24.809 132.297 25.667 ;
     RECT  137.415 2.413 137.697 25.667 ;
     RECT  148.215 2.413 148.497 25.667 ;
     RECT  153.615 24.809 153.897 25.667 ;
     RECT  159.015 2.413 159.297 25.667 ;
     RECT  164.415 24.809 164.697 25.667 ;
     RECT  180.615 2.413 180.897 25.667 ;
     RECT  186.015 25.613 186.297 25.667 ;
     RECT  191.415 25.469 191.697 25.667 ;
     RECT  58.788 24.989 58.842 25.672 ;
     RECT  61.815 25.591 63.774 25.672 ;
     RECT  142.815 24.809 143.097 25.672 ;
     RECT  85.068 25.321 85.338 25.675 ;
     RECT  86.544 25.411 87.03 25.675 ;
     RECT  142.815 25.672 143.19 25.675 ;
     RECT  43.56 25.579 43.578 25.681 ;
     RECT  71.892 25.591 73.746 25.681 ;
     RECT  74.664 25.177 74.826 25.681 ;
     RECT  77.724 25.321 78.714 25.681 ;
     RECT  79.812 24.979 79.83 25.681 ;
     RECT  85.068 25.675 87.03 25.681 ;
     RECT  32.76 25.619 33.138 25.709 ;
     RECT  43.56 25.681 43.866 25.709 ;
     RECT  58.788 25.672 59.202 25.709 ;
     RECT  61.815 25.672 64.026 25.709 ;
     RECT  99.432 25.661 100.062 25.709 ;
     RECT  101.16 25.555 101.934 25.709 ;
     RECT  182.268 25.435 182.286 25.709 ;
     RECT  193.716 25.517 194.454 25.709 ;
     RECT  180.615 25.667 180.738 25.715 ;
     RECT  190.116 25.675 190.134 25.715 ;
     RECT  61.815 25.709 63.774 25.717 ;
     RECT  82.62 25.291 84.078 25.717 ;
     RECT  85.068 25.681 87.102 25.717 ;
     RECT  169.815 2.413 170.097 25.717 ;
     RECT  195.804 25.681 195.822 25.717 ;
     RECT  51.015 25.517 51.426 25.745 ;
     RECT  19.656 24.943 23.094 25.753 ;
     RECT  60.408 25.717 60.426 25.753 ;
     RECT  90.648 25.141 90.666 25.753 ;
     RECT  43.848 25.709 43.866 25.757 ;
     RECT  195.804 25.717 195.894 25.757 ;
     RECT  54.828 25.619 55.566 25.789 ;
     RECT  142.815 25.675 143.334 25.805 ;
     RECT  144.72 25.681 144.738 25.805 ;
     RECT  68.328 25.619 69.21 25.816 ;
     RECT  69.948 25.583 69.966 25.816 ;
     RECT  195.876 25.757 195.894 25.817 ;
     RECT  58.788 25.709 59.022 25.825 ;
     RECT  65.52 25.213 65.79 25.825 ;
     RECT  66.672 25.667 67.305 25.825 ;
     RECT  71.892 25.681 74.826 25.825 ;
     RECT  75.6 25.591 76.986 25.825 ;
     RECT  85.068 25.717 87.174 25.825 ;
     RECT  88.815 25.667 88.905 25.825 ;
     RECT  90.648 25.753 90.738 25.825 ;
     RECT  115.815 25.667 115.905 25.825 ;
     RECT  101.232 25.709 101.934 25.853 ;
     RECT  178.416 25.717 178.434 25.853 ;
     RECT  182.34 25.717 182.358 25.853 ;
     RECT  191.415 25.667 191.682 25.853 ;
     RECT  54.036 25.717 54.054 25.861 ;
     RECT  56.415 25.619 56.697 25.861 ;
     RECT  65.52 25.825 67.305 25.861 ;
     RECT  70.704 25.583 70.938 25.861 ;
     RECT  71.892 25.825 76.986 25.861 ;
     RECT  81.432 25.229 81.45 25.861 ;
     RECT  82.62 25.717 84.114 25.861 ;
     RECT  84.96 25.825 87.174 25.861 ;
     RECT  88.272 25.825 88.905 25.861 ;
     RECT  96.912 25.285 96.93 25.861 ;
     RECT  98.028 25.661 98.586 25.861 ;
     RECT  196.815 25.591 202.497 25.861 ;
     RECT  32.76 25.709 32.778 25.889 ;
     RECT  34.815 24.637 35.766 25.889 ;
     RECT  53.964 25.861 54.054 25.889 ;
     RECT  84.96 25.861 88.905 25.889 ;
     RECT  166.464 25.717 166.554 25.889 ;
     RECT  194.364 25.709 194.454 25.889 ;
     RECT  105.984 25.667 106.614 25.901 ;
     RECT  109.62 25.771 109.638 25.912 ;
     RECT  24.015 25.667 24.105 25.937 ;
     RECT  29.415 25.667 29.505 25.937 ;
     RECT  34.815 25.889 35.514 25.937 ;
     RECT  40.215 25.667 40.305 25.937 ;
     RECT  45.615 25.667 45.705 25.937 ;
     RECT  51.015 25.745 51.354 25.937 ;
     RECT  56.415 25.861 56.934 25.937 ;
     RECT  64.944 25.861 67.305 25.937 ;
     RECT  77.724 25.681 79.83 25.937 ;
     RECT  82.584 25.861 84.114 25.937 ;
     RECT  87.732 25.889 88.905 25.937 ;
     RECT  99.432 25.709 99.705 25.937 ;
     RECT  105.015 25.667 105.174 25.937 ;
     RECT  110.415 25.667 110.505 25.937 ;
     RECT  115.704 25.825 115.905 25.937 ;
     RECT  121.215 25.667 121.305 25.937 ;
     RECT  126.615 25.667 126.705 25.937 ;
     RECT  132.015 25.667 132.105 25.937 ;
     RECT  137.415 25.667 137.505 25.937 ;
     RECT  142.815 25.805 142.905 25.937 ;
     RECT  148.215 25.667 148.305 25.937 ;
     RECT  153.615 25.667 153.705 25.937 ;
     RECT  159.015 25.667 159.105 25.937 ;
     RECT  164.415 25.667 164.505 25.937 ;
     RECT  169.815 25.717 170.478 25.937 ;
     RECT  175.215 25.079 176.166 25.937 ;
     RECT  180.615 25.715 180.705 25.937 ;
     RECT  186.015 25.667 186.105 25.937 ;
     RECT  191.415 25.853 191.505 25.937 ;
     RECT  19.656 25.753 23.13 25.951 ;
     RECT  84.024 25.937 84.114 25.979 ;
     RECT  84.96 25.889 86.562 25.979 ;
     RECT  58.608 25.825 59.022 25.997 ;
     RECT  108.072 25.861 108.09 25.997 ;
     RECT  56.664 25.937 56.934 26.015 ;
     RECT  84.06 25.979 84.114 26.015 ;
     RECT  96.48 25.861 98.586 26.015 ;
     RECT  105.156 25.937 105.174 26.045 ;
     RECT  175.572 25.937 176.166 26.045 ;
     RECT  35.496 25.937 35.514 26.051 ;
     RECT  51.336 25.937 51.354 26.051 ;
     RECT  82.584 25.937 82.926 26.051 ;
     RECT  84.096 26.015 84.114 26.051 ;
     RECT  84.96 25.979 86.346 26.051 ;
     RECT  90.648 25.825 90.774 26.051 ;
     RECT  166.464 25.889 166.482 26.051 ;
     RECT  170.064 25.937 170.478 26.051 ;
     RECT  176.148 26.045 176.166 26.051 ;
     RECT  4.428 23.593 4.446 26.059 ;
     RECT  90.648 26.051 90.702 26.087 ;
     RECT  96.912 26.015 98.586 26.093 ;
     RECT  54.792 25.789 55.566 26.107 ;
     RECT  64.944 25.937 67.194 26.141 ;
     RECT  81.432 25.861 81.486 26.141 ;
     RECT  54.756 26.107 55.566 26.159 ;
     RECT  82.584 26.051 82.746 26.159 ;
     RECT  90.684 26.087 90.702 26.159 ;
     RECT  98.568 26.093 98.586 26.159 ;
     RECT  194.364 25.889 194.382 26.159 ;
     RECT  53.964 25.889 53.982 26.189 ;
     RECT  170.064 26.051 170.082 26.189 ;
     RECT  61.596 25.717 63.774 26.204 ;
     RECT  70.704 25.861 76.986 26.204 ;
     RECT  196.668 25.861 202.497 26.221 ;
     RECT  82.584 26.159 82.602 26.237 ;
     RECT  196.668 26.221 202.59 26.237 ;
     RECT  192.492 25.825 192.51 26.381 ;
     RECT  53.028 25.861 53.046 26.474 ;
     RECT  65.628 26.141 67.194 26.477 ;
     RECT  66.888 26.477 67.194 26.525 ;
     RECT  5.94 24.439 6.714 26.527 ;
     RECT  58.608 25.997 58.95 26.555 ;
     RECT  84.96 26.051 86.31 26.555 ;
     RECT  68.328 25.816 69.966 26.573 ;
     RECT  85.716 26.555 86.31 26.591 ;
     RECT  7.452 24.205 9.414 26.599 ;
     RECT  115.704 25.937 115.722 26.627 ;
     RECT  196.668 26.237 196.722 26.627 ;
     RECT  85.716 26.591 85.734 26.663 ;
     RECT  93.492 25.591 94.77 26.663 ;
     RECT  5.508 26.527 6.714 26.671 ;
     RECT  7.452 26.599 9.63 26.671 ;
     RECT  96.912 26.093 97.614 26.699 ;
     RECT  71.028 26.204 76.986 26.744 ;
     RECT  55.548 26.159 55.566 26.789 ;
     RECT  94.032 26.663 94.77 26.789 ;
     RECT  99.432 25.937 99.45 26.789 ;
     RECT  197.568 26.237 202.59 26.797 ;
     RECT  13.215 2.413 13.497 26.923 ;
     RECT  68.364 26.573 69.966 26.957 ;
     RECT  60.408 25.753 60.678 27.053 ;
     RECT  58.932 26.555 58.95 27.059 ;
     RECT  75.852 26.744 76.986 27.095 ;
     RECT  78.624 25.937 79.83 27.095 ;
     RECT  62.1 26.204 62.19 27.101 ;
     RECT  65.628 26.477 66.15 27.131 ;
     RECT  87.732 25.937 88.362 27.131 ;
     RECT  62.172 27.101 62.19 27.149 ;
     RECT  12.24 22.513 12.258 27.175 ;
     RECT  13.104 26.923 13.497 27.175 ;
     RECT  63.144 26.204 63.774 27.197 ;
     RECT  94.032 26.789 94.698 27.203 ;
     RECT  71.028 26.744 74.646 27.239 ;
     RECT  65.628 27.131 65.718 27.245 ;
     RECT  66.888 26.525 66.906 27.284 ;
     RECT  68.832 26.957 69.966 27.293 ;
     RECT  63.144 27.197 63.162 27.329 ;
     RECT  84.96 26.555 84.978 27.341 ;
     RECT  196.668 26.627 196.686 27.341 ;
     RECT  78.624 27.095 79.758 27.373 ;
     RECT  3.996 26.059 4.446 27.643 ;
     RECT  19.656 25.951 23.31 27.751 ;
     RECT  217.08 27.715 217.926 27.751 ;
     RECT  217.08 27.751 218.178 27.841 ;
     RECT  219.564 27.643 219.582 27.913 ;
     RECT  19.62 27.751 23.31 28.08 ;
     RECT  60.408 27.053 60.426 28.08 ;
     RECT  65.7 27.245 65.718 28.08 ;
     RECT  68.832 27.293 68.85 28.08 ;
     RECT  69.876 27.293 69.966 28.08 ;
     RECT  71.028 27.239 72.522 28.08 ;
     RECT  73.62 27.239 74.646 28.08 ;
     RECT  75.852 27.095 75.87 28.08 ;
     RECT  76.608 27.095 76.986 28.08 ;
     RECT  77.724 25.937 77.742 28.08 ;
     RECT  78.552 27.373 79.758 28.08 ;
     RECT  81.432 26.141 81.45 28.08 ;
     RECT  87.732 27.131 87.75 28.08 ;
     RECT  92.304 25.861 92.322 28.08 ;
     RECT  94.032 27.203 94.194 28.08 ;
     RECT  101.916 25.853 101.934 28.08 ;
     RECT  197.568 26.797 202.698 28.08 ;
     RECT  17.352 20.857 18.897 28.111 ;
     RECT  19.62 28.08 202.698 28.111 ;
     RECT  16.596 27.715 16.614 28.123 ;
     RECT  205.092 28.021 205.11 28.183 ;
     RECT  219.564 27.913 219.618 28.183 ;
     RECT  217.08 27.841 218.286 28.255 ;
     RECT  16.56 28.123 16.614 28.291 ;
     RECT  17.352 28.111 202.698 28.291 ;
     RECT  217.008 28.255 218.286 28.291 ;
     RECT  216.576 28.291 218.286 28.381 ;
     RECT  16.56 28.291 202.698 28.409 ;
     RECT  16.56 28.409 16.614 28.493 ;
     RECT  216.216 28.381 218.286 28.561 ;
     RECT  216.072 28.561 218.286 28.651 ;
     RECT  2.415 24.619 3.15 28.789 ;
     RECT  3.996 27.643 4.554 28.789 ;
     RECT  2.415 28.789 4.554 28.795 ;
     RECT  5.508 26.671 9.63 28.795 ;
     RECT  12.24 27.175 13.497 28.795 ;
     RECT  215.496 28.651 218.286 28.831 ;
     RECT  219.456 28.183 219.618 28.831 ;
     RECT  14.508 23.323 15.102 28.859 ;
     RECT  2.415 28.795 9.63 28.939 ;
     RECT  204.876 28.183 205.11 29.191 ;
     RECT  207.615 2.413 207.897 29.227 ;
     RECT  206.748 29.263 206.766 29.299 ;
     RECT  207.615 29.227 208.422 29.299 ;
     RECT  214.164 29.101 214.182 29.299 ;
     RECT  215.028 28.831 219.618 29.299 ;
     RECT  0.144 29.263 0.162 29.323 ;
     RECT  17.352 28.409 202.698 29.335 ;
     RECT  203.76 28.759 203.778 29.335 ;
     RECT  210.456 29.299 210.474 29.335 ;
     RECT  211.896 29.299 211.914 29.335 ;
     RECT  213.015 2.413 213.297 29.335 ;
     RECT  214.164 29.299 219.618 29.335 ;
     RECT  210.456 29.335 210.978 29.351 ;
     RECT  211.86 29.335 219.618 29.357 ;
     RECT  204.876 29.191 205.362 29.371 ;
     RECT  206.748 29.299 208.422 29.371 ;
     RECT  209.376 29.263 209.394 29.371 ;
     RECT  210.312 29.351 210.978 29.371 ;
     RECT  204.876 29.371 205.542 29.489 ;
     RECT  206.748 29.371 209.394 29.489 ;
     RECT  206.748 29.489 209.25 29.525 ;
     RECT  17.352 29.335 203.778 29.605 ;
     RECT  206.748 29.525 209.214 29.641 ;
     RECT  210.312 29.371 211.122 29.803 ;
     RECT  211.86 29.357 218.322 29.837 ;
     RECT  0.108 29.323 0.162 29.899 ;
     RECT  2.415 28.939 9.702 29.911 ;
     RECT  16.596 28.493 16.614 29.911 ;
     RECT  17.352 29.605 204.138 29.911 ;
     RECT  219.456 29.357 219.618 29.933 ;
     RECT  2.415 29.911 10.206 29.995 ;
     RECT  16.596 29.911 204.138 30.029 ;
     RECT  211.86 29.837 218.25 30.029 ;
     RECT  210.168 29.803 211.122 30.037 ;
     RECT  0.108 29.899 0.558 30.137 ;
     RECT  2.376 29.995 10.206 30.139 ;
     RECT  17.352 30.029 204.138 30.181 ;
     RECT  204.876 29.489 205.47 30.181 ;
     RECT  210.168 30.037 211.626 30.209 ;
     RECT  2.376 30.139 10.638 30.271 ;
     RECT  210.168 30.209 211.374 30.569 ;
     RECT  212.4 30.029 218.25 30.613 ;
     RECT  17.352 30.181 205.47 30.649 ;
     RECT  206.316 29.641 209.214 30.649 ;
     RECT  219.456 29.933 219.582 30.763 ;
     RECT  16.596 30.029 16.614 30.811 ;
     RECT  17.352 30.649 209.214 30.811 ;
     RECT  16.596 30.811 209.214 30.941 ;
     RECT  0.108 30.137 0.126 30.946 ;
     RECT  17.352 30.941 209.214 30.955 ;
     RECT  219.456 30.763 220.05 31.003 ;
     RECT  2.376 30.271 10.926 31.051 ;
     RECT  219.42 31.003 220.05 31.085 ;
     RECT  219.42 31.085 219.438 31.144 ;
     RECT  210.312 30.569 211.374 31.189 ;
     RECT  210.312 31.189 211.482 31.225 ;
     RECT  212.4 30.613 218.286 31.225 ;
     RECT  2.34 31.051 10.926 31.261 ;
     RECT  0.108 30.946 0.162 31.339 ;
     RECT  17.352 30.955 209.25 31.351 ;
     RECT  210.312 31.225 218.286 31.351 ;
     RECT  17.352 31.351 218.286 31.435 ;
     RECT  219.384 31.144 219.438 31.435 ;
     RECT  14.58 28.859 15.102 31.495 ;
     RECT  17.352 31.435 219.438 31.559 ;
     RECT  14.58 31.495 15.21 31.649 ;
     RECT  2.304 31.261 10.926 31.765 ;
     RECT  11.664 28.795 13.497 31.765 ;
     RECT  2.304 31.765 13.497 31.819 ;
     RECT  219.348 31.559 219.438 31.819 ;
     RECT  220.176 31.531 220.23 31.819 ;
     RECT  1.152 30.187 1.17 31.955 ;
     RECT  2.268 31.819 13.497 31.963 ;
     RECT  2.268 31.963 13.59 31.997 ;
     RECT  0.108 31.339 0.342 32.045 ;
     RECT  11.412 31.997 13.59 32.071 ;
     RECT  219.348 31.819 220.23 32.333 ;
     RECT  16.596 30.941 16.614 32.341 ;
     RECT  17.352 31.559 218.286 32.341 ;
     RECT  16.596 32.341 218.286 32.369 ;
     RECT  16.596 32.369 217.962 32.459 ;
     RECT  16.596 32.459 217.926 32.477 ;
     RECT  0.108 32.045 0.162 32.495 ;
     RECT  14.58 31.649 15.102 32.611 ;
     RECT  219.348 32.333 220.194 32.779 ;
     RECT  2.268 31.997 10.638 32.881 ;
     RECT  11.412 32.071 13.698 32.881 ;
     RECT  14.508 32.611 15.102 32.881 ;
     RECT  218.844 32.779 220.194 32.909 ;
     RECT  219.348 32.909 220.194 33.163 ;
     RECT  2.268 32.881 15.102 33.179 ;
     RECT  2.34 33.179 15.102 33.305 ;
     RECT  17.352 32.477 217.926 33.341 ;
     RECT  0.108 32.495 0.126 33.451 ;
     RECT  16.596 32.477 16.614 33.691 ;
     RECT  17.352 33.341 217.818 33.691 ;
     RECT  0.108 33.451 0.162 33.835 ;
     RECT  16.596 33.691 217.818 33.881 ;
     RECT  11.664 33.305 15.102 33.917 ;
     RECT  2.376 33.305 10.818 34.027 ;
     RECT  2.304 34.027 10.818 34.087 ;
     RECT  2.304 34.087 10.89 34.123 ;
     RECT  11.664 33.917 14.31 34.157 ;
     RECT  15.084 33.917 15.102 34.159 ;
     RECT  2.196 34.123 10.89 34.187 ;
     RECT  219.348 33.163 220.23 34.219 ;
     RECT  17.352 33.881 217.818 34.231 ;
     RECT  15.084 34.159 15.426 34.253 ;
     RECT  0.108 33.835 0.198 34.315 ;
     RECT  0.108 34.315 0.558 34.492 ;
     RECT  0.108 34.492 0.594 34.541 ;
     RECT  16.596 33.881 16.614 34.619 ;
     RECT  219.132 34.219 220.23 34.619 ;
     RECT  2.196 34.187 10.494 34.655 ;
     RECT  17.352 34.231 217.854 34.655 ;
     RECT  0.108 34.541 0.342 34.733 ;
     RECT  17.352 34.655 217.818 34.795 ;
     RECT  2.304 34.655 10.494 34.969 ;
     RECT  15.084 34.253 15.102 34.987 ;
     RECT  2.304 34.969 10.854 35.068 ;
     RECT  219.132 34.619 219.15 35.179 ;
     RECT  0.108 34.733 0.162 35.195 ;
     RECT  2.304 35.068 10.89 35.213 ;
     RECT  11.664 34.157 14.022 35.213 ;
     RECT  17.1 34.795 217.818 35.437 ;
     RECT  11.664 35.213 13.698 35.465 ;
     RECT  218.844 35.179 219.15 35.563 ;
     RECT  220.032 34.619 220.23 35.563 ;
     RECT  17.1 35.437 217.962 35.609 ;
     RECT  14.832 34.987 15.102 35.779 ;
     RECT  16.344 34.735 16.362 35.941 ;
     RECT  17.1 35.609 217.854 35.941 ;
     RECT  0.108 35.195 0.126 35.947 ;
     RECT  14.832 35.779 15.282 35.969 ;
     RECT  0.108 35.947 0.342 36.077 ;
     RECT  16.344 35.941 217.854 36.239 ;
     RECT  2.304 35.213 10.854 36.391 ;
     RECT  17.352 36.239 217.854 36.625 ;
     RECT  218.844 35.563 220.23 36.689 ;
     RECT  2.304 36.391 10.89 36.787 ;
     RECT  11.664 35.465 13.497 36.787 ;
     RECT  17.352 36.625 217.962 36.851 ;
     RECT  16.344 36.239 16.542 36.893 ;
     RECT  218.844 36.689 220.194 36.907 ;
     RECT  2.304 36.787 13.497 37.133 ;
     RECT  0.108 36.077 0.126 37.387 ;
     RECT  2.304 37.133 10.242 37.579 ;
     RECT  2.268 37.579 10.242 37.625 ;
     RECT  11.412 37.133 13.497 37.675 ;
     RECT  14.832 35.969 15.102 37.769 ;
     RECT  0.108 37.387 0.162 37.771 ;
     RECT  218.808 36.907 220.194 37.867 ;
     RECT  0.108 37.771 0.342 37.901 ;
     RECT  218.772 37.867 220.194 37.931 ;
     RECT  1.368 37.867 1.386 37.997 ;
     RECT  11.412 37.675 13.698 38.129 ;
     RECT  17.352 36.851 217.89 38.129 ;
     RECT  218.808 37.931 220.194 38.141 ;
     RECT  220.14 38.141 220.194 38.251 ;
     RECT  218.808 38.141 219.402 38.273 ;
     RECT  220.14 38.251 220.23 38.471 ;
     RECT  15.084 37.769 15.102 38.479 ;
     RECT  15.084 38.479 15.318 38.669 ;
     RECT  219.276 38.273 219.402 38.669 ;
     RECT  220.212 38.471 220.23 38.741 ;
     RECT  16.344 36.893 16.362 38.821 ;
     RECT  17.352 38.129 217.782 38.821 ;
     RECT  2.304 37.625 10.242 38.923 ;
     RECT  11.664 38.129 13.698 38.939 ;
     RECT  219.276 38.669 219.294 38.939 ;
     RECT  16.344 38.821 217.782 38.975 ;
     RECT  2.268 38.923 10.242 38.983 ;
     RECT  2.268 38.983 10.818 39.047 ;
     RECT  211.464 38.975 217.782 39.055 ;
     RECT  10.8 39.047 10.818 39.119 ;
     RECT  0.108 37.901 0.126 39.149 ;
     RECT  211.464 39.055 217.854 39.181 ;
     RECT  15.084 38.669 15.21 39.389 ;
     RECT  16.344 38.975 210.726 39.551 ;
     RECT  0.144 39.403 0.558 39.587 ;
     RECT  218.88 39.289 218.898 39.595 ;
     RECT  11.664 38.939 13.59 39.659 ;
     RECT  17.1 39.551 210.726 39.721 ;
     RECT  211.464 39.181 217.89 39.721 ;
     RECT  218.844 39.595 218.898 39.721 ;
     RECT  0.144 39.587 0.234 39.725 ;
     RECT  17.1 39.721 217.89 39.785 ;
     RECT  2.268 39.047 9.666 39.787 ;
     RECT  209.412 39.785 217.89 39.787 ;
     RECT  2.232 39.787 9.666 39.929 ;
     RECT  15.084 39.389 15.102 40.063 ;
     RECT  218.844 39.721 219.474 40.205 ;
     RECT  0.144 39.725 0.162 40.459 ;
     RECT  17.1 39.785 208.674 40.531 ;
     RECT  209.412 39.787 217.962 40.531 ;
     RECT  0.144 40.459 0.342 40.555 ;
     RECT  17.1 40.531 217.962 40.559 ;
     RECT  2.268 39.929 9.666 40.595 ;
     RECT  218.844 40.205 219.438 40.829 ;
     RECT  10.836 39.901 10.854 40.837 ;
     RECT  17.352 40.559 217.962 40.873 ;
     RECT  218.844 40.829 218.898 40.873 ;
     RECT  10.836 40.837 10.926 41.009 ;
     RECT  14.832 40.063 15.102 41.009 ;
     RECT  1.152 40.939 1.17 41.035 ;
     RECT  10.764 41.107 10.818 41.279 ;
     RECT  1.152 41.035 1.206 41.323 ;
     RECT  2.304 40.595 9.666 41.341 ;
     RECT  0.108 40.555 0.342 41.357 ;
     RECT  17.352 40.873 218.898 41.357 ;
     RECT  11.664 39.659 13.497 41.369 ;
     RECT  0.108 41.357 0.162 41.405 ;
     RECT  1.152 41.323 1.242 41.419 ;
     RECT  220.212 40.939 220.23 41.515 ;
     RECT  220.176 41.515 220.23 41.611 ;
     RECT  1.152 41.419 1.386 41.675 ;
     RECT  218.772 41.357 218.898 41.707 ;
     RECT  220.14 41.611 220.23 41.707 ;
     RECT  10.8 41.279 10.818 41.819 ;
     RECT  2.304 41.341 9.702 41.945 ;
     RECT  17.352 41.357 218.034 42.187 ;
     RECT  218.772 41.707 220.23 42.187 ;
     RECT  0.144 41.405 0.162 42.215 ;
     RECT  1.188 41.675 1.386 42.287 ;
     RECT  1.224 42.287 1.386 42.323 ;
     RECT  17.352 42.187 220.23 42.449 ;
     RECT  1.296 42.323 1.386 42.485 ;
     RECT  1.296 42.485 1.314 42.593 ;
     RECT  17.352 42.449 218.898 42.749 ;
     RECT  17.352 42.749 217.818 42.899 ;
     RECT  2.34 41.945 9.702 43.169 ;
     RECT  212.328 42.899 217.818 43.259 ;
     RECT  2.34 43.169 9.63 43.267 ;
     RECT  17.352 42.899 211.482 43.325 ;
     RECT  220.14 42.449 220.23 43.435 ;
     RECT  218.592 42.749 218.898 43.613 ;
     RECT  220.032 43.435 220.23 43.757 ;
     RECT  203.4 43.325 211.482 43.843 ;
     RECT  212.364 43.259 217.818 43.843 ;
     RECT  218.592 43.613 218.862 43.843 ;
     RECT  1.728 43.267 9.63 43.949 ;
     RECT  0.108 43.645 0.126 44.105 ;
     RECT  0.54 44.107 0.558 44.203 ;
     RECT  0.54 44.203 1.17 44.213 ;
     RECT  203.4 43.843 211.626 44.221 ;
     RECT  212.364 43.843 218.862 44.221 ;
     RECT  220.14 43.757 220.23 44.411 ;
     RECT  17.352 43.325 202.59 44.443 ;
     RECT  203.4 44.221 218.862 44.443 ;
     RECT  17.352 44.443 218.862 44.491 ;
     RECT  2.304 43.949 9.63 44.645 ;
     RECT  17.352 44.491 219.438 44.909 ;
     RECT  2.34 44.645 9.63 44.915 ;
     RECT  2.376 44.915 9.63 45.059 ;
     RECT  1.152 44.213 1.17 45.185 ;
     RECT  2.415 45.059 9.63 45.301 ;
     RECT  2.415 45.301 9.918 45.419 ;
     RECT  218.844 44.909 219.438 45.451 ;
     RECT  220.176 44.411 220.23 45.451 ;
     RECT  17.352 44.909 217.962 46.139 ;
     RECT  218.844 45.451 220.23 46.139 ;
     RECT  17.352 46.139 217.818 46.499 ;
     RECT  6.012 45.419 9.918 46.651 ;
     RECT  3.924 45.419 5.202 46.741 ;
     RECT  5.94 46.651 9.918 46.741 ;
     RECT  3.924 46.741 9.918 46.769 ;
     RECT  3.996 46.769 9.918 46.805 ;
     RECT  218.556 46.603 218.646 47.077 ;
     RECT  219.384 46.139 220.23 47.077 ;
     RECT  15.084 41.009 15.102 47.119 ;
     RECT  17.352 46.499 211.554 47.281 ;
     RECT  17.352 47.281 211.59 47.323 ;
     RECT  212.4 46.499 217.818 47.323 ;
     RECT  15.084 47.119 15.174 47.419 ;
     RECT  17.352 47.323 217.818 47.425 ;
     RECT  218.556 47.077 220.23 47.425 ;
     RECT  17.352 47.425 220.23 47.501 ;
     RECT  13.215 41.369 13.497 47.551 ;
     RECT  13.104 47.551 13.497 47.597 ;
     RECT  14.832 47.419 15.174 47.597 ;
     RECT  17.352 47.501 218.646 48.119 ;
     RECT  17.352 48.119 218.574 48.659 ;
     RECT  209.628 48.659 218.574 48.859 ;
     RECT  219.384 47.501 220.23 48.859 ;
     RECT  4.068 46.805 9.918 48.973 ;
     RECT  3.96 48.973 9.918 49.037 ;
     RECT  209.628 48.859 220.23 49.505 ;
     RECT  17.352 48.659 208.854 49.549 ;
     RECT  210.096 49.505 220.23 49.711 ;
     RECT  210.096 49.711 220.302 49.777 ;
     RECT  2.415 45.419 3.15 49.855 ;
     RECT  4.068 49.037 9.918 49.855 ;
     RECT  17.352 49.549 209.25 49.883 ;
     RECT  208.872 49.883 209.25 50.009 ;
     RECT  17.352 49.883 208.134 50.669 ;
     RECT  209.052 50.009 209.25 50.779 ;
     RECT  203.364 50.669 208.134 50.791 ;
     RECT  209.052 50.779 209.358 50.791 ;
     RECT  203.364 50.791 209.466 50.863 ;
     RECT  210.204 49.777 220.302 50.863 ;
     RECT  203.364 50.863 220.302 50.963 ;
     RECT  206.82 50.963 220.302 50.999 ;
     RECT  206.928 50.999 220.302 51.008 ;
     RECT  206.964 51.008 220.302 51.125 ;
     RECT  211.176 51.125 220.302 51.161 ;
     RECT  206.964 51.125 210.438 51.233 ;
     RECT  206.964 51.233 208.566 51.269 ;
     RECT  209.484 51.233 210.438 51.359 ;
     RECT  209.772 51.359 210.438 51.503 ;
     RECT  17.352 50.669 202.59 51.511 ;
     RECT  203.364 50.963 205.974 51.511 ;
     RECT  211.464 51.161 220.302 51.539 ;
     RECT  212.616 51.539 220.302 51.629 ;
     RECT  11.664 41.369 12.258 51.665 ;
     RECT  206.964 51.269 207.897 51.737 ;
     RECT  212.652 51.629 220.302 51.737 ;
     RECT  209.772 51.503 210.366 51.809 ;
     RECT  211.464 51.539 211.662 51.899 ;
     RECT  17.352 51.511 205.974 52.015 ;
     RECT  209.772 51.809 209.79 52.079 ;
     RECT  207.18 51.737 207.897 52.141 ;
     RECT  212.652 51.737 219.15 52.169 ;
     RECT  213.015 52.169 219.15 52.349 ;
     RECT  207.18 52.141 207.954 52.411 ;
     RECT  211.644 51.899 211.662 52.439 ;
     RECT  214.128 52.349 219.15 52.475 ;
     RECT  214.452 52.475 219.15 52.547 ;
     RECT  214.452 52.547 218.862 52.709 ;
     RECT  220.068 51.737 220.302 52.709 ;
     RECT  17.352 52.015 206.442 52.745 ;
     RECT  207.18 52.411 208.53 52.789 ;
     RECT  213.015 52.349 213.39 52.817 ;
     RECT  18.615 52.745 206.442 52.825 ;
     RECT  207.18 52.789 208.854 52.825 ;
     RECT  220.176 52.709 220.302 52.853 ;
     RECT  209.988 52.861 210.006 52.951 ;
     RECT  214.884 52.709 218.862 52.979 ;
     RECT  220.284 52.853 220.302 53.123 ;
     RECT  209.772 52.951 210.006 53.329 ;
     RECT  214.884 52.979 218.178 53.357 ;
     RECT  209.772 53.329 210.15 53.401 ;
     RECT  2.415 49.855 9.918 53.491 ;
     RECT  214.884 53.357 214.902 53.519 ;
     RECT  215.64 53.357 218.178 53.519 ;
     RECT  18.615 52.825 208.854 53.563 ;
     RECT  209.772 53.401 210.222 53.563 ;
     RECT  211.608 53.491 211.626 53.563 ;
     RECT  17.352 52.745 17.37 53.861 ;
     RECT  219.456 53.761 219.474 54.031 ;
     RECT  218.88 54.031 219.474 54.103 ;
     RECT  218.88 54.103 219.51 54.337 ;
     RECT  211.608 53.563 212.022 54.409 ;
     RECT  2.304 53.491 9.918 54.445 ;
     RECT  216.396 53.519 217.854 54.445 ;
     RECT  0.18 54.067 0.198 54.481 ;
     RECT  18.615 53.563 210.222 54.481 ;
     RECT  211.572 54.409 212.022 54.481 ;
     RECT  216.396 54.445 217.89 54.481 ;
     RECT  0.18 54.481 0.846 54.607 ;
     RECT  214.668 54.481 217.89 54.643 ;
     RECT  213.015 52.817 213.297 54.679 ;
     RECT  212.94 54.679 213.297 54.751 ;
     RECT  214.272 54.643 217.89 54.751 ;
     RECT  1.728 54.445 9.918 54.797 ;
     RECT  218.88 54.337 219.546 54.797 ;
     RECT  1.764 54.797 9.918 54.893 ;
     RECT  212.94 54.751 217.89 54.913 ;
     RECT  218.88 54.797 219.474 54.913 ;
     RECT  18.615 54.481 212.022 54.949 ;
     RECT  13.215 47.597 13.497 54.985 ;
     RECT  18.615 54.949 212.094 55.021 ;
     RECT  212.94 54.913 219.474 55.021 ;
     RECT  16.344 39.551 16.362 55.049 ;
     RECT  18.615 55.021 219.474 55.181 ;
     RECT  203.22 55.181 218.286 55.211 ;
     RECT  2.304 54.893 9.918 55.283 ;
     RECT  215.424 55.211 218.286 55.409 ;
     RECT  203.22 55.211 214.29 55.445 ;
     RECT  0.108 54.607 0.846 55.757 ;
     RECT  215.46 55.409 218.286 55.76 ;
     RECT  204.588 55.445 214.29 55.859 ;
     RECT  203.292 55.445 203.526 55.985 ;
     RECT  212.508 55.859 214.29 55.993 ;
     RECT  219.42 55.181 219.474 56.011 ;
     RECT  2.376 55.283 9.918 56.065 ;
     RECT  2.34 56.065 9.918 56.101 ;
     RECT  212.508 55.993 214.47 56.101 ;
     RECT  2.304 56.101 9.918 56.219 ;
     RECT  212.508 56.101 214.722 56.227 ;
     RECT  215.46 55.76 217.854 56.227 ;
     RECT  203.292 55.985 203.49 56.255 ;
     RECT  204.588 55.859 211.734 56.255 ;
     RECT  219.384 56.011 219.474 56.395 ;
     RECT  220.212 55.243 220.23 56.395 ;
     RECT  0.18 55.757 0.846 56.525 ;
     RECT  203.22 56.371 203.238 56.525 ;
     RECT  0.18 56.525 0.234 56.539 ;
     RECT  208.656 56.255 211.734 56.605 ;
     RECT  212.508 56.227 217.854 56.605 ;
     RECT  219.384 56.395 220.23 56.759 ;
     RECT  0.144 56.539 0.234 56.779 ;
     RECT  208.656 56.605 217.854 56.779 ;
     RECT  0.108 56.779 0.234 56.867 ;
     RECT  2.304 56.219 9.666 56.875 ;
     RECT  2.268 56.875 9.666 56.911 ;
     RECT  1.728 56.911 9.666 57.053 ;
     RECT  204.588 56.255 207.897 57.065 ;
     RECT  205.488 57.065 206.73 57.137 ;
     RECT  0.216 56.867 0.234 57.293 ;
     RECT  219.42 56.759 220.23 57.407 ;
     RECT  1.728 57.053 8.262 57.451 ;
     RECT  207.504 57.065 207.897 57.451 ;
     RECT  208.656 56.779 218.286 57.451 ;
     RECT  207.504 57.451 218.286 57.479 ;
     RECT  205.488 57.137 206.586 57.569 ;
     RECT  207.504 57.479 210.042 57.569 ;
     RECT  208.944 57.569 210.042 57.581 ;
     RECT  210.924 57.479 218.286 57.592 ;
     RECT  207.504 57.569 207.897 57.605 ;
     RECT  209.196 57.581 209.79 57.839 ;
     RECT  205.488 57.569 205.866 57.875 ;
     RECT  211.464 57.592 218.286 57.875 ;
     RECT  211.464 57.875 211.482 57.947 ;
     RECT  209.664 57.839 209.79 58.013 ;
     RECT  212.544 57.875 218.286 58.019 ;
     RECT  1.332 57.451 8.262 58.081 ;
     RECT  9 57.053 9.666 58.081 ;
     RECT  212.688 58.019 218.286 58.109 ;
     RECT  212.688 58.109 213.297 58.145 ;
     RECT  1.332 58.081 9.666 58.157 ;
     RECT  214.056 58.109 218.286 58.157 ;
     RECT  214.056 58.157 214.074 58.289 ;
     RECT  220.032 57.407 220.23 58.379 ;
     RECT  2.268 58.157 9.666 58.445 ;
     RECT  18.615 55.181 202.497 58.451 ;
     RECT  1.332 58.157 1.35 58.487 ;
     RECT  0.108 57.847 0.126 58.507 ;
     RECT  220.032 58.379 220.194 58.559 ;
     RECT  209.772 58.013 209.79 58.649 ;
     RECT  214.884 58.157 218.286 58.649 ;
     RECT  220.068 58.559 220.194 58.649 ;
     RECT  2.304 58.445 9.666 58.691 ;
     RECT  15.156 47.597 15.174 58.829 ;
     RECT  21.528 58.451 202.497 58.919 ;
     RECT  216.036 58.649 218.286 58.919 ;
     RECT  18.615 58.451 20.79 58.999 ;
     RECT  18.54 58.999 20.79 59.027 ;
     RECT  0.108 58.507 0.342 59.035 ;
     RECT  0.108 59.035 0.558 59.117 ;
     RECT  216.036 58.919 218.25 59.189 ;
     RECT  2.34 58.691 9.666 59.459 ;
     RECT  216.072 59.189 218.25 59.459 ;
     RECT  2.34 59.459 8.586 59.467 ;
     RECT  10.8 58.765 10.818 59.531 ;
     RECT  220.176 58.649 220.194 59.567 ;
     RECT  20.304 59.027 20.79 59.611 ;
     RECT  21.528 58.919 201.222 59.611 ;
     RECT  0.108 59.117 0.234 59.639 ;
     RECT  1.152 59.467 8.586 59.639 ;
     RECT  216.468 59.459 218.25 59.639 ;
     RECT  20.304 59.611 201.222 59.693 ;
     RECT  9.468 59.459 9.666 59.729 ;
     RECT  216.468 59.639 218.214 59.729 ;
     RECT  216.468 59.729 217.782 59.765 ;
     RECT  0.144 59.639 0.234 59.981 ;
     RECT  216.468 59.765 217.062 59.999 ;
     RECT  18.54 59.027 19.53 60.151 ;
     RECT  20.304 59.693 20.574 60.151 ;
     RECT  215.136 58.649 215.154 60.179 ;
     RECT  18.54 60.151 20.574 60.269 ;
     RECT  21.492 59.693 201.222 60.341 ;
     RECT  19.728 60.269 20.574 60.413 ;
     RECT  1.152 59.639 8.55 60.449 ;
     RECT  15.984 60.079 16.002 60.449 ;
     RECT  9.468 59.729 9.486 60.539 ;
     RECT  19.728 60.413 19.962 60.539 ;
     RECT  19.944 60.539 19.962 60.611 ;
     RECT  1.404 60.449 8.55 60.647 ;
     RECT  1.728 60.647 8.55 60.749 ;
     RECT  0.144 59.981 0.162 60.781 ;
     RECT  207.615 57.605 207.897 60.781 ;
     RECT  2.268 60.749 8.55 60.809 ;
     RECT  209.772 60.763 209.79 60.809 ;
     RECT  0.144 60.781 0.198 60.907 ;
     RECT  207.615 60.781 208.386 61.051 ;
     RECT  207.504 61.051 208.386 61.079 ;
     RECT  207.504 61.079 207.897 61.088 ;
     RECT  10.8 61.123 10.818 61.223 ;
     RECT  12.744 54.985 13.497 61.349 ;
     RECT  9.252 61.357 9.27 61.457 ;
     RECT  18.54 60.269 18.897 61.465 ;
     RECT  0.108 60.907 0.198 61.579 ;
     RECT  18.288 61.465 18.897 61.619 ;
     RECT  0.108 61.579 0.342 61.627 ;
     RECT  2.268 60.809 8.154 61.727 ;
     RECT  18.615 61.619 18.897 62.041 ;
     RECT  18.615 62.041 19.638 62.141 ;
     RECT  21.6 60.341 201.222 62.155 ;
     RECT  0.108 61.627 0.558 62.195 ;
     RECT  21.528 62.155 201.222 62.303 ;
     RECT  11.664 51.665 11.682 62.401 ;
     RECT  11.52 62.401 11.682 62.429 ;
     RECT  18.615 62.141 19.422 62.429 ;
     RECT  11.52 62.429 11.538 62.501 ;
     RECT  2.304 61.727 8.154 62.581 ;
     RECT  2.304 62.581 8.622 62.635 ;
     RECT  21.564 62.303 201.222 62.699 ;
     RECT  0.144 62.195 0.558 62.909 ;
     RECT  2.268 62.635 8.622 63.004 ;
     RECT  21.564 62.699 199.062 63.112 ;
     RECT  20.484 63.121 20.502 63.166 ;
     RECT  21.528 63.112 199.062 63.166 ;
     RECT  0.216 62.909 0.558 63.307 ;
     RECT  2.232 63.004 8.622 63.347 ;
     RECT  2.268 63.347 8.622 63.419 ;
     RECT  20.484 63.166 199.062 63.499 ;
     RECT  199.836 62.699 201.222 63.499 ;
     RECT  2.304 63.419 8.622 63.517 ;
     RECT  10.8 63.319 10.818 63.617 ;
     RECT  19.656 63.211 19.674 63.661 ;
     RECT  20.484 63.499 201.222 63.661 ;
     RECT  2.304 63.517 9.27 63.779 ;
     RECT  0.216 63.307 1.242 63.787 ;
     RECT  2.304 63.779 8.262 63.815 ;
     RECT  9.324 63.787 9.486 63.887 ;
     RECT  2.304 63.815 8.154 64.157 ;
     RECT  9.324 63.887 9.342 64.157 ;
     RECT  18.615 62.429 18.897 64.201 ;
     RECT  19.656 63.661 201.222 64.201 ;
     RECT  2.304 64.157 8.118 64.229 ;
     RECT  10.836 64.093 10.854 64.229 ;
     RECT  18.615 64.201 201.222 64.319 ;
     RECT  0.108 63.787 1.242 65.227 ;
     RECT  0.108 65.227 1.314 65.435 ;
     RECT  0.144 65.435 1.314 65.611 ;
     RECT  2.304 64.229 8.097 65.899 ;
     RECT  2.268 65.899 8.097 66.091 ;
     RECT  2.196 66.091 8.097 66.181 ;
     RECT  8.82 65.821 8.838 66.181 ;
     RECT  2.196 66.181 8.838 66.209 ;
     RECT  2.268 66.209 8.838 66.361 ;
     RECT  0.144 65.611 1.458 66.379 ;
     RECT  19.656 64.319 201.222 66.389 ;
     RECT  0.108 66.379 1.458 68.135 ;
     RECT  19.656 66.389 201.186 68.243 ;
     RECT  0.108 68.135 0.882 68.405 ;
     RECT  14.508 64.561 14.526 68.405 ;
     RECT  22.176 68.243 201.186 68.429 ;
     RECT  22.212 68.429 201.186 68.639 ;
     RECT  0.144 68.405 0.882 68.819 ;
     RECT  0.864 68.819 0.882 69.323 ;
     RECT  2.268 66.361 9.306 69.821 ;
     RECT  22.5 68.639 201.186 69.961 ;
     RECT  2.415 69.821 9.306 70.025 ;
     RECT  3.564 70.025 9.306 79.475 ;
     RECT  3.78 79.475 9.306 83.533 ;
     RECT  3.78 83.533 9.918 84.335 ;
     RECT  9.216 84.335 9.918 85.685 ;
     RECT  3.78 84.335 8.154 93.515 ;
     RECT  14.76 68.521 14.778 96.629 ;
     RECT  21.924 69.961 201.186 98.55 ;
     RECT  19.656 68.243 20.934 99.149 ;
     RECT  67.572 98.55 68.346 99.463 ;
     RECT  67.176 99.463 68.346 99.499 ;
     RECT  9.216 85.685 9.306 99.563 ;
     RECT  20.196 99.149 20.934 99.599 ;
     RECT  69.408 99.535 69.426 99.616 ;
     RECT  86.796 98.55 86.814 99.616 ;
     RECT  73.8 99.571 73.89 99.661 ;
     RECT  83.124 98.55 83.142 99.661 ;
     RECT  20.196 99.599 20.862 99.725 ;
     RECT  3.78 93.515 6.894 99.761 ;
     RECT  67.104 99.499 68.346 100.003 ;
     RECT  3.78 99.761 6.57 100.031 ;
     RECT  197.676 98.55 201.186 100.031 ;
     RECT  58.392 98.55 58.662 100.039 ;
     RECT  67.104 100.003 68.382 100.039 ;
     RECT  69.408 99.616 69.534 100.039 ;
     RECT  67.104 100.039 69.534 100.075 ;
     RECT  20.196 99.725 20.79 100.103 ;
     RECT  73.8 99.661 74.142 100.111 ;
     RECT  86.796 99.616 87.138 100.111 ;
     RECT  20.196 100.103 20.286 100.139 ;
     RECT  73.8 100.111 74.61 100.156 ;
     RECT  7.815 93.515 8.154 100.229 ;
     RECT  20.196 100.139 20.214 100.301 ;
     RECT  70.704 100.426 70.722 100.507 ;
     RECT  86.796 100.111 87.822 100.507 ;
     RECT  39.276 99.535 39.294 100.543 ;
     RECT  64.98 100.471 64.998 100.579 ;
     RECT  66.816 100.075 69.534 100.579 ;
     RECT  70.704 100.507 70.758 100.579 ;
     RECT  83.124 99.661 83.25 100.603 ;
     RECT  70.704 100.579 70.83 100.615 ;
     RECT  73.8 100.156 75.33 100.615 ;
     RECT  21.924 98.55 22.914 100.643 ;
     RECT  34.776 100.543 34.794 100.651 ;
     RECT  70.704 100.615 71.442 100.651 ;
     RECT  34.776 100.651 34.866 100.679 ;
     RECT  34.815 100.679 34.866 100.693 ;
     RECT  39.276 100.543 39.69 100.693 ;
     RECT  55.872 98.55 55.89 100.693 ;
     RECT  72.504 98.55 72.63 100.693 ;
     RECT  78.588 100.579 78.606 100.693 ;
     RECT  86.796 100.507 88.362 100.693 ;
     RECT  99.144 99.979 99.162 100.693 ;
     RECT  197.676 100.031 200.142 100.693 ;
     RECT  84.96 100.507 84.978 100.741 ;
     RECT  101.808 100.027 101.826 100.741 ;
     RECT  105.207 100.693 105.297 100.741 ;
     RECT  58.392 100.039 59.346 100.769 ;
     RECT  63.864 100.237 63.882 100.769 ;
     RECT  64.98 100.579 65.07 100.769 ;
     RECT  66.168 100.579 69.534 100.769 ;
     RECT  70.632 100.651 71.442 100.769 ;
     RECT  72.504 100.693 72.897 100.769 ;
     RECT  73.728 100.615 75.33 100.769 ;
     RECT  80.028 100.543 80.046 100.769 ;
     RECT  80.82 100.555 80.838 100.769 ;
     RECT  81.936 100.555 81.954 100.769 ;
     RECT  83.124 100.603 83.862 100.769 ;
     RECT  84.96 100.741 85.662 100.769 ;
     RECT  86.796 100.693 89.097 100.769 ;
     RECT  99.144 100.693 99.897 100.769 ;
     RECT  100.692 100.459 100.71 100.769 ;
     RECT  101.808 100.741 102.114 100.769 ;
     RECT  103.212 100.075 103.23 100.769 ;
     RECT  106.056 100.459 106.074 100.769 ;
     RECT  108.396 100.315 108.414 100.769 ;
     RECT  54.036 99.463 54.054 100.777 ;
     RECT  59.22 100.769 59.346 100.777 ;
     RECT  62.007 100.693 62.097 100.777 ;
     RECT  104.94 100.741 105.297 100.781 ;
     RECT  33.408 98.55 33.426 100.805 ;
     RECT  39.276 100.693 40.497 100.805 ;
     RECT  58.392 100.769 58.41 100.805 ;
     RECT  59.22 100.777 59.562 100.805 ;
     RECT  73.728 100.769 74.934 100.805 ;
     RECT  76.5 100.579 76.518 100.805 ;
     RECT  86.868 100.769 87.822 100.805 ;
     RECT  39.528 100.805 40.497 100.841 ;
     RECT  74.736 100.805 74.934 100.841 ;
     RECT  98.784 100.795 98.802 100.841 ;
     RECT  108.072 100.795 108.09 100.841 ;
     RECT  54.036 100.777 54.738 100.877 ;
     RECT  59.328 100.805 59.562 100.877 ;
     RECT  70.668 100.769 70.83 100.877 ;
     RECT  102.096 100.769 102.114 100.877 ;
     RECT  26.712 99.733 26.73 100.885 ;
     RECT  197.007 100.693 200.142 100.949 ;
     RECT  24.207 100.693 24.297 100.963 ;
     RECT  29.607 100.693 29.697 100.963 ;
     RECT  45.807 100.693 45.897 100.963 ;
     RECT  51.207 100.693 51.297 100.963 ;
     RECT  62.007 100.777 62.73 100.963 ;
     RECT  78.207 100.693 78.606 100.963 ;
     RECT  94.407 100.693 94.497 100.963 ;
     RECT  110.607 100.693 110.697 100.963 ;
     RECT  116.007 100.693 116.097 100.963 ;
     RECT  121.407 100.693 121.497 100.963 ;
     RECT  126.807 100.693 126.897 100.963 ;
     RECT  132.207 100.693 132.297 100.963 ;
     RECT  137.607 100.693 137.697 100.963 ;
     RECT  143.007 100.693 143.097 100.963 ;
     RECT  148.407 100.693 148.497 100.963 ;
     RECT  153.807 100.693 153.897 100.963 ;
     RECT  159.207 100.693 159.297 100.963 ;
     RECT  164.607 100.693 164.697 100.963 ;
     RECT  170.007 100.693 170.097 100.963 ;
     RECT  175.407 100.693 175.497 100.963 ;
     RECT  180.807 100.693 180.897 100.963 ;
     RECT  186.207 100.693 186.297 100.963 ;
     RECT  191.607 100.693 191.697 100.963 ;
     RECT  197.007 100.949 197.097 100.963 ;
     RECT  26.712 100.885 26.982 101.011 ;
     RECT  72.54 100.769 72.897 101.039 ;
     RECT  73.656 100.921 73.674 101.039 ;
     RECT  74.844 100.841 74.934 101.039 ;
     RECT  26.712 101.011 27.054 101.075 ;
     RECT  55.872 100.693 56.697 101.075 ;
     RECT  198.036 100.949 200.142 101.075 ;
     RECT  83.124 100.769 83.697 101.111 ;
     RECT  27.036 101.075 27.054 101.147 ;
     RECT  21.924 100.643 22.878 101.183 ;
     RECT  85.644 100.769 85.662 101.191 ;
     RECT  22.068 101.183 22.878 101.309 ;
     RECT  78.015 100.963 78.606 101.317 ;
     RECT  69.408 100.769 69.462 101.345 ;
     RECT  198.036 101.075 199.35 101.345 ;
     RECT  80.28 101.035 80.514 101.357 ;
     RECT  65.556 101.191 65.574 101.381 ;
     RECT  87.228 100.805 87.822 101.381 ;
     RECT  82.656 101.191 82.674 101.489 ;
     RECT  42.552 101.461 42.57 101.551 ;
     RECT  78.015 101.317 78.75 101.551 ;
     RECT  88.815 100.769 89.097 101.551 ;
     RECT  99.615 100.769 99.897 101.551 ;
     RECT  110.415 100.963 110.697 101.551 ;
     RECT  121.215 100.963 121.497 101.551 ;
     RECT  132.015 100.963 132.297 101.551 ;
     RECT  142.815 100.963 143.097 101.551 ;
     RECT  153.615 100.963 153.897 101.551 ;
     RECT  164.415 100.963 164.697 101.551 ;
     RECT  175.215 100.963 175.497 101.551 ;
     RECT  186.015 100.963 186.297 101.551 ;
     RECT  45.615 100.963 45.897 101.563 ;
     RECT  22.392 101.309 22.878 101.579 ;
     RECT  42.552 101.551 42.642 101.579 ;
     RECT  66.672 100.769 68.382 101.579 ;
     RECT  88.704 101.551 89.097 101.597 ;
     RECT  99.504 101.551 99.897 101.597 ;
     RECT  110.304 101.551 110.697 101.597 ;
     RECT  121.104 101.551 121.497 101.597 ;
     RECT  131.904 101.551 132.297 101.597 ;
     RECT  142.704 101.551 143.097 101.597 ;
     RECT  153.504 101.551 153.897 101.597 ;
     RECT  164.304 101.551 164.697 101.597 ;
     RECT  175.104 101.551 175.497 101.597 ;
     RECT  185.904 101.551 186.297 101.597 ;
     RECT  81.396 101.011 81.558 101.611 ;
     RECT  5.508 100.031 6.57 101.615 ;
     RECT  45.504 101.563 45.897 101.615 ;
     RECT  56.304 101.075 56.697 101.615 ;
     RECT  198.036 101.345 199.278 101.615 ;
     RECT  80.532 101.551 80.622 101.645 ;
     RECT  38.772 101.551 38.79 101.687 ;
     RECT  42.624 101.579 42.642 101.687 ;
     RECT  22.464 101.579 22.878 101.693 ;
     RECT  30.78 101.563 30.798 101.693 ;
     RECT  61.815 100.963 62.73 101.693 ;
     RECT  74.664 101.563 74.682 101.693 ;
     RECT  78.015 101.551 79.434 101.693 ;
     RECT  194.364 101.563 194.382 101.693 ;
     RECT  80.532 101.645 80.55 101.696 ;
     RECT  22.464 101.693 22.842 101.759 ;
     RECT  198.036 101.615 199.206 101.759 ;
     RECT  3.78 100.031 4.446 101.849 ;
     RECT  51.015 100.963 51.297 101.857 ;
     RECT  52.56 100.201 52.578 101.857 ;
     RECT  67.032 101.579 68.382 101.857 ;
     RECT  81.396 101.611 81.738 101.857 ;
     RECT  82.512 101.821 82.53 101.857 ;
     RECT  3.78 101.849 3.798 101.885 ;
     RECT  81.396 101.857 82.53 101.885 ;
     RECT  200.124 101.075 200.142 101.885 ;
     RECT  54.036 100.877 54.054 101.893 ;
     RECT  85.644 101.191 85.698 101.921 ;
     RECT  67.032 101.857 68.454 101.957 ;
     RECT  78.015 101.693 78.75 101.957 ;
     RECT  81.792 101.885 81.882 101.957 ;
     RECT  70.668 100.877 70.686 102.029 ;
     RECT  78.015 101.957 78.678 102.029 ;
     RECT  81.864 101.957 81.882 102.029 ;
     RECT  69.408 101.345 69.426 102.119 ;
     RECT  22.464 101.759 22.77 102.155 ;
     RECT  22.536 102.155 22.77 102.191 ;
     RECT  51.015 101.857 52.578 102.299 ;
     RECT  87.228 101.381 87.246 102.299 ;
     RECT  67.032 101.957 68.418 102.389 ;
     RECT  198.036 101.759 199.062 102.389 ;
     RECT  67.032 102.389 67.59 102.619 ;
     RECT  22.572 102.191 22.77 102.659 ;
     RECT  54.036 101.893 54.306 102.659 ;
     RECT  68.364 102.389 68.418 102.659 ;
     RECT  54.036 102.659 54.054 102.695 ;
     RECT  22.572 102.659 22.698 102.731 ;
     RECT  22.644 102.731 22.698 102.767 ;
     RECT  59.328 100.877 59.346 102.775 ;
     RECT  68.4 102.659 68.418 102.803 ;
     RECT  66.636 102.619 67.59 102.811 ;
     RECT  22.644 102.767 22.662 102.839 ;
     RECT  59.328 102.775 59.598 102.929 ;
     RECT  66.276 102.811 67.59 102.929 ;
     RECT  198.036 102.389 198.126 102.929 ;
     RECT  59.328 102.929 59.346 102.965 ;
     RECT  45.615 101.615 45.897 103.195 ;
     RECT  6.552 101.615 6.57 103.199 ;
     RECT  66.276 102.929 66.294 103.235 ;
     RECT  82.44 103.195 82.458 103.469 ;
     RECT  45.615 103.195 46.314 103.739 ;
     RECT  5.508 101.615 5.526 103.775 ;
     RECT  198.108 102.929 198.126 104.045 ;
     RECT  85.644 101.921 85.662 104.549 ;
     RECT  52.56 102.299 52.578 104.585 ;
     RECT  79.56 104.017 79.578 104.819 ;
     RECT  9.216 99.563 9.234 104.855 ;
     RECT  207.615 61.088 207.897 108.328 ;
     RECT  209.268 108.283 209.286 108.329 ;
     RECT  207.615 108.328 208.062 108.365 ;
     RECT  201.168 100.031 201.186 111.595 ;
     RECT  200.52 111.595 201.186 111.641 ;
     RECT  199.044 102.389 199.062 111.685 ;
     RECT  199.044 111.685 199.134 111.725 ;
     RECT  201.168 111.641 201.186 113.981 ;
     RECT  199.044 111.725 199.062 117.589 ;
     RECT  198.936 117.589 199.062 117.661 ;
     RECT  198.936 117.661 199.386 117.689 ;
     RECT  204.588 57.065 204.606 117.689 ;
     RECT  199.044 117.689 199.386 119.983 ;
     RECT  205.848 57.875 205.866 120.011 ;
     RECT  199.044 119.983 199.926 120.515 ;
     RECT  199.08 120.515 199.926 121.945 ;
     RECT  199.08 121.945 200.358 121.981 ;
     RECT  199.08 121.981 200.502 122.539 ;
     RECT  2.415 70.025 2.697 122.867 ;
     RECT  7.815 100.229 8.097 122.867 ;
     RECT  13.215 61.349 13.497 122.867 ;
     RECT  18.615 64.319 18.897 122.867 ;
     RECT  24.015 100.963 24.297 122.867 ;
     RECT  29.415 100.963 29.697 122.867 ;
     RECT  34.815 100.693 35.097 122.867 ;
     RECT  40.215 100.841 40.497 122.867 ;
     RECT  45.615 103.739 45.897 122.867 ;
     RECT  51.015 102.299 51.297 122.867 ;
     RECT  56.415 101.615 56.697 122.867 ;
     RECT  61.815 101.693 62.097 122.867 ;
     RECT  67.215 102.929 67.497 122.867 ;
     RECT  72.615 101.039 72.897 122.867 ;
     RECT  78.015 102.029 78.297 122.867 ;
     RECT  83.415 101.111 83.697 122.867 ;
     RECT  88.815 101.597 89.097 122.867 ;
     RECT  94.215 100.963 94.497 122.867 ;
     RECT  99.615 101.597 99.897 122.867 ;
     RECT  105.015 100.781 105.297 122.867 ;
     RECT  110.415 101.597 110.697 122.867 ;
     RECT  115.815 100.963 116.097 122.867 ;
     RECT  121.215 101.597 121.497 122.867 ;
     RECT  126.615 100.963 126.897 122.867 ;
     RECT  132.015 101.597 132.297 122.867 ;
     RECT  137.415 100.963 137.697 122.867 ;
     RECT  142.815 101.597 143.097 122.867 ;
     RECT  148.215 100.963 148.497 122.867 ;
     RECT  153.615 101.597 153.897 122.867 ;
     RECT  159.015 100.963 159.297 122.867 ;
     RECT  164.415 101.597 164.697 122.867 ;
     RECT  169.815 100.963 170.097 122.867 ;
     RECT  175.215 101.597 175.497 122.867 ;
     RECT  180.615 100.963 180.897 122.867 ;
     RECT  186.015 101.597 186.297 122.867 ;
     RECT  191.415 100.963 191.697 122.867 ;
     RECT  196.815 100.963 197.097 122.867 ;
     RECT  202.215 58.919 202.497 122.867 ;
     RECT  207.615 108.365 207.897 122.867 ;
     RECT  213.015 58.145 213.297 122.867 ;
     RECT  198.648 122.539 200.502 122.909 ;
     RECT  198.648 122.909 199.602 122.945 ;
     RECT  199.08 122.945 199.602 122.981 ;
     RECT  199.08 122.981 199.098 123.089 ;
     RECT  200.376 122.909 200.394 123.101 ;
     RECT  2.415 122.867 2.505 123.137 ;
     RECT  7.815 122.867 7.905 123.137 ;
     RECT  13.215 122.867 13.305 123.137 ;
     RECT  18.615 122.867 18.705 123.137 ;
     RECT  24.015 122.867 24.105 123.137 ;
     RECT  29.415 122.867 29.505 123.137 ;
     RECT  34.815 122.867 34.905 123.137 ;
     RECT  40.215 122.867 40.305 123.137 ;
     RECT  45.615 122.867 45.705 123.137 ;
     RECT  51.015 122.867 51.105 123.137 ;
     RECT  56.415 122.867 56.505 123.137 ;
     RECT  61.815 122.867 61.905 123.137 ;
     RECT  67.215 122.867 67.305 123.137 ;
     RECT  72.615 122.867 72.705 123.137 ;
     RECT  78.015 122.867 78.105 123.137 ;
     RECT  83.415 122.867 83.505 123.137 ;
     RECT  88.815 122.867 88.905 123.137 ;
     RECT  94.215 122.867 94.305 123.137 ;
     RECT  99.615 122.867 99.705 123.137 ;
     RECT  105.015 122.867 105.105 123.137 ;
     RECT  110.415 122.867 110.505 123.137 ;
     RECT  115.815 122.867 115.905 123.137 ;
     RECT  121.215 122.867 121.305 123.137 ;
     RECT  126.615 122.867 126.705 123.137 ;
     RECT  132.015 122.867 132.105 123.137 ;
     RECT  137.415 122.867 137.505 123.137 ;
     RECT  142.815 122.867 142.905 123.137 ;
     RECT  148.215 122.867 148.305 123.137 ;
     RECT  153.615 122.867 153.705 123.137 ;
     RECT  159.015 122.867 159.105 123.137 ;
     RECT  164.415 122.867 164.505 123.137 ;
     RECT  169.815 122.867 169.905 123.137 ;
     RECT  175.215 122.867 175.305 123.137 ;
     RECT  180.615 122.867 180.705 123.137 ;
     RECT  186.015 122.867 186.105 123.137 ;
     RECT  191.415 122.867 191.505 123.137 ;
     RECT  196.815 122.867 196.905 123.137 ;
     RECT  202.215 122.867 202.305 123.137 ;
     RECT  207.615 122.867 207.705 123.137 ;
     RECT  213.015 122.867 213.105 123.137 ;
     RECT  199.62 125.035 199.926 125.165 ;
    LAYER M4 ;
     RECT  0.06 54.672 0.133 66.888 ;
     RECT  0.06 29.328 0.137 41.544 ;
     RECT  0.137 29.424 0.173 41.544 ;
     RECT  0.173 29.904 0.181 41.544 ;
     RECT  0.133 54.096 0.181 66.888 ;
     RECT  0.181 53.52 0.229 66.888 ;
     RECT  0.133 67.872 0.229 67.896 ;
     RECT  0.181 29.904 0.325 41.688 ;
     RECT  0.325 29.904 0.373 42.216 ;
     RECT  0.06 43.632 0.373 44.616 ;
     RECT  0.373 29.904 0.569 44.616 ;
     RECT  2.257 69.792 2.293 69.816 ;
     RECT  0.569 30 2.401 44.616 ;
     RECT  2.401 30 2.408 44.712 ;
     RECT  0.229 53.52 2.408 67.896 ;
     RECT  2.293 68.976 2.408 69.816 ;
     RECT  2.408 2.148 2.512 123.132 ;
     RECT  2.512 2.418 2.704 122.862 ;
     RECT  2.704 28.8 3.557 43.608 ;
     RECT  2.704 53.424 3.557 69.816 ;
     RECT  2.704 45.024 3.731 45.048 ;
     RECT  3.557 53.424 3.737 69.768 ;
     RECT  3.557 34.608 3.769 43.608 ;
     RECT  3.557 28.8 3.885 33.528 ;
     RECT  3.925 49.008 4.012 49.032 ;
     RECT  2.704 23.856 4.213 24.648 ;
     RECT  3.737 53.472 4.493 69.768 ;
     RECT  3.769 34.608 4.547 43.848 ;
     RECT  4.547 43.824 4.565 43.848 ;
     RECT  4.493 53.52 4.961 69.768 ;
     RECT  3.885 28.848 5.029 33.528 ;
     RECT  4.547 34.608 5.029 42.792 ;
     RECT  4.961 53.52 5.149 69.576 ;
     RECT  5.149 63.792 5.177 69.576 ;
     RECT  4.213 23.856 5.317 24.936 ;
     RECT  3.985 26.064 5.317 26.088 ;
     RECT  5.413 27.696 5.461 27.72 ;
     RECT  5.029 28.848 5.461 42.792 ;
     RECT  5.149 53.52 5.507 62.808 ;
     RECT  5.461 27.696 5.557 42.792 ;
     RECT  5.497 52.464 5.581 52.488 ;
     RECT  5.177 63.792 5.596 69 ;
     RECT  5.596 66.672 5.609 69 ;
     RECT  5.633 53.04 5.717 53.064 ;
     RECT  5.596 63.792 5.861 65.016 ;
     RECT  5.507 54.096 5.897 62.808 ;
     RECT  5.609 66.672 5.897 68.952 ;
     RECT  5.557 27.6 5.941 42.792 ;
     RECT  5.897 54.144 6.077 62.808 ;
     RECT  5.941 27.6 6.131 42.984 ;
     RECT  5.785 74.688 6.131 74.712 ;
     RECT  5.861 63.792 6.179 64.392 ;
     RECT  5.897 66.672 6.221 68.52 ;
     RECT  5.461 44.064 6.325 44.088 ;
     RECT  6.221 67.2 6.329 68.52 ;
     RECT  6.329 67.248 6.365 68.52 ;
     RECT  6.365 67.248 6.437 68.424 ;
     RECT  6.131 27.6 6.467 42.264 ;
     RECT  6.437 67.776 6.761 68.424 ;
     RECT  6.077 57.984 6.797 62.808 ;
     RECT  6.797 60.192 7.093 62.808 ;
     RECT  6.179 63.792 7.093 64.344 ;
     RECT  6.077 54.144 7.117 57 ;
     RECT  6.797 57.984 7.117 59.208 ;
     RECT  6.325 43.536 7.153 44.088 ;
     RECT  6.467 41.376 7.405 42.264 ;
     RECT  7.153 43.536 7.405 44.712 ;
     RECT  6.467 29.712 7.477 40.392 ;
     RECT  7.477 29.568 7.549 40.392 ;
     RECT  6.467 27.6 7.585 28.152 ;
     RECT  7.549 29.328 7.657 40.392 ;
     RECT  7.585 27.072 7.693 28.152 ;
     RECT  7.657 29.232 7.693 40.392 ;
     RECT  5.509 21.408 7.808 21.432 ;
     RECT  5.317 23.856 7.808 26.088 ;
     RECT  7.693 27.072 7.808 40.392 ;
     RECT  7.405 41.376 7.808 44.712 ;
     RECT  6.973 47.664 7.808 47.688 ;
     RECT  5.557 50.4 7.808 50.424 ;
     RECT  7.117 54.144 7.808 59.208 ;
     RECT  7.093 60.192 7.808 64.344 ;
     RECT  6.577 65.952 7.808 65.976 ;
     RECT  6.761 67.824 7.808 68.424 ;
     RECT  3.685 89.76 7.808 89.784 ;
     RECT  7.808 2.148 7.912 123.132 ;
     RECT  7.912 2.418 8.104 122.862 ;
     RECT  8.104 23.856 8.201 40.392 ;
     RECT  8.104 42.72 8.243 44.712 ;
     RECT  8.104 41.472 8.273 41.496 ;
     RECT  8.104 57.024 8.453 58.152 ;
     RECT  8.243 43.008 8.489 44.616 ;
     RECT  8.104 62.736 8.489 62.76 ;
     RECT  8.104 59.184 8.525 61.368 ;
     RECT  8.525 59.856 8.569 61.368 ;
     RECT  8.453 57.888 8.633 58.152 ;
     RECT  8.104 21.408 13.208 21.432 ;
     RECT  8.201 23.856 13.208 40.296 ;
     RECT  8.489 43.008 13.208 44.088 ;
     RECT  8.104 47.568 13.208 47.592 ;
     RECT  8.104 50.4 13.208 50.424 ;
     RECT  8.104 53.28 13.208 53.304 ;
     RECT  8.104 55.68 13.208 55.704 ;
     RECT  8.633 57.888 13.208 57.912 ;
     RECT  8.569 60.816 13.208 61.368 ;
     RECT  8.104 89.76 13.208 89.784 ;
     RECT  13.208 2.148 13.312 123.132 ;
     RECT  13.312 2.418 13.504 122.862 ;
     RECT  13.504 47.568 14.821 47.592 ;
     RECT  14.821 47.424 14.861 47.592 ;
     RECT  13.504 21.408 18.608 21.432 ;
     RECT  13.504 23.856 18.608 40.296 ;
     RECT  13.504 43.008 18.608 44.088 ;
     RECT  14.861 47.424 18.608 47.448 ;
     RECT  13.504 50.4 18.608 50.424 ;
     RECT  13.504 53.28 18.608 53.304 ;
     RECT  13.504 55.68 18.608 55.704 ;
     RECT  13.504 57.888 18.608 57.912 ;
     RECT  13.504 60.816 18.608 61.368 ;
     RECT  13.504 89.76 18.608 89.784 ;
     RECT  18.608 2.148 18.712 123.132 ;
     RECT  18.712 2.418 18.904 122.862 ;
     RECT  18.904 23.856 19.187 40.44 ;
     RECT  18.904 55.68 19.235 55.704 ;
     RECT  18.904 57.024 19.433 57.912 ;
     RECT  18.904 60.432 19.693 62.136 ;
     RECT  18.904 53.28 19.715 53.304 ;
     RECT  19.693 60.432 19.801 61.368 ;
     RECT  18.904 47.424 19.811 47.448 ;
     RECT  18.904 69.504 19.837 69.528 ;
     RECT  19.433 57.024 20.045 57.048 ;
     RECT  18.904 21.408 20.197 21.48 ;
     RECT  18.904 64.368 20.329 64.392 ;
     RECT  20.329 63.696 20.473 64.392 ;
     RECT  19.187 28.848 20.689 40.44 ;
     RECT  20.689 28.848 21.085 40.584 ;
     RECT  18.904 43.008 21.085 44.088 ;
     RECT  18.904 50.4 21.085 50.424 ;
     RECT  20.473 63.696 21.085 64.488 ;
     RECT  21.085 51.6 21.445 52.584 ;
     RECT  21.085 48.24 21.481 48.264 ;
     RECT  21.085 49.392 21.481 50.424 ;
     RECT  21.445 51.6 21.481 52.968 ;
     RECT  21.085 54 21.481 54.696 ;
     RECT  21.085 59.664 21.481 59.688 ;
     RECT  19.801 60.816 21.481 61.368 ;
     RECT  21.085 28.848 21.517 41.448 ;
     RECT  21.085 42.672 21.517 44.808 ;
     RECT  21.085 46.416 21.517 47.016 ;
     RECT  21.481 48.24 21.517 50.424 ;
     RECT  21.481 51.6 21.517 54.696 ;
     RECT  21.085 57.456 21.517 58.056 ;
     RECT  21.481 59.664 21.517 61.368 ;
     RECT  21.085 63.696 21.517 67.752 ;
     RECT  21.085 56.112 21.553 56.424 ;
     RECT  21.517 57.456 21.553 62.184 ;
     RECT  21.517 63.216 21.553 68.232 ;
     RECT  21.517 28.848 21.589 44.808 ;
     RECT  21.517 46.032 21.589 54.696 ;
     RECT  21.553 56.112 21.589 68.232 ;
     RECT  21.589 28.848 21.625 45 ;
     RECT  21.589 46.032 21.625 68.232 ;
     RECT  21.625 28.848 22.165 68.232 ;
     RECT  22.165 28.848 22.237 68.424 ;
     RECT  19.187 23.856 22.501 27.72 ;
     RECT  22.501 23.856 22.597 27.768 ;
     RECT  22.237 28.848 22.597 68.52 ;
     RECT  18.904 100.608 22.849 101.592 ;
     RECT  22.597 23.856 22.968 68.52 ;
     RECT  18.904 89.76 22.968 89.784 ;
     RECT  18.904 19.536 24.008 19.56 ;
     RECT  20.197 20.88 24.008 21.48 ;
     RECT  22.968 23.856 24.008 98.55 ;
     RECT  22.849 100.608 24.008 101.688 ;
     RECT  24.008 2.148 24.112 98.55 ;
     RECT  24.008 100.608 24.112 123.132 ;
     RECT  24.112 2.418 24.304 98.55 ;
     RECT  24.112 100.608 24.304 122.862 ;
     RECT  24.304 19.536 29.408 19.56 ;
     RECT  24.304 20.88 29.408 21.48 ;
     RECT  24.304 23.856 29.408 98.55 ;
     RECT  24.304 100.608 29.408 101.592 ;
     RECT  29.408 2.148 29.512 98.55 ;
     RECT  29.408 100.608 29.512 123.132 ;
     RECT  29.512 2.418 29.704 98.55 ;
     RECT  29.512 100.608 29.704 122.862 ;
     RECT  29.704 100.608 30.769 101.592 ;
     RECT  29.704 19.536 34.808 19.56 ;
     RECT  29.704 20.88 34.808 21.48 ;
     RECT  29.704 23.856 34.808 98.55 ;
     RECT  30.769 100.608 34.808 101.688 ;
     RECT  34.808 2.148 34.912 98.55 ;
     RECT  34.808 100.608 34.912 123.132 ;
     RECT  34.912 2.418 35.104 98.55 ;
     RECT  34.912 100.608 35.104 122.862 ;
     RECT  35.104 19.536 40.208 19.56 ;
     RECT  35.104 20.88 40.208 21.48 ;
     RECT  35.104 23.856 40.208 98.55 ;
     RECT  35.104 100.608 40.208 101.592 ;
     RECT  40.208 2.148 40.312 98.55 ;
     RECT  40.208 100.608 40.312 123.132 ;
     RECT  40.312 2.418 40.504 98.55 ;
     RECT  40.312 100.608 40.504 122.862 ;
     RECT  40.504 19.536 45.608 19.56 ;
     RECT  40.504 20.88 45.608 21.48 ;
     RECT  40.504 23.856 45.608 98.55 ;
     RECT  40.504 100.608 45.608 101.592 ;
     RECT  45.608 2.148 45.712 98.55 ;
     RECT  45.608 100.608 45.712 123.132 ;
     RECT  45.712 2.418 45.904 98.55 ;
     RECT  45.712 100.608 45.904 122.862 ;
     RECT  45.904 103.2 46.739 103.224 ;
     RECT  45.904 19.536 51.008 19.56 ;
     RECT  45.904 20.88 51.008 21.48 ;
     RECT  45.904 23.856 51.008 98.55 ;
     RECT  45.904 100.608 51.008 101.592 ;
     RECT  51.008 2.148 51.112 98.55 ;
     RECT  51.008 100.608 51.112 123.132 ;
     RECT  51.112 2.418 51.304 98.55 ;
     RECT  51.112 100.608 51.304 122.862 ;
     RECT  51.304 19.536 56.408 19.56 ;
     RECT  51.304 20.88 56.408 21.48 ;
     RECT  51.304 23.856 56.408 98.55 ;
     RECT  51.304 100.608 56.408 101.592 ;
     RECT  56.408 2.148 56.512 98.55 ;
     RECT  56.408 100.608 56.512 123.132 ;
     RECT  56.512 2.418 56.704 98.55 ;
     RECT  56.512 100.608 56.704 122.862 ;
     RECT  56.704 23.856 58.633 98.55 ;
     RECT  56.704 19.536 61.808 19.56 ;
     RECT  56.704 20.88 61.808 21.48 ;
     RECT  58.633 23.856 61.808 98.904 ;
     RECT  56.704 100.608 61.808 101.592 ;
     RECT  61.808 2.148 61.912 98.904 ;
     RECT  61.808 100.608 61.912 123.132 ;
     RECT  61.912 2.418 62.104 98.904 ;
     RECT  61.912 100.608 62.104 122.862 ;
     RECT  62.104 23.856 66.085 98.904 ;
     RECT  62.104 100.608 66.581 101.688 ;
     RECT  66.265 103.2 66.581 103.224 ;
     RECT  66.581 100.608 66.661 103.224 ;
     RECT  62.104 19.536 67.208 19.56 ;
     RECT  62.104 20.88 67.208 21.48 ;
     RECT  66.085 23.28 67.208 98.904 ;
     RECT  66.661 100.56 67.208 103.224 ;
     RECT  67.208 2.148 67.312 98.904 ;
     RECT  67.208 100.56 67.312 123.132 ;
     RECT  67.312 2.418 67.504 98.904 ;
     RECT  67.312 100.56 67.504 122.862 ;
     RECT  67.504 23.28 67.669 98.904 ;
     RECT  67.504 19.536 72.608 19.56 ;
     RECT  67.504 20.88 72.608 21.48 ;
     RECT  67.669 23.28 72.608 98.952 ;
     RECT  67.504 100.56 72.608 101.88 ;
     RECT  67.504 103.2 72.608 103.224 ;
     RECT  72.608 2.148 72.712 98.952 ;
     RECT  72.608 100.56 72.712 123.132 ;
     RECT  72.712 2.418 72.904 98.952 ;
     RECT  72.712 100.56 72.904 122.862 ;
     RECT  72.904 100.56 74.365 101.88 ;
     RECT  72.904 19.536 74.833 19.56 ;
     RECT  74.833 19.536 75.985 19.608 ;
     RECT  72.904 20.88 75.985 22.2 ;
     RECT  75.985 19.536 77.893 22.2 ;
     RECT  72.904 23.28 77.893 98.952 ;
     RECT  77.893 19.536 78.008 98.952 ;
     RECT  74.365 100.464 78.008 101.88 ;
     RECT  72.904 103.2 78.008 103.224 ;
     RECT  78.008 2.148 78.112 98.952 ;
     RECT  78.008 100.464 78.112 123.132 ;
     RECT  78.112 2.418 78.304 98.952 ;
     RECT  78.112 100.464 78.304 122.862 ;
     RECT  78.304 100.464 81.425 101.88 ;
     RECT  78.304 19.488 81.533 98.952 ;
     RECT  81.425 100.464 82.501 101.688 ;
     RECT  81.533 19.488 83.408 20.04 ;
     RECT  81.533 21.408 83.408 98.952 ;
     RECT  82.501 100.464 83.408 101.88 ;
     RECT  78.304 103.2 83.408 103.224 ;
     RECT  83.408 2.148 83.512 98.952 ;
     RECT  83.408 100.464 83.512 123.132 ;
     RECT  83.512 2.418 83.704 98.952 ;
     RECT  83.512 100.464 83.704 122.862 ;
     RECT  83.704 19.488 86.681 20.04 ;
     RECT  86.681 19.536 88.808 20.04 ;
     RECT  83.704 21.408 88.808 98.952 ;
     RECT  83.704 100.464 88.808 101.88 ;
     RECT  83.704 103.488 88.808 103.512 ;
     RECT  88.808 2.148 88.912 98.952 ;
     RECT  88.808 100.464 88.912 123.132 ;
     RECT  88.912 2.418 89.104 98.952 ;
     RECT  88.912 100.464 89.104 122.862 ;
     RECT  89.104 19.488 94.208 20.04 ;
     RECT  89.104 21.408 94.208 98.952 ;
     RECT  89.104 100.464 94.208 101.88 ;
     RECT  89.104 103.488 94.208 103.512 ;
     RECT  94.208 2.148 94.312 98.952 ;
     RECT  94.208 100.464 94.312 123.132 ;
     RECT  94.312 2.418 94.504 98.952 ;
     RECT  94.312 100.464 94.504 122.862 ;
     RECT  94.504 100.464 99.133 101.88 ;
     RECT  94.504 19.488 99.608 20.04 ;
     RECT  94.504 21.408 99.608 98.952 ;
     RECT  99.133 99.984 99.608 101.88 ;
     RECT  94.504 103.488 99.608 103.512 ;
     RECT  99.608 2.148 99.712 98.952 ;
     RECT  99.608 99.984 99.712 123.132 ;
     RECT  99.712 2.418 99.904 98.952 ;
     RECT  99.712 99.984 99.904 122.862 ;
     RECT  99.904 19.488 103.133 20.04 ;
     RECT  99.904 21.408 103.133 98.952 ;
     RECT  103.133 20.016 104.209 20.04 ;
     RECT  103.133 21.408 104.209 22.2 ;
     RECT  103.133 23.28 104.209 98.952 ;
     RECT  104.209 19.824 105.008 20.04 ;
     RECT  104.209 21.408 105.008 98.952 ;
     RECT  99.904 99.984 105.008 101.88 ;
     RECT  99.904 103.488 105.008 103.512 ;
     RECT  105.008 2.148 105.112 98.952 ;
     RECT  105.008 99.984 105.112 123.132 ;
     RECT  105.112 2.418 105.304 98.952 ;
     RECT  105.112 99.984 105.304 122.862 ;
     RECT  105.304 19.824 110.408 20.328 ;
     RECT  105.304 21.408 110.408 98.952 ;
     RECT  105.304 99.984 110.408 101.88 ;
     RECT  105.304 103.488 110.408 103.512 ;
     RECT  110.408 2.148 110.512 98.952 ;
     RECT  110.408 99.984 110.512 123.132 ;
     RECT  110.512 2.418 110.704 98.952 ;
     RECT  110.512 99.984 110.704 122.862 ;
     RECT  110.704 19.824 115.808 20.328 ;
     RECT  110.704 21.408 115.808 98.952 ;
     RECT  110.704 99.984 115.808 101.88 ;
     RECT  110.704 103.488 115.808 103.512 ;
     RECT  115.808 2.148 115.912 98.952 ;
     RECT  115.808 99.984 115.912 123.132 ;
     RECT  115.912 2.418 116.104 98.952 ;
     RECT  115.912 99.984 116.104 122.862 ;
     RECT  116.104 19.824 121.208 20.328 ;
     RECT  116.104 21.408 121.208 98.952 ;
     RECT  116.104 99.984 121.208 101.88 ;
     RECT  116.104 103.488 121.208 103.512 ;
     RECT  121.208 2.148 121.312 98.952 ;
     RECT  121.208 99.984 121.312 123.132 ;
     RECT  121.312 2.418 121.504 98.952 ;
     RECT  121.312 99.984 121.504 122.862 ;
     RECT  121.504 19.824 126.608 20.328 ;
     RECT  121.504 21.408 126.608 98.952 ;
     RECT  121.504 99.984 126.608 101.88 ;
     RECT  121.504 103.488 126.608 103.512 ;
     RECT  126.608 2.148 126.712 98.952 ;
     RECT  126.608 99.984 126.712 123.132 ;
     RECT  126.712 2.418 126.904 98.952 ;
     RECT  126.712 99.984 126.904 122.862 ;
     RECT  126.904 19.824 132.008 20.328 ;
     RECT  126.904 21.408 132.008 98.952 ;
     RECT  126.904 99.984 132.008 101.88 ;
     RECT  126.904 103.488 132.008 103.512 ;
     RECT  132.008 2.148 132.112 98.952 ;
     RECT  132.008 99.984 132.112 123.132 ;
     RECT  132.112 2.418 132.304 98.952 ;
     RECT  132.112 99.984 132.304 122.862 ;
     RECT  132.304 19.824 137.408 20.328 ;
     RECT  132.304 21.408 137.408 98.952 ;
     RECT  132.304 99.984 137.408 101.88 ;
     RECT  132.304 103.488 137.408 103.512 ;
     RECT  137.408 2.148 137.512 98.952 ;
     RECT  137.408 99.984 137.512 123.132 ;
     RECT  137.512 2.418 137.704 98.952 ;
     RECT  137.512 99.984 137.704 122.862 ;
     RECT  137.704 19.824 142.808 20.328 ;
     RECT  137.704 21.408 142.808 98.952 ;
     RECT  137.704 99.984 142.808 101.88 ;
     RECT  137.704 103.488 142.808 103.512 ;
     RECT  142.808 2.148 142.912 98.952 ;
     RECT  142.808 99.984 142.912 123.132 ;
     RECT  142.912 2.418 143.104 98.952 ;
     RECT  142.912 99.984 143.104 122.862 ;
     RECT  143.104 19.824 148.208 20.328 ;
     RECT  143.104 21.408 148.208 98.952 ;
     RECT  143.104 99.984 148.208 101.88 ;
     RECT  143.104 103.488 148.208 103.512 ;
     RECT  148.208 2.148 148.312 98.952 ;
     RECT  148.208 99.984 148.312 123.132 ;
     RECT  148.312 2.418 148.504 98.952 ;
     RECT  148.312 99.984 148.504 122.862 ;
     RECT  148.504 19.824 153.608 20.328 ;
     RECT  148.504 21.408 153.608 98.952 ;
     RECT  148.504 99.984 153.608 101.88 ;
     RECT  148.504 103.488 153.608 103.512 ;
     RECT  153.608 2.148 153.712 98.952 ;
     RECT  153.608 99.984 153.712 123.132 ;
     RECT  153.712 2.418 153.904 98.952 ;
     RECT  153.712 99.984 153.904 122.862 ;
     RECT  153.904 19.824 159.008 20.328 ;
     RECT  153.904 21.408 159.008 98.952 ;
     RECT  153.904 99.984 159.008 101.88 ;
     RECT  153.904 103.488 159.008 103.512 ;
     RECT  159.008 2.148 159.112 98.952 ;
     RECT  159.008 99.984 159.112 123.132 ;
     RECT  159.112 2.418 159.304 98.952 ;
     RECT  159.112 99.984 159.304 122.862 ;
     RECT  159.304 19.824 164.408 20.328 ;
     RECT  159.304 21.408 164.408 98.952 ;
     RECT  159.304 99.984 164.408 101.88 ;
     RECT  159.304 103.488 164.408 103.512 ;
     RECT  164.408 2.148 164.512 98.952 ;
     RECT  164.408 99.984 164.512 123.132 ;
     RECT  164.512 2.418 164.704 98.952 ;
     RECT  164.512 99.984 164.704 122.862 ;
     RECT  164.704 19.824 169.808 20.328 ;
     RECT  164.704 21.408 169.808 98.952 ;
     RECT  164.704 99.984 169.808 101.88 ;
     RECT  164.704 103.488 169.808 103.512 ;
     RECT  169.808 2.148 169.912 98.952 ;
     RECT  169.808 99.984 169.912 123.132 ;
     RECT  169.912 2.418 170.104 98.952 ;
     RECT  169.912 99.984 170.104 122.862 ;
     RECT  170.104 19.824 175.208 20.328 ;
     RECT  170.104 21.408 175.208 98.952 ;
     RECT  170.104 99.984 175.208 101.88 ;
     RECT  170.104 103.488 175.208 103.512 ;
     RECT  175.208 2.148 175.312 98.952 ;
     RECT  175.208 99.984 175.312 123.132 ;
     RECT  175.312 2.418 175.504 98.952 ;
     RECT  175.312 99.984 175.504 122.862 ;
     RECT  175.504 19.824 180.608 20.328 ;
     RECT  175.504 21.408 180.608 98.952 ;
     RECT  175.504 99.984 180.608 101.88 ;
     RECT  175.504 103.488 180.608 103.512 ;
     RECT  180.608 2.148 180.712 98.952 ;
     RECT  180.608 99.984 180.712 123.132 ;
     RECT  180.712 2.418 180.904 98.952 ;
     RECT  180.712 99.984 180.904 122.862 ;
     RECT  180.904 19.824 182.293 20.328 ;
     RECT  182.293 19.488 186.008 20.328 ;
     RECT  180.904 21.408 186.008 98.952 ;
     RECT  180.904 99.984 186.008 101.88 ;
     RECT  180.904 103.488 186.008 103.512 ;
     RECT  186.008 2.148 186.112 98.952 ;
     RECT  186.008 99.984 186.112 123.132 ;
     RECT  186.112 2.418 186.304 98.952 ;
     RECT  186.112 99.984 186.304 122.862 ;
     RECT  186.304 19.488 188.741 20.328 ;
     RECT  188.741 19.824 190.249 20.328 ;
     RECT  190.249 19.488 191.408 20.328 ;
     RECT  186.304 21.408 191.408 98.952 ;
     RECT  186.304 99.984 191.408 101.88 ;
     RECT  186.304 103.488 191.408 103.512 ;
     RECT  191.408 2.148 191.512 98.952 ;
     RECT  191.408 99.984 191.512 123.132 ;
     RECT  191.512 2.418 191.704 98.952 ;
     RECT  191.512 99.984 191.704 122.862 ;
     RECT  191.704 19.488 196.808 20.328 ;
     RECT  191.704 21.408 196.808 98.952 ;
     RECT  191.704 99.984 196.808 101.88 ;
     RECT  191.704 103.488 196.808 103.512 ;
     RECT  196.808 2.148 196.912 98.952 ;
     RECT  196.808 99.984 196.912 123.132 ;
     RECT  196.912 2.418 197.104 98.952 ;
     RECT  196.912 99.984 197.104 122.862 ;
     RECT  197.104 21.408 197.568 98.952 ;
     RECT  197.104 103.488 197.747 103.512 ;
     RECT  197.104 99.984 197.795 101.88 ;
     RECT  197.795 99.984 198.035 101.688 ;
     RECT  198.035 100.032 198.179 101.688 ;
     RECT  198.179 100.08 198.323 101.688 ;
     RECT  197.568 98.88 198.371 98.952 ;
     RECT  197.104 19.488 198.611 20.328 ;
     RECT  198.637 122.544 198.721 122.568 ;
     RECT  198.323 100.08 198.755 100.824 ;
     RECT  197.568 21.408 198.803 69.48 ;
     RECT  198.755 100.8 199.043 100.824 ;
     RECT  198.803 21.408 199.139 22.488 ;
     RECT  198.997 111.696 199.145 111.72 ;
     RECT  198.803 23.616 199.235 69.48 ;
     RECT  199.237 122.496 199.325 122.52 ;
     RECT  199.333 92.256 199.429 92.28 ;
     RECT  199.235 23.808 199.505 69.48 ;
     RECT  199.505 23.808 199.523 65.832 ;
     RECT  199.429 92.256 199.525 92.328 ;
     RECT  198.997 125.136 199.525 125.16 ;
     RECT  199.523 24.192 199.571 65.832 ;
     RECT  199.505 67.296 199.613 69.48 ;
     RECT  199.525 92.256 199.669 93.096 ;
     RECT  199.613 67.296 199.685 68.616 ;
     RECT  199.571 24.432 199.763 65.832 ;
     RECT  198.371 98.88 199.811 98.904 ;
     RECT  197.568 71.328 199.825 71.352 ;
     RECT  197.568 83.472 199.853 83.496 ;
     RECT  199.825 70.656 199.861 71.352 ;
     RECT  199.825 98.016 199.861 98.04 ;
     RECT  199.861 70.224 199.865 71.352 ;
     RECT  199.853 83.472 199.865 84.408 ;
     RECT  199.865 84 199.937 84.408 ;
     RECT  199.685 67.296 199.973 68.376 ;
     RECT  199.763 24.912 200.009 65.832 ;
     RECT  199.865 70.224 200.051 70.68 ;
     RECT  199.861 97.776 200.051 98.04 ;
     RECT  199.525 124.944 200.051 125.16 ;
     RECT  200.009 24.912 200.081 65.16 ;
     RECT  200.081 24.912 200.117 64.968 ;
     RECT  200.117 24.912 200.153 63.096 ;
     RECT  200.117 64.128 200.189 64.968 ;
     RECT  199.669 91.776 200.189 93.096 ;
     RECT  200.153 56.88 200.195 63.096 ;
     RECT  200.051 70.224 200.225 70.248 ;
     RECT  199.937 84 200.225 84.024 ;
     RECT  200.051 97.776 200.225 97.8 ;
     RECT  200.06 90.576 200.245 90.6 ;
     RECT  200.245 90.576 200.252 90.648 ;
     RECT  200.189 91.776 200.252 92.952 ;
     RECT  200.189 64.176 200.261 64.968 ;
     RECT  199.973 67.92 200.261 67.944 ;
     RECT  200.252 90.576 200.293 92.952 ;
     RECT  200.195 56.88 200.333 57.72 ;
     RECT  200.195 58.704 200.333 63.096 ;
     RECT  200.261 64.944 200.333 64.968 ;
     RECT  200.153 24.912 200.339 55.848 ;
     RECT  200.293 90.048 200.339 92.952 ;
     RECT  200.051 124.992 200.339 125.16 ;
     RECT  199.861 122.64 200.365 122.664 ;
     RECT  200.339 24.912 200.369 55.656 ;
     RECT  200.333 58.896 200.369 63.096 ;
     RECT  200.339 90.048 200.377 90.648 ;
     RECT  200.369 28.752 200.387 55.656 ;
     RECT  200.333 57.024 200.387 57.72 ;
     RECT  200.369 58.896 200.387 63.048 ;
     RECT  200.365 122.64 200.389 123.096 ;
     RECT  200.387 57.12 200.405 57.72 ;
     RECT  200.339 91.776 200.435 92.952 ;
     RECT  200.389 122.064 200.435 123.096 ;
     RECT  200.339 125.136 200.435 125.16 ;
     RECT  200.435 123.072 200.449 123.096 ;
     RECT  200.435 122.064 200.476 122.088 ;
     RECT  200.377 90.624 200.477 90.648 ;
     RECT  200.435 91.776 200.485 92.424 ;
     RECT  200.405 57.168 200.513 57.72 ;
     RECT  200.387 60.144 200.549 63.048 ;
     RECT  200.005 111.6 200.549 111.624 ;
     RECT  200.549 60.144 200.579 61.704 ;
     RECT  200.485 92.4 200.579 92.424 ;
     RECT  200.387 58.896 200.657 59.112 ;
     RECT  199.139 21.936 200.675 22.488 ;
     RECT  200.513 57.168 200.675 57.192 ;
     RECT  200.579 61.056 200.723 61.704 ;
     RECT  200.675 22.464 200.771 22.488 ;
     RECT  198.611 19.488 200.819 19.848 ;
     RECT  200.369 24.912 200.873 27.72 ;
     RECT  200.657 59.088 201.053 59.112 ;
     RECT  200.549 63.024 201.155 63.048 ;
     RECT  199.957 113.952 201.197 113.976 ;
     RECT  200.873 27.696 201.203 27.72 ;
     RECT  200.387 28.848 201.373 55.656 ;
     RECT  200.723 61.056 202.069 61.08 ;
     RECT  200.819 19.488 202.208 19.512 ;
     RECT  200.873 24.912 202.208 26.376 ;
     RECT  201.373 28.464 202.208 55.656 ;
     RECT  202.069 60.816 202.208 61.08 ;
     RECT  200.389 108.336 202.208 108.36 ;
     RECT  202.208 2.148 202.312 123.132 ;
     RECT  202.312 2.418 202.504 122.862 ;
     RECT  202.504 29.232 202.637 55.176 ;
     RECT  202.637 29.232 202.997 55.032 ;
     RECT  202.997 31.392 203.069 55.032 ;
     RECT  203.069 31.488 203.573 55.032 ;
     RECT  203.573 31.68 203.609 45 ;
     RECT  203.609 31.728 203.897 45 ;
     RECT  203.897 31.728 204.041 36.12 ;
     RECT  203.573 46.032 204.041 55.032 ;
     RECT  203.897 38.016 204.113 45 ;
     RECT  204.041 31.728 204.221 36.072 ;
     RECT  204.113 38.016 204.221 42.024 ;
     RECT  204.221 33.552 204.227 36.072 ;
     RECT  204.221 31.728 204.293 32.568 ;
     RECT  204.227 33.648 204.293 36.072 ;
     RECT  204.221 38.112 204.323 42.024 ;
     RECT  204.041 46.032 204.473 49.608 ;
     RECT  204.113 43.536 204.577 45 ;
     RECT  204.473 46.032 204.577 48.936 ;
     RECT  204.323 40.608 204.617 42.024 ;
     RECT  204.293 31.728 204.653 31.896 ;
     RECT  204.577 43.536 204.653 48.936 ;
     RECT  204.041 50.688 204.653 55.032 ;
     RECT  204.293 34.032 204.761 36.072 ;
     RECT  204.323 38.112 204.761 39.624 ;
     RECT  204.653 43.584 204.761 48.936 ;
     RECT  204.761 43.584 204.833 48.264 ;
     RECT  204.653 50.688 204.899 53.688 ;
     RECT  204.761 36.048 205.049 36.072 ;
     RECT  204.617 40.944 205.081 42.024 ;
     RECT  204.653 31.824 205.157 31.896 ;
     RECT  205.081 40.944 205.193 42.552 ;
     RECT  204.899 50.784 205.193 53.688 ;
     RECT  204.833 44.304 205.229 48.264 ;
     RECT  205.229 44.304 205.265 46.056 ;
     RECT  205.193 50.784 205.265 53.592 ;
     RECT  204.761 38.112 205.373 38.136 ;
     RECT  205.265 44.88 205.373 46.056 ;
     RECT  204.761 39.12 205.409 39.624 ;
     RECT  205.193 40.944 205.445 41.976 ;
     RECT  204.761 34.032 205.621 34.968 ;
     RECT  205.621 33.216 205.765 34.968 ;
     RECT  205.409 39.6 205.765 39.624 ;
     RECT  205.729 40.8 205.765 40.824 ;
     RECT  205.265 50.784 205.769 51.336 ;
     RECT  205.765 39.6 205.811 40.824 ;
     RECT  205.265 52.56 205.913 53.592 ;
     RECT  204.653 55.008 205.945 55.032 ;
     RECT  205.769 50.976 205.949 51.336 ;
     RECT  205.913 52.992 205.985 53.592 ;
     RECT  205.157 31.872 206.021 31.896 ;
     RECT  205.445 41.952 206.161 41.976 ;
     RECT  205.229 47.04 206.245 48.264 ;
     RECT  205.373 44.88 206.273 45.816 ;
     RECT  202.504 24.912 206.291 26.376 ;
     RECT  205.801 36.768 206.305 36.792 ;
     RECT  206.305 36.48 206.341 36.792 ;
     RECT  205.765 38.016 206.345 38.04 ;
     RECT  205.945 55.008 206.417 55.848 ;
     RECT  202.997 29.232 206.449 29.688 ;
     RECT  206.273 45.456 206.485 45.816 ;
     RECT  206.245 47.04 206.485 48.504 ;
     RECT  206.377 32.16 206.489 32.184 ;
     RECT  205.765 33.216 206.557 35.448 ;
     RECT  206.341 36.48 206.557 36.888 ;
     RECT  206.557 33.216 206.593 36.888 ;
     RECT  206.485 45.456 206.629 48.504 ;
     RECT  206.161 41.952 206.701 42.696 ;
     RECT  205.949 50.976 206.732 51 ;
     RECT  206.417 55.008 206.808 55.608 ;
     RECT  205.811 40.464 206.917 40.824 ;
     RECT  206.593 33.216 207.025 37.656 ;
     RECT  206.449 29.232 207.061 30.168 ;
     RECT  206.809 43.824 207.061 43.848 ;
     RECT  206.917 40.464 207.097 40.92 ;
     RECT  207.097 40.08 207.241 40.92 ;
     RECT  207.025 32.736 207.385 37.656 ;
     RECT  207.061 43.824 207.385 44.472 ;
     RECT  206.629 45.456 207.385 48.744 ;
     RECT  207.385 43.824 207.493 48.744 ;
     RECT  206.732 50.112 207.493 51 ;
     RECT  206.701 41.952 207.601 42.792 ;
     RECT  206.291 24.912 207.608 25.224 ;
     RECT  206.291 26.352 207.608 26.376 ;
     RECT  207.061 29.232 207.608 31.128 ;
     RECT  207.385 32.736 207.608 38.472 ;
     RECT  207.241 40.032 207.608 40.92 ;
     RECT  207.601 41.904 207.608 42.792 ;
     RECT  207.493 43.824 207.608 51 ;
     RECT  205.985 52.992 207.608 53.016 ;
     RECT  206.808 54.672 207.608 55.608 ;
     RECT  205.621 56.976 207.608 57 ;
     RECT  202.504 60.816 207.608 61.08 ;
     RECT  202.504 108.336 207.608 108.36 ;
     RECT  207.608 2.148 207.712 123.132 ;
     RECT  207.712 2.418 207.904 122.862 ;
     RECT  207.904 43.776 207.965 48.504 ;
     RECT  207.904 50.784 207.965 50.952 ;
     RECT  207.965 46.368 208.019 48.504 ;
     RECT  207.904 29.232 208.037 34.2 ;
     RECT  207.904 41.904 208.037 42.312 ;
     RECT  207.904 108.336 208.073 108.36 ;
     RECT  208.037 42.048 208.109 42.312 ;
     RECT  208.109 42.048 208.145 42.216 ;
     RECT  208.145 42.144 208.181 42.216 ;
     RECT  208.019 46.512 208.217 48.504 ;
     RECT  207.904 39.744 208.322 40.92 ;
     RECT  207.904 35.328 208.325 38.472 ;
     RECT  207.904 60.816 208.397 61.032 ;
     RECT  208.037 29.232 208.433 29.4 ;
     RECT  207.904 49.488 208.685 49.512 ;
     RECT  207.965 43.776 208.793 45.192 ;
     RECT  208.433 29.376 208.883 29.4 ;
     RECT  208.325 35.328 209.045 38.232 ;
     RECT  207.965 50.784 209.077 50.856 ;
     RECT  208.037 31.104 209.149 34.2 ;
     RECT  209.149 31.104 209.221 34.248 ;
     RECT  208.181 42.144 209.221 42.168 ;
     RECT  209.077 45.504 209.269 45.528 ;
     RECT  208.217 46.512 209.269 48.456 ;
     RECT  209.257 108.288 209.341 108.312 ;
     RECT  209.077 50.784 209.369 50.952 ;
     RECT  207.904 26.352 209.459 26.376 ;
     RECT  209.221 42.144 209.473 42.744 ;
     RECT  208.793 43.776 209.473 44.472 ;
     RECT  209.369 50.832 209.477 50.952 ;
     RECT  209.045 35.328 209.507 37.128 ;
     RECT  209.507 35.328 209.513 35.832 ;
     RECT  208.322 39.744 209.581 40.872 ;
     RECT  208.933 57.552 209.612 57.576 ;
     RECT  209.269 45.504 209.617 48.456 ;
     RECT  208.397 61.008 209.653 61.032 ;
     RECT  209.612 57.552 209.699 58.008 ;
     RECT  209.653 60.768 209.699 61.032 ;
     RECT  209.413 29.232 209.747 29.352 ;
     RECT  209.617 45.504 209.797 48.744 ;
     RECT  209.077 49.776 209.797 49.8 ;
     RECT  207.904 55.248 209.797 55.272 ;
     RECT  208.933 56.496 209.797 56.52 ;
     RECT  209.699 60.768 209.801 60.792 ;
     RECT  209.473 41.904 209.869 44.472 ;
     RECT  209.797 45.504 209.869 49.8 ;
     RECT  209.797 55.248 209.873 56.52 ;
     RECT  209.873 55.248 209.881 55.896 ;
     RECT  209.869 41.904 210.017 49.8 ;
     RECT  207.904 24.912 210.035 25.224 ;
     RECT  209.581 39.744 210.121 40.92 ;
     RECT  210.017 41.904 210.121 43.944 ;
     RECT  209.045 38.208 210.188 38.232 ;
     RECT  209.221 30.96 210.193 34.248 ;
     RECT  209.513 35.328 210.193 35.496 ;
     RECT  210.035 25.2 210.275 25.224 ;
     RECT  210.188 38.208 210.275 38.664 ;
     RECT  210.121 39.744 210.277 43.944 ;
     RECT  209.747 29.328 210.301 29.352 ;
     RECT  210.193 30.96 210.305 35.496 ;
     RECT  209.507 36.864 210.337 37.128 ;
     RECT  210.275 38.208 210.337 38.232 ;
     RECT  210.305 30.96 210.341 31.848 ;
     RECT  210.305 32.88 210.341 35.496 ;
     RECT  210.277 39.648 210.341 43.944 ;
     RECT  210.341 31.488 210.377 31.848 ;
     RECT  210.377 31.488 210.413 31.704 ;
     RECT  210.341 39.648 210.485 41.064 ;
     RECT  210.337 36.864 210.521 38.232 ;
     RECT  210.521 36.864 210.629 37.992 ;
     RECT  209.699 57.552 210.913 57.576 ;
     RECT  210.341 32.88 210.917 34.152 ;
     RECT  210.913 57.168 210.953 57.576 ;
     RECT  210.953 57.168 210.985 57.192 ;
     RECT  210.341 35.328 211.021 35.496 ;
     RECT  210.341 42.048 211.093 43.944 ;
     RECT  210.017 45.264 211.093 49.8 ;
     RECT  209.477 50.928 211.093 50.952 ;
     RECT  211.093 42.048 211.097 49.8 ;
     RECT  211.097 44.352 211.129 49.8 ;
     RECT  211.093 50.928 211.129 51 ;
     RECT  210.985 56.736 211.129 57.192 ;
     RECT  211.129 44.352 211.133 51 ;
     RECT  210.629 36.864 211.345 37.608 ;
     RECT  210.413 31.68 211.381 31.704 ;
     RECT  211.133 44.352 211.421 48.936 ;
     RECT  209.881 55.248 211.445 55.272 ;
     RECT  211.445 54.672 211.529 55.272 ;
     RECT  210.485 39.744 211.561 41.064 ;
     RECT  211.097 42.048 211.561 43.368 ;
     RECT  211.561 39.744 211.565 43.368 ;
     RECT  211.421 44.64 211.565 48.936 ;
     RECT  211.133 50.4 211.669 51 ;
     RECT  211.565 40.848 211.673 43.368 ;
     RECT  211.565 44.64 211.745 45.624 ;
     RECT  211.669 50.4 211.781 51.336 ;
     RECT  211.781 50.976 211.817 51.336 ;
     RECT  211.381 31.392 211.849 31.704 ;
     RECT  211.849 31.344 211.993 31.704 ;
     RECT  210.917 33.312 211.993 34.152 ;
     RECT  211.129 56.544 212.033 57.192 ;
     RECT  211.565 46.8 212.461 48.936 ;
     RECT  211.529 55.248 212.497 55.272 ;
     RECT  212.033 56.544 212.497 56.568 ;
     RECT  211.993 31.344 212.533 34.152 ;
     RECT  211.021 35.328 212.533 35.736 ;
     RECT  211.673 41.376 212.641 43.368 ;
     RECT  211.745 44.64 212.641 45.288 ;
     RECT  210.301 29.328 213.008 29.4 ;
     RECT  212.533 31.344 213.008 35.736 ;
     RECT  211.345 36.816 213.008 37.608 ;
     RECT  211.565 39.744 213.008 39.768 ;
     RECT  212.641 41.376 213.008 45.288 ;
     RECT  212.461 46.8 213.008 49.08 ;
     RECT  211.817 51.312 213.008 51.336 ;
     RECT  212.497 55.248 213.008 56.568 ;
     RECT  213.008 2.148 213.112 123.132 ;
     RECT  213.112 2.418 213.304 122.862 ;
     RECT  213.304 55.248 213.437 56.904 ;
     RECT  213.437 56.064 213.797 56.904 ;
     RECT  213.304 29.52 214.297 37.608 ;
     RECT  213.304 38.592 214.297 39.768 ;
     RECT  213.304 40.848 214.297 49.272 ;
     RECT  213.304 50.592 214.297 50.616 ;
     RECT  214.297 29.52 214.331 39.768 ;
     RECT  214.331 29.52 214.369 39.816 ;
     RECT  214.297 40.848 214.369 50.616 ;
     RECT  214.369 29.52 214.405 50.616 ;
     RECT  213.797 56.88 214.585 56.904 ;
     RECT  214.369 58.128 214.585 58.152 ;
     RECT  214.405 29.52 215.125 50.712 ;
     RECT  215.125 29.52 215.129 51.432 ;
     RECT  215.129 29.52 215.197 29.784 ;
     RECT  214.585 56.88 215.561 58.152 ;
     RECT  215.561 57.072 215.885 58.152 ;
     RECT  215.129 30.864 216.133 51.432 ;
     RECT  215.197 29.136 216.205 29.784 ;
     RECT  216.133 30.864 216.205 51.528 ;
     RECT  216.205 29.136 216.389 51.528 ;
     RECT  216.389 29.616 216.749 51.528 ;
     RECT  215.885 57.456 216.785 58.152 ;
     RECT  216.749 31.344 216.925 51.528 ;
     RECT  216.925 31.344 216.929 51.72 ;
     RECT  216.929 48.288 217.001 51.72 ;
     RECT  216.817 56.304 217.285 56.328 ;
     RECT  217.285 55.344 217.357 56.328 ;
     RECT  217.357 54.96 217.609 56.328 ;
     RECT  216.749 29.616 217.753 30.12 ;
     RECT  217.001 48.528 217.757 51.72 ;
     RECT  216.929 31.344 217.793 47.304 ;
     RECT  217.753 29.616 217.933 30.216 ;
     RECT  217.793 31.344 217.933 38.136 ;
     RECT  217.933 29.616 218.005 38.136 ;
     RECT  217.609 54.864 218.005 56.328 ;
     RECT  216.785 57.456 218.005 57.48 ;
     RECT  218.005 54.864 218.185 57.48 ;
     RECT  217.757 48.528 218.257 51.048 ;
     RECT  218.005 29.136 218.797 38.136 ;
     RECT  217.793 39.12 218.797 47.304 ;
     RECT  218.797 29.136 218.869 47.304 ;
     RECT  218.257 48.336 218.869 51.048 ;
     RECT  218.185 54.864 218.869 57.576 ;
     RECT  218.869 29.136 219.337 51.048 ;
     RECT  218.869 54.48 220.165 57.576 ;
     RECT  219.337 29.136 220.284 51.336 ;
     RECT  220.165 54.48 220.284 57.672 ;
    LAYER M5 ;
     RECT  2.4 2.137 2.52 2.151 ;
     RECT  7.8 2.137 7.92 2.151 ;
     RECT  13.2 2.137 13.32 2.151 ;
     RECT  18.6 2.137 18.72 2.151 ;
     RECT  24 2.137 24.12 2.151 ;
     RECT  29.4 2.137 29.52 2.151 ;
     RECT  34.8 2.137 34.92 2.151 ;
     RECT  40.2 2.137 40.32 2.151 ;
     RECT  45.6 2.137 45.72 2.151 ;
     RECT  51 2.137 51.12 2.151 ;
     RECT  56.4 2.137 56.52 2.151 ;
     RECT  61.8 2.137 61.92 2.151 ;
     RECT  67.2 2.137 67.32 2.151 ;
     RECT  72.6 2.137 72.72 2.151 ;
     RECT  78 2.137 78.12 2.151 ;
     RECT  83.4 2.137 83.52 2.151 ;
     RECT  88.8 2.137 88.92 2.151 ;
     RECT  94.2 2.137 94.32 2.151 ;
     RECT  99.6 2.137 99.72 2.151 ;
     RECT  105 2.137 105.12 2.151 ;
     RECT  110.4 2.137 110.52 2.151 ;
     RECT  115.8 2.137 115.92 2.151 ;
     RECT  121.2 2.137 121.32 2.151 ;
     RECT  126.6 2.137 126.72 2.151 ;
     RECT  132 2.137 132.12 2.151 ;
     RECT  137.4 2.137 137.52 2.151 ;
     RECT  142.8 2.137 142.92 2.151 ;
     RECT  148.2 2.137 148.32 2.151 ;
     RECT  153.6 2.137 153.72 2.151 ;
     RECT  159 2.137 159.12 2.151 ;
     RECT  164.4 2.137 164.52 2.151 ;
     RECT  169.8 2.137 169.92 2.151 ;
     RECT  175.2 2.137 175.32 2.151 ;
     RECT  180.6 2.137 180.72 2.151 ;
     RECT  186 2.137 186.12 2.151 ;
     RECT  191.4 2.137 191.52 2.151 ;
     RECT  196.8 2.137 196.92 2.151 ;
     RECT  202.2 2.137 202.32 2.151 ;
     RECT  207.6 2.137 207.72 2.151 ;
     RECT  213 2.137 213.12 2.151 ;
     RECT  202.2 2.151 202.512 19.477 ;
     RECT  18.6 2.151 18.912 19.525 ;
     RECT  198.096 19.765 198.12 20.293 ;
     RECT  18.6 19.525 19.8 20.869 ;
     RECT  78 2.151 78.312 21.061 ;
     RECT  198.096 20.293 198.6 21.397 ;
     RECT  200.784 19.813 200.808 21.925 ;
     RECT  77.904 21.061 78.312 22.499 ;
     RECT  196.8 2.151 197.112 23.557 ;
     RECT  198.096 21.397 199.128 23.557 ;
     RECT  196.8 23.557 199.128 23.605 ;
     RECT  67.2 2.151 67.512 23.653 ;
     RECT  196.8 23.605 199.224 23.797 ;
     RECT  2.4 2.151 2.712 23.845 ;
     RECT  5.52 21.397 5.544 23.893 ;
     RECT  5.52 23.893 5.688 24.085 ;
     RECT  196.8 23.797 199.512 24.181 ;
     RECT  196.8 24.181 199.56 24.421 ;
     RECT  200.64 21.925 200.808 24.421 ;
     RECT  91.44 23.701 91.464 24.613 ;
     RECT  91.2 24.613 91.464 24.659 ;
     RECT  22.56 24.373 22.584 24.709 ;
     RECT  2.4 23.845 3.672 24.901 ;
     RECT  91.2 24.659 91.224 24.947 ;
     RECT  189.84 24.661 189.864 24.949 ;
     RECT  22.56 24.709 22.824 24.995 ;
     RECT  189.84 24.949 190.152 24.995 ;
     RECT  176.784 24.901 176.808 24.997 ;
     RECT  176.688 24.997 176.808 25.043 ;
     RECT  67.104 23.653 67.512 25.139 ;
     RECT  81.36 24.325 81.384 25.187 ;
     RECT  7.8 2.151 8.112 25.189 ;
     RECT  51 2.151 51.312 25.189 ;
     RECT  210 24.901 210.024 25.189 ;
     RECT  5.52 24.085 6.216 25.237 ;
     RECT  7.536 25.189 8.112 25.237 ;
     RECT  45.6 2.151 45.912 25.237 ;
     RECT  105 2.151 105.312 25.429 ;
     RECT  202.032 19.477 202.512 25.429 ;
     RECT  5.52 25.237 8.112 25.477 ;
     RECT  59.232 25.237 59.256 25.715 ;
     RECT  64.368 25.189 64.392 25.715 ;
     RECT  182.304 19.477 182.328 25.715 ;
     RECT  190.128 24.995 190.152 25.715 ;
     RECT  176.688 25.043 176.712 25.811 ;
     RECT  107.712 25.621 107.736 25.957 ;
     RECT  83.4 2.151 83.712 26.197 ;
     RECT  210 25.189 210.264 26.341 ;
     RECT  105 25.429 106.296 26.435 ;
     RECT  82.608 26.197 83.712 26.675 ;
     RECT  22.56 24.995 22.584 26.677 ;
     RECT  105 26.435 106.008 26.723 ;
     RECT  107.712 25.957 108.12 26.771 ;
     RECT  22.56 26.677 22.632 27.301 ;
     RECT  51 25.189 51.432 27.635 ;
     RECT  196.8 24.421 200.808 27.685 ;
     RECT  202.032 25.429 202.824 27.685 ;
     RECT  45.6 25.237 46.2 27.731 ;
     RECT  22.464 27.301 22.632 27.877 ;
     RECT  22.464 27.877 22.776 28.355 ;
     RECT  2.4 24.901 4.248 28.837 ;
     RECT  5.328 25.477 8.112 28.837 ;
     RECT  207.6 2.151 207.912 29.365 ;
     RECT  209.424 26.341 210.264 29.365 ;
     RECT  22.464 28.355 22.632 30.037 ;
     RECT  21.696 30.037 22.632 30.227 ;
     RECT  0.192 30.133 0.216 30.373 ;
     RECT  22.464 30.227 22.632 30.757 ;
     RECT  218.304 30.757 218.328 30.899 ;
     RECT  220.128 30.853 220.152 31.043 ;
     RECT  0.144 30.373 0.216 31.427 ;
     RECT  2.4 28.837 8.112 31.475 ;
     RECT  22.464 30.757 22.776 31.573 ;
     RECT  0.192 31.427 0.216 31.763 ;
     RECT  22.464 31.573 22.824 31.763 ;
     RECT  2.4 31.475 4.248 32.437 ;
     RECT  5.28 31.475 8.112 32.437 ;
     RECT  213 2.151 213.312 32.437 ;
     RECT  0.336 32.677 0.36 32.821 ;
     RECT  212.88 32.437 213.312 32.867 ;
     RECT  2.4 32.437 8.112 33.013 ;
     RECT  0.192 32.821 0.36 33.107 ;
     RECT  0.288 33.107 0.36 33.203 ;
     RECT  2.4 33.013 8.328 33.251 ;
     RECT  0.336 33.203 0.36 33.299 ;
     RECT  5.28 33.251 8.328 33.299 ;
     RECT  5.328 33.299 8.328 33.973 ;
     RECT  206.256 25.717 206.28 34.165 ;
     RECT  207.6 29.365 210.264 34.165 ;
     RECT  204.192 33.541 204.216 34.211 ;
     RECT  2.4 33.251 4.248 34.645 ;
     RECT  5.328 33.973 8.76 34.645 ;
     RECT  18.6 20.869 20.232 34.789 ;
     RECT  18.6 34.789 20.28 34.931 ;
     RECT  206.256 34.165 210.264 35.363 ;
     RECT  0.144 34.453 0.168 35.701 ;
     RECT  206.256 35.363 207.912 35.939 ;
     RECT  0.144 35.701 0.36 36.371 ;
     RECT  0.144 36.371 0.312 36.515 ;
     RECT  209.088 35.363 210.264 36.515 ;
     RECT  207.6 35.939 207.912 36.997 ;
     RECT  213 32.867 213.312 37.429 ;
     RECT  213 37.429 214.248 37.619 ;
     RECT  207.6 36.997 208.488 37.667 ;
     RECT  196.8 27.685 202.824 37.669 ;
     RECT  196.8 37.669 203.496 37.955 ;
     RECT  1.152 37.909 1.176 37.957 ;
     RECT  206.256 35.939 206.28 38.005 ;
     RECT  217.44 38.005 217.464 38.147 ;
     RECT  1.152 37.957 1.272 38.195 ;
     RECT  2.4 34.645 8.76 38.243 ;
     RECT  0.144 36.515 0.168 38.245 ;
     RECT  22.464 31.763 22.632 38.245 ;
     RECT  22.464 38.245 22.824 38.531 ;
     RECT  0.144 38.245 0.408 39.011 ;
     RECT  2.4 38.243 8.112 39.109 ;
     RECT  18.6 34.931 20.232 39.157 ;
     RECT  18.6 39.157 21.096 39.347 ;
     RECT  0.24 39.011 0.408 39.589 ;
     RECT  209.472 36.515 210.264 39.637 ;
     RECT  0.24 39.589 0.456 40.261 ;
     RECT  205.776 38.005 206.28 40.499 ;
     RECT  209.472 39.637 210.312 40.499 ;
     RECT  209.472 40.499 210.264 40.691 ;
     RECT  0.192 40.261 0.456 41.267 ;
     RECT  0.192 41.267 0.408 41.317 ;
     RECT  0.144 41.317 0.408 41.507 ;
     RECT  206.256 40.499 206.28 41.509 ;
     RECT  0.192 41.507 0.408 41.699 ;
     RECT  204.288 40.309 204.312 41.939 ;
     RECT  205.296 41.509 206.28 41.987 ;
     RECT  0.336 41.699 0.408 42.227 ;
     RECT  2.304 39.109 8.112 42.709 ;
     RECT  213 37.619 213.312 42.757 ;
     RECT  2.304 42.709 8.232 42.803 ;
     RECT  196.8 37.955 202.824 42.803 ;
     RECT  0.384 42.227 0.408 43.043 ;
     RECT  18.6 39.347 20.232 43.043 ;
     RECT  212.544 42.757 213.312 43.379 ;
     RECT  2.4 42.803 8.232 43.475 ;
     RECT  22.464 38.531 22.632 43.571 ;
     RECT  220.128 43.573 220.152 43.763 ;
     RECT  209.472 40.691 210.072 43.955 ;
     RECT  22.464 43.571 22.584 44.099 ;
     RECT  5.328 43.475 8.232 44.723 ;
     RECT  209.472 43.955 210.024 46.069 ;
     RECT  209.472 46.069 210.408 46.117 ;
     RECT  207.6 37.667 207.912 46.357 ;
     RECT  18.6 43.043 19.8 47.459 ;
     RECT  207.6 46.357 208.008 47.747 ;
     RECT  209.28 46.117 210.408 47.747 ;
     RECT  207.6 47.747 207.912 48.085 ;
     RECT  204.48 47.749 204.504 48.131 ;
     RECT  206.256 41.987 206.28 48.515 ;
     RECT  220.128 48.709 220.152 48.899 ;
     RECT  209.28 47.747 210.024 49.571 ;
     RECT  207.504 48.085 207.912 50.101 ;
     RECT  204.864 50.677 204.888 50.819 ;
     RECT  206.784 50.101 207.912 50.963 ;
     RECT  196.8 42.803 202.512 52.693 ;
     RECT  196.8 52.693 202.776 52.981 ;
     RECT  207.6 50.963 207.912 52.981 ;
     RECT  204.576 53.269 204.6 53.411 ;
     RECT  2.4 43.475 4.248 53.461 ;
     RECT  5.328 44.723 8.112 53.461 ;
     RECT  2.4 53.461 8.112 53.557 ;
     RECT  196.8 52.981 202.968 53.603 ;
     RECT  0.192 53.509 0.216 53.893 ;
     RECT  0.192 53.893 0.264 53.941 ;
     RECT  0.192 53.941 0.36 54.085 ;
     RECT  206.88 52.981 207.912 54.707 ;
     RECT  204.24 54.661 204.264 55.043 ;
     RECT  0.144 54.085 0.36 55.141 ;
     RECT  211.488 54.661 211.512 55.283 ;
     RECT  209.28 49.571 209.832 55.907 ;
     RECT  0.144 55.141 0.408 57.013 ;
     RECT  2.304 53.557 8.112 57.877 ;
     RECT  209.28 55.907 209.304 57.973 ;
     RECT  2.304 57.877 8.52 58.163 ;
     RECT  2.304 58.163 6.072 59.173 ;
     RECT  7.248 58.163 8.52 59.173 ;
     RECT  0.144 57.013 0.552 59.411 ;
     RECT  2.304 59.173 8.52 59.891 ;
     RECT  2.304 59.891 8.112 60.037 ;
     RECT  1.824 60.037 8.112 60.179 ;
     RECT  2.304 60.179 8.112 60.467 ;
     RECT  18.6 47.459 19.752 60.467 ;
     RECT  0.144 59.411 0.36 60.563 ;
     RECT  22.464 44.099 22.536 60.757 ;
     RECT  196.8 53.603 202.512 60.851 ;
     RECT  0.144 60.563 0.312 60.899 ;
     RECT  22.464 60.757 22.824 60.947 ;
     RECT  209.28 57.973 209.688 61.043 ;
     RECT  22.464 60.947 22.488 61.379 ;
     RECT  196.8 60.851 201.144 61.475 ;
     RECT  0.192 60.899 0.312 61.861 ;
     RECT  7.248 60.467 8.112 62.005 ;
     RECT  18.6 60.467 18.912 62.101 ;
     RECT  2.304 60.467 6.072 62.195 ;
     RECT  0.144 61.861 0.408 62.245 ;
     RECT  2.304 62.195 5.592 62.291 ;
     RECT  196.8 61.475 197.112 62.629 ;
     RECT  198.144 61.475 201.144 62.629 ;
     RECT  7.056 62.005 8.112 62.677 ;
     RECT  2.304 62.291 5.496 62.771 ;
     RECT  6.864 62.677 8.112 62.819 ;
     RECT  0.144 62.245 0.552 62.963 ;
     RECT  196.8 62.629 201.144 63.059 ;
     RECT  3.888 62.771 5.496 63.299 ;
     RECT  0.144 62.963 0.456 64.019 ;
     RECT  0.144 64.019 0.36 64.211 ;
     RECT  2.304 62.771 2.856 64.309 ;
     RECT  4.08 63.299 5.496 64.309 ;
     RECT  2.304 64.309 5.496 64.357 ;
     RECT  7.056 62.819 8.112 64.357 ;
     RECT  18.6 62.101 19.656 64.357 ;
     RECT  0.144 64.211 0.312 65.171 ;
     RECT  0.144 65.171 0.264 67.379 ;
     RECT  2.304 64.357 8.112 67.859 ;
     RECT  0.144 67.379 0.168 67.907 ;
     RECT  2.304 67.859 6.264 68.387 ;
     RECT  2.304 68.387 6.12 68.483 ;
     RECT  2.304 68.483 4.968 68.579 ;
     RECT  18.6 64.357 19.752 69.493 ;
     RECT  2.304 68.579 3.96 69.587 ;
     RECT  4.944 68.579 4.968 69.587 ;
     RECT  2.4 69.587 3.96 69.635 ;
     RECT  2.4 69.635 3.72 69.779 ;
     RECT  6.096 68.483 6.12 74.723 ;
     RECT  3.696 69.779 3.72 89.795 ;
     RECT  196.8 63.059 200.568 92.435 ;
     RECT  196.8 92.435 200.424 92.963 ;
     RECT  108.096 26.771 108.12 100.355 ;
     RECT  67.2 25.139 67.512 100.549 ;
     RECT  66.672 100.549 67.512 101.029 ;
     RECT  45.6 27.731 45.912 101.317 ;
     RECT  18.6 69.493 19.8 101.603 ;
     RECT  66.624 101.029 67.512 102.659 ;
     RECT  66.672 102.659 67.512 102.755 ;
     RECT  45.6 101.317 46.728 103.235 ;
     RECT  196.8 92.963 200.328 103.523 ;
     RECT  209.28 61.043 209.304 108.323 ;
     RECT  198.672 103.523 200.328 108.325 ;
     RECT  198.672 108.325 200.424 122.579 ;
     RECT  2.4 69.779 2.712 123.129 ;
     RECT  7.8 67.859 8.112 123.129 ;
     RECT  13.2 2.151 13.512 123.129 ;
     RECT  18.6 101.603 18.912 123.129 ;
     RECT  24 2.151 24.312 123.129 ;
     RECT  29.4 2.151 29.712 123.129 ;
     RECT  34.8 2.151 35.112 123.129 ;
     RECT  40.2 2.151 40.512 123.129 ;
     RECT  45.6 103.235 45.912 123.129 ;
     RECT  51 27.635 51.312 123.129 ;
     RECT  56.4 2.151 56.712 123.129 ;
     RECT  61.8 2.151 62.112 123.129 ;
     RECT  67.2 102.755 67.512 123.129 ;
     RECT  72.6 2.151 72.912 123.129 ;
     RECT  78 22.499 78.312 123.129 ;
     RECT  83.4 26.675 83.712 123.129 ;
     RECT  88.8 2.151 89.112 123.129 ;
     RECT  94.2 2.151 94.512 123.129 ;
     RECT  99.6 2.151 99.912 123.129 ;
     RECT  105 26.723 105.312 123.129 ;
     RECT  110.4 2.151 110.712 123.129 ;
     RECT  115.8 2.151 116.112 123.129 ;
     RECT  121.2 2.151 121.512 123.129 ;
     RECT  126.6 2.151 126.912 123.129 ;
     RECT  132 2.151 132.312 123.129 ;
     RECT  137.4 2.151 137.712 123.129 ;
     RECT  142.8 2.151 143.112 123.129 ;
     RECT  148.2 2.151 148.512 123.129 ;
     RECT  153.6 2.151 153.912 123.129 ;
     RECT  159 2.151 159.312 123.129 ;
     RECT  164.4 2.151 164.712 123.129 ;
     RECT  169.8 2.151 170.112 123.129 ;
     RECT  175.2 2.151 175.512 123.129 ;
     RECT  180.6 2.151 180.912 123.129 ;
     RECT  186 2.151 186.312 123.129 ;
     RECT  191.4 2.151 191.712 123.129 ;
     RECT  196.8 103.523 197.112 123.129 ;
     RECT  202.2 60.851 202.512 123.129 ;
     RECT  207.6 54.707 207.912 123.129 ;
     RECT  213 43.379 213.312 123.129 ;
     RECT  2.4 123.129 2.52 123.143 ;
     RECT  7.8 123.129 7.92 123.143 ;
     RECT  13.2 123.129 13.32 123.143 ;
     RECT  18.6 123.129 18.72 123.143 ;
     RECT  24 123.129 24.12 123.143 ;
     RECT  29.4 123.129 29.52 123.143 ;
     RECT  34.8 123.129 34.92 123.143 ;
     RECT  40.2 123.129 40.32 123.143 ;
     RECT  45.6 123.129 45.72 123.143 ;
     RECT  51 123.129 51.12 123.143 ;
     RECT  56.4 123.129 56.52 123.143 ;
     RECT  61.8 123.129 61.92 123.143 ;
     RECT  67.2 123.129 67.32 123.143 ;
     RECT  72.6 123.129 72.72 123.143 ;
     RECT  78 123.129 78.12 123.143 ;
     RECT  83.4 123.129 83.52 123.143 ;
     RECT  88.8 123.129 88.92 123.143 ;
     RECT  94.2 123.129 94.32 123.143 ;
     RECT  99.6 123.129 99.72 123.143 ;
     RECT  105 123.129 105.12 123.143 ;
     RECT  110.4 123.129 110.52 123.143 ;
     RECT  115.8 123.129 115.92 123.143 ;
     RECT  121.2 123.129 121.32 123.143 ;
     RECT  126.6 123.129 126.72 123.143 ;
     RECT  132 123.129 132.12 123.143 ;
     RECT  137.4 123.129 137.52 123.143 ;
     RECT  142.8 123.129 142.92 123.143 ;
     RECT  148.2 123.129 148.32 123.143 ;
     RECT  153.6 123.129 153.72 123.143 ;
     RECT  159 123.129 159.12 123.143 ;
     RECT  164.4 123.129 164.52 123.143 ;
     RECT  169.8 123.129 169.92 123.143 ;
     RECT  175.2 123.129 175.32 123.143 ;
     RECT  180.6 123.129 180.72 123.143 ;
     RECT  186 123.129 186.12 123.143 ;
     RECT  191.4 123.129 191.52 123.143 ;
     RECT  196.8 123.129 196.92 123.143 ;
     RECT  202.2 123.129 202.32 123.143 ;
     RECT  207.6 123.129 207.72 123.143 ;
     RECT  213 123.129 213.12 123.143 ;
     RECT  199.008 122.579 200.424 125.171 ;
     RECT  199.152 125.171 200.328 125.264 ;
  END
END ot_hgi_hc_residual_half_static
END LIBRARY
